VERSION 5.8 ;
BUSBITCHARS "[]" ;
DIVIDERCHAR "/" ;
UNITS
    DATABASE MICRONS 1000 ;
END UNITS

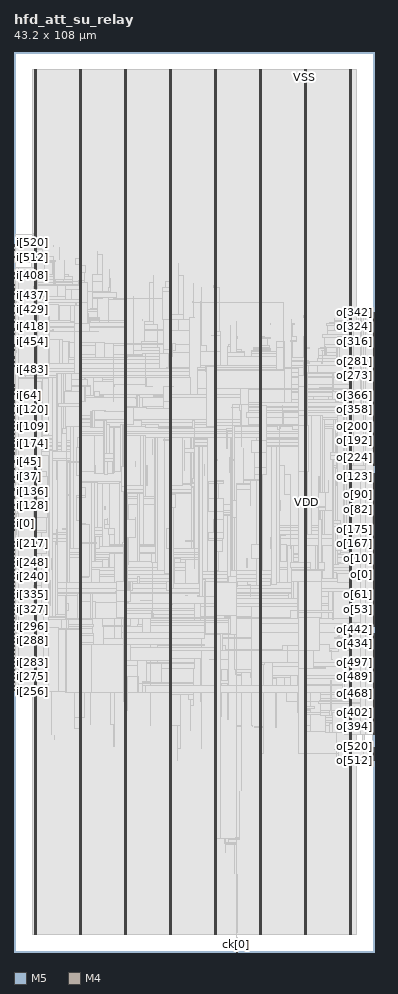
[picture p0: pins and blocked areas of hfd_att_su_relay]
MACRO hfd_att_su_relay
  FOREIGN hfd_att_su_relay 0 0 ;
  CLASS BLOCK ;
  SIZE 43.2 BY 108 ;
  PIN ck[0]
    DIRECTION INPUT ;
    USE SIGNAL ;
    PORT
      LAYER M5 ;
        RECT  26.64 0 26.664 0.084 ;
    END
  END ck[0]
  PIN i[0]
    DIRECTION INPUT ;
    USE SIGNAL ;
    PORT
      LAYER M4 ;
        RECT  0 50.448 0.084 50.472 ;
    END
  END i[0]
  PIN i[100]
    DIRECTION INPUT ;
    USE SIGNAL ;
    PORT
      LAYER M4 ;
        RECT  0 63.12 0.084 63.144 ;
    END
  END i[100]
  PIN i[101]
    DIRECTION INPUT ;
    USE SIGNAL ;
    PORT
      LAYER M4 ;
        RECT  0 63.216 0.084 63.24 ;
    END
  END i[101]
  PIN i[102]
    DIRECTION INPUT ;
    USE SIGNAL ;
    PORT
      LAYER M4 ;
        RECT  0 63.312 0.084 63.336 ;
    END
  END i[102]
  PIN i[103]
    DIRECTION INPUT ;
    USE SIGNAL ;
    PORT
      LAYER M4 ;
        RECT  0 63.408 0.084 63.432 ;
    END
  END i[103]
  PIN i[104]
    DIRECTION INPUT ;
    USE SIGNAL ;
    PORT
      LAYER M4 ;
        RECT  0 63.504 0.084 63.528 ;
    END
  END i[104]
  PIN i[105]
    DIRECTION INPUT ;
    USE SIGNAL ;
    PORT
      LAYER M4 ;
        RECT  0 63.6 0.084 63.624 ;
    END
  END i[105]
  PIN i[106]
    DIRECTION INPUT ;
    USE SIGNAL ;
    PORT
      LAYER M4 ;
        RECT  0 63.696 0.084 63.72 ;
    END
  END i[106]
  PIN i[107]
    DIRECTION INPUT ;
    USE SIGNAL ;
    PORT
      LAYER M4 ;
        RECT  0 63.792 0.084 63.816 ;
    END
  END i[107]
  PIN i[108]
    DIRECTION INPUT ;
    USE SIGNAL ;
    PORT
      LAYER M4 ;
        RECT  0 63.888 0.084 63.912 ;
    END
  END i[108]
  PIN i[109]
    DIRECTION INPUT ;
    USE SIGNAL ;
    PORT
      LAYER M4 ;
        RECT  0 63.984 0.084 64.008 ;
    END
  END i[109]
  PIN i[10]
    DIRECTION INPUT ;
    USE SIGNAL ;
    PORT
      LAYER M4 ;
        RECT  0 51.408 0.084 51.432 ;
    END
  END i[10]
  PIN i[110]
    DIRECTION INPUT ;
    USE SIGNAL ;
    PORT
      LAYER M4 ;
        RECT  0 64.08 0.084 64.104 ;
    END
  END i[110]
  PIN i[111]
    DIRECTION INPUT ;
    USE SIGNAL ;
    PORT
      LAYER M4 ;
        RECT  0 64.176 0.084 64.2 ;
    END
  END i[111]
  PIN i[112]
    DIRECTION INPUT ;
    USE SIGNAL ;
    PORT
      LAYER M4 ;
        RECT  0 64.272 0.084 64.296 ;
    END
  END i[112]
  PIN i[113]
    DIRECTION INPUT ;
    USE SIGNAL ;
    PORT
      LAYER M4 ;
        RECT  0 64.368 0.084 64.392 ;
    END
  END i[113]
  PIN i[114]
    DIRECTION INPUT ;
    USE SIGNAL ;
    PORT
      LAYER M4 ;
        RECT  0 64.464 0.084 64.488 ;
    END
  END i[114]
  PIN i[115]
    DIRECTION INPUT ;
    USE SIGNAL ;
    PORT
      LAYER M4 ;
        RECT  0 64.56 0.084 64.584 ;
    END
  END i[115]
  PIN i[116]
    DIRECTION INPUT ;
    USE SIGNAL ;
    PORT
      LAYER M4 ;
        RECT  0 64.656 0.084 64.68 ;
    END
  END i[116]
  PIN i[117]
    DIRECTION INPUT ;
    USE SIGNAL ;
    PORT
      LAYER M4 ;
        RECT  0 64.752 0.084 64.776 ;
    END
  END i[117]
  PIN i[118]
    DIRECTION INPUT ;
    USE SIGNAL ;
    PORT
      LAYER M4 ;
        RECT  0 64.848 0.084 64.872 ;
    END
  END i[118]
  PIN i[119]
    DIRECTION INPUT ;
    USE SIGNAL ;
    PORT
      LAYER M4 ;
        RECT  0 64.944 0.084 64.968 ;
    END
  END i[119]
  PIN i[11]
    DIRECTION INPUT ;
    USE SIGNAL ;
    PORT
      LAYER M4 ;
        RECT  0 51.504 0.084 51.528 ;
    END
  END i[11]
  PIN i[120]
    DIRECTION INPUT ;
    USE SIGNAL ;
    PORT
      LAYER M4 ;
        RECT  0 65.04 0.084 65.064 ;
    END
  END i[120]
  PIN i[121]
    DIRECTION INPUT ;
    USE SIGNAL ;
    PORT
      LAYER M4 ;
        RECT  0 65.136 0.084 65.16 ;
    END
  END i[121]
  PIN i[122]
    DIRECTION INPUT ;
    USE SIGNAL ;
    PORT
      LAYER M4 ;
        RECT  0 65.232 0.084 65.256 ;
    END
  END i[122]
  PIN i[123]
    DIRECTION INPUT ;
    USE SIGNAL ;
    PORT
      LAYER M4 ;
        RECT  0 65.328 0.084 65.352 ;
    END
  END i[123]
  PIN i[124]
    DIRECTION INPUT ;
    USE SIGNAL ;
    PORT
      LAYER M4 ;
        RECT  0 65.424 0.084 65.448 ;
    END
  END i[124]
  PIN i[125]
    DIRECTION INPUT ;
    USE SIGNAL ;
    PORT
      LAYER M4 ;
        RECT  0 65.52 0.084 65.544 ;
    END
  END i[125]
  PIN i[126]
    DIRECTION INPUT ;
    USE SIGNAL ;
    PORT
      LAYER M4 ;
        RECT  0 65.616 0.084 65.64 ;
    END
  END i[126]
  PIN i[127]
    DIRECTION INPUT ;
    USE SIGNAL ;
    PORT
      LAYER M4 ;
        RECT  0 65.712 0.084 65.736 ;
    END
  END i[127]
  PIN i[128]
    DIRECTION INPUT ;
    USE SIGNAL ;
    PORT
      LAYER M4 ;
        RECT  0 53.52 0.084 53.544 ;
    END
  END i[128]
  PIN i[129]
    DIRECTION INPUT ;
    USE SIGNAL ;
    PORT
      LAYER M4 ;
        RECT  0 53.616 0.084 53.64 ;
    END
  END i[129]
  PIN i[12]
    DIRECTION INPUT ;
    USE SIGNAL ;
    PORT
      LAYER M4 ;
        RECT  0 51.6 0.084 51.624 ;
    END
  END i[12]
  PIN i[130]
    DIRECTION INPUT ;
    USE SIGNAL ;
    PORT
      LAYER M4 ;
        RECT  0 53.712 0.084 53.736 ;
    END
  END i[130]
  PIN i[131]
    DIRECTION INPUT ;
    USE SIGNAL ;
    PORT
      LAYER M4 ;
        RECT  0 53.808 0.084 53.832 ;
    END
  END i[131]
  PIN i[132]
    DIRECTION INPUT ;
    USE SIGNAL ;
    PORT
      LAYER M4 ;
        RECT  0 53.904 0.084 53.928 ;
    END
  END i[132]
  PIN i[133]
    DIRECTION INPUT ;
    USE SIGNAL ;
    PORT
      LAYER M4 ;
        RECT  0 54 0.084 54.024 ;
    END
  END i[133]
  PIN i[134]
    DIRECTION INPUT ;
    USE SIGNAL ;
    PORT
      LAYER M4 ;
        RECT  0 54.096 0.084 54.12 ;
    END
  END i[134]
  PIN i[135]
    DIRECTION INPUT ;
    USE SIGNAL ;
    PORT
      LAYER M4 ;
        RECT  0 54.192 0.084 54.216 ;
    END
  END i[135]
  PIN i[136]
    DIRECTION INPUT ;
    USE SIGNAL ;
    PORT
      LAYER M4 ;
        RECT  0 54.288 0.084 54.312 ;
    END
  END i[136]
  PIN i[137]
    DIRECTION INPUT ;
    USE SIGNAL ;
    PORT
      LAYER M4 ;
        RECT  0 54.384 0.084 54.408 ;
    END
  END i[137]
  PIN i[138]
    DIRECTION INPUT ;
    USE SIGNAL ;
    PORT
      LAYER M4 ;
        RECT  0 54.48 0.084 54.504 ;
    END
  END i[138]
  PIN i[139]
    DIRECTION INPUT ;
    USE SIGNAL ;
    PORT
      LAYER M4 ;
        RECT  0 54.576 0.084 54.6 ;
    END
  END i[139]
  PIN i[13]
    DIRECTION INPUT ;
    USE SIGNAL ;
    PORT
      LAYER M4 ;
        RECT  0 51.696 0.084 51.72 ;
    END
  END i[13]
  PIN i[140]
    DIRECTION INPUT ;
    USE SIGNAL ;
    PORT
      LAYER M4 ;
        RECT  0 54.672 0.084 54.696 ;
    END
  END i[140]
  PIN i[141]
    DIRECTION INPUT ;
    USE SIGNAL ;
    PORT
      LAYER M4 ;
        RECT  0 54.768 0.084 54.792 ;
    END
  END i[141]
  PIN i[142]
    DIRECTION INPUT ;
    USE SIGNAL ;
    PORT
      LAYER M4 ;
        RECT  0 54.864 0.084 54.888 ;
    END
  END i[142]
  PIN i[143]
    DIRECTION INPUT ;
    USE SIGNAL ;
    PORT
      LAYER M4 ;
        RECT  0 54.96 0.084 54.984 ;
    END
  END i[143]
  PIN i[144]
    DIRECTION INPUT ;
    USE SIGNAL ;
    PORT
      LAYER M4 ;
        RECT  0 55.056 0.084 55.08 ;
    END
  END i[144]
  PIN i[145]
    DIRECTION INPUT ;
    USE SIGNAL ;
    PORT
      LAYER M4 ;
        RECT  0 55.152 0.084 55.176 ;
    END
  END i[145]
  PIN i[146]
    DIRECTION INPUT ;
    USE SIGNAL ;
    PORT
      LAYER M4 ;
        RECT  0 55.248 0.084 55.272 ;
    END
  END i[146]
  PIN i[147]
    DIRECTION INPUT ;
    USE SIGNAL ;
    PORT
      LAYER M4 ;
        RECT  0 55.344 0.084 55.368 ;
    END
  END i[147]
  PIN i[148]
    DIRECTION INPUT ;
    USE SIGNAL ;
    PORT
      LAYER M4 ;
        RECT  0 55.44 0.084 55.464 ;
    END
  END i[148]
  PIN i[149]
    DIRECTION INPUT ;
    USE SIGNAL ;
    PORT
      LAYER M4 ;
        RECT  0 55.536 0.084 55.56 ;
    END
  END i[149]
  PIN i[14]
    DIRECTION INPUT ;
    USE SIGNAL ;
    PORT
      LAYER M4 ;
        RECT  0 51.792 0.084 51.816 ;
    END
  END i[14]
  PIN i[150]
    DIRECTION INPUT ;
    USE SIGNAL ;
    PORT
      LAYER M4 ;
        RECT  0 55.632 0.084 55.656 ;
    END
  END i[150]
  PIN i[151]
    DIRECTION INPUT ;
    USE SIGNAL ;
    PORT
      LAYER M4 ;
        RECT  0 55.728 0.084 55.752 ;
    END
  END i[151]
  PIN i[152]
    DIRECTION INPUT ;
    USE SIGNAL ;
    PORT
      LAYER M4 ;
        RECT  0 55.824 0.084 55.848 ;
    END
  END i[152]
  PIN i[153]
    DIRECTION INPUT ;
    USE SIGNAL ;
    PORT
      LAYER M4 ;
        RECT  0 55.92 0.084 55.944 ;
    END
  END i[153]
  PIN i[154]
    DIRECTION INPUT ;
    USE SIGNAL ;
    PORT
      LAYER M4 ;
        RECT  0 56.016 0.084 56.04 ;
    END
  END i[154]
  PIN i[155]
    DIRECTION INPUT ;
    USE SIGNAL ;
    PORT
      LAYER M4 ;
        RECT  0 56.112 0.084 56.136 ;
    END
  END i[155]
  PIN i[156]
    DIRECTION INPUT ;
    USE SIGNAL ;
    PORT
      LAYER M4 ;
        RECT  0 56.208 0.084 56.232 ;
    END
  END i[156]
  PIN i[157]
    DIRECTION INPUT ;
    USE SIGNAL ;
    PORT
      LAYER M4 ;
        RECT  0 56.304 0.084 56.328 ;
    END
  END i[157]
  PIN i[158]
    DIRECTION INPUT ;
    USE SIGNAL ;
    PORT
      LAYER M4 ;
        RECT  0 56.4 0.084 56.424 ;
    END
  END i[158]
  PIN i[159]
    DIRECTION INPUT ;
    USE SIGNAL ;
    PORT
      LAYER M4 ;
        RECT  0 56.496 0.084 56.52 ;
    END
  END i[159]
  PIN i[15]
    DIRECTION INPUT ;
    USE SIGNAL ;
    PORT
      LAYER M4 ;
        RECT  0 51.888 0.084 51.912 ;
    END
  END i[15]
  PIN i[160]
    DIRECTION INPUT ;
    USE SIGNAL ;
    PORT
      LAYER M4 ;
        RECT  0 59.664 0.084 59.688 ;
    END
  END i[160]
  PIN i[161]
    DIRECTION INPUT ;
    USE SIGNAL ;
    PORT
      LAYER M4 ;
        RECT  0 59.76 0.084 59.784 ;
    END
  END i[161]
  PIN i[162]
    DIRECTION INPUT ;
    USE SIGNAL ;
    PORT
      LAYER M4 ;
        RECT  0 59.856 0.084 59.88 ;
    END
  END i[162]
  PIN i[163]
    DIRECTION INPUT ;
    USE SIGNAL ;
    PORT
      LAYER M4 ;
        RECT  0 59.952 0.084 59.976 ;
    END
  END i[163]
  PIN i[164]
    DIRECTION INPUT ;
    USE SIGNAL ;
    PORT
      LAYER M4 ;
        RECT  0 60.048 0.084 60.072 ;
    END
  END i[164]
  PIN i[165]
    DIRECTION INPUT ;
    USE SIGNAL ;
    PORT
      LAYER M4 ;
        RECT  0 60.144 0.084 60.168 ;
    END
  END i[165]
  PIN i[166]
    DIRECTION INPUT ;
    USE SIGNAL ;
    PORT
      LAYER M4 ;
        RECT  0 60.24 0.084 60.264 ;
    END
  END i[166]
  PIN i[167]
    DIRECTION INPUT ;
    USE SIGNAL ;
    PORT
      LAYER M4 ;
        RECT  0 60.336 0.084 60.36 ;
    END
  END i[167]
  PIN i[168]
    DIRECTION INPUT ;
    USE SIGNAL ;
    PORT
      LAYER M4 ;
        RECT  0 60.432 0.084 60.456 ;
    END
  END i[168]
  PIN i[169]
    DIRECTION INPUT ;
    USE SIGNAL ;
    PORT
      LAYER M4 ;
        RECT  0 60.528 0.084 60.552 ;
    END
  END i[169]
  PIN i[16]
    DIRECTION INPUT ;
    USE SIGNAL ;
    PORT
      LAYER M4 ;
        RECT  0 51.984 0.084 52.008 ;
    END
  END i[16]
  PIN i[170]
    DIRECTION INPUT ;
    USE SIGNAL ;
    PORT
      LAYER M4 ;
        RECT  0 60.624 0.084 60.648 ;
    END
  END i[170]
  PIN i[171]
    DIRECTION INPUT ;
    USE SIGNAL ;
    PORT
      LAYER M4 ;
        RECT  0 60.72 0.084 60.744 ;
    END
  END i[171]
  PIN i[172]
    DIRECTION INPUT ;
    USE SIGNAL ;
    PORT
      LAYER M4 ;
        RECT  0 60.816 0.084 60.84 ;
    END
  END i[172]
  PIN i[173]
    DIRECTION INPUT ;
    USE SIGNAL ;
    PORT
      LAYER M4 ;
        RECT  0 60.912 0.084 60.936 ;
    END
  END i[173]
  PIN i[174]
    DIRECTION INPUT ;
    USE SIGNAL ;
    PORT
      LAYER M4 ;
        RECT  0 61.008 0.084 61.032 ;
    END
  END i[174]
  PIN i[175]
    DIRECTION INPUT ;
    USE SIGNAL ;
    PORT
      LAYER M4 ;
        RECT  0 61.104 0.084 61.128 ;
    END
  END i[175]
  PIN i[176]
    DIRECTION INPUT ;
    USE SIGNAL ;
    PORT
      LAYER M4 ;
        RECT  0 61.2 0.084 61.224 ;
    END
  END i[176]
  PIN i[177]
    DIRECTION INPUT ;
    USE SIGNAL ;
    PORT
      LAYER M4 ;
        RECT  0 61.296 0.084 61.32 ;
    END
  END i[177]
  PIN i[178]
    DIRECTION INPUT ;
    USE SIGNAL ;
    PORT
      LAYER M4 ;
        RECT  0 61.392 0.084 61.416 ;
    END
  END i[178]
  PIN i[179]
    DIRECTION INPUT ;
    USE SIGNAL ;
    PORT
      LAYER M4 ;
        RECT  0 61.488 0.084 61.512 ;
    END
  END i[179]
  PIN i[17]
    DIRECTION INPUT ;
    USE SIGNAL ;
    PORT
      LAYER M4 ;
        RECT  0 52.08 0.084 52.104 ;
    END
  END i[17]
  PIN i[180]
    DIRECTION INPUT ;
    USE SIGNAL ;
    PORT
      LAYER M4 ;
        RECT  0 61.584 0.084 61.608 ;
    END
  END i[180]
  PIN i[181]
    DIRECTION INPUT ;
    USE SIGNAL ;
    PORT
      LAYER M4 ;
        RECT  0 61.68 0.084 61.704 ;
    END
  END i[181]
  PIN i[182]
    DIRECTION INPUT ;
    USE SIGNAL ;
    PORT
      LAYER M4 ;
        RECT  0 61.776 0.084 61.8 ;
    END
  END i[182]
  PIN i[183]
    DIRECTION INPUT ;
    USE SIGNAL ;
    PORT
      LAYER M4 ;
        RECT  0 61.872 0.084 61.896 ;
    END
  END i[183]
  PIN i[184]
    DIRECTION INPUT ;
    USE SIGNAL ;
    PORT
      LAYER M4 ;
        RECT  0 61.968 0.084 61.992 ;
    END
  END i[184]
  PIN i[185]
    DIRECTION INPUT ;
    USE SIGNAL ;
    PORT
      LAYER M4 ;
        RECT  0 62.064 0.084 62.088 ;
    END
  END i[185]
  PIN i[186]
    DIRECTION INPUT ;
    USE SIGNAL ;
    PORT
      LAYER M4 ;
        RECT  0 62.16 0.084 62.184 ;
    END
  END i[186]
  PIN i[187]
    DIRECTION INPUT ;
    USE SIGNAL ;
    PORT
      LAYER M4 ;
        RECT  0 62.256 0.084 62.28 ;
    END
  END i[187]
  PIN i[188]
    DIRECTION INPUT ;
    USE SIGNAL ;
    PORT
      LAYER M4 ;
        RECT  0 62.352 0.084 62.376 ;
    END
  END i[188]
  PIN i[189]
    DIRECTION INPUT ;
    USE SIGNAL ;
    PORT
      LAYER M4 ;
        RECT  0 62.448 0.084 62.472 ;
    END
  END i[189]
  PIN i[18]
    DIRECTION INPUT ;
    USE SIGNAL ;
    PORT
      LAYER M4 ;
        RECT  0 52.176 0.084 52.2 ;
    END
  END i[18]
  PIN i[190]
    DIRECTION INPUT ;
    USE SIGNAL ;
    PORT
      LAYER M4 ;
        RECT  0 62.544 0.084 62.568 ;
    END
  END i[190]
  PIN i[191]
    DIRECTION INPUT ;
    USE SIGNAL ;
    PORT
      LAYER M4 ;
        RECT  0 62.64 0.084 62.664 ;
    END
  END i[191]
  PIN i[192]
    DIRECTION INPUT ;
    USE SIGNAL ;
    PORT
      LAYER M4 ;
        RECT  0 46.608 0.084 46.632 ;
    END
  END i[192]
  PIN i[193]
    DIRECTION INPUT ;
    USE SIGNAL ;
    PORT
      LAYER M4 ;
        RECT  0 46.704 0.084 46.728 ;
    END
  END i[193]
  PIN i[194]
    DIRECTION INPUT ;
    USE SIGNAL ;
    PORT
      LAYER M4 ;
        RECT  0 46.8 0.084 46.824 ;
    END
  END i[194]
  PIN i[195]
    DIRECTION INPUT ;
    USE SIGNAL ;
    PORT
      LAYER M4 ;
        RECT  0 46.896 0.084 46.92 ;
    END
  END i[195]
  PIN i[196]
    DIRECTION INPUT ;
    USE SIGNAL ;
    PORT
      LAYER M4 ;
        RECT  0 46.992 0.084 47.016 ;
    END
  END i[196]
  PIN i[197]
    DIRECTION INPUT ;
    USE SIGNAL ;
    PORT
      LAYER M4 ;
        RECT  0 47.088 0.084 47.112 ;
    END
  END i[197]
  PIN i[198]
    DIRECTION INPUT ;
    USE SIGNAL ;
    PORT
      LAYER M4 ;
        RECT  0 47.184 0.084 47.208 ;
    END
  END i[198]
  PIN i[199]
    DIRECTION INPUT ;
    USE SIGNAL ;
    PORT
      LAYER M4 ;
        RECT  0 47.28 0.084 47.304 ;
    END
  END i[199]
  PIN i[19]
    DIRECTION INPUT ;
    USE SIGNAL ;
    PORT
      LAYER M4 ;
        RECT  0 52.272 0.084 52.296 ;
    END
  END i[19]
  PIN i[1]
    DIRECTION INPUT ;
    USE SIGNAL ;
    PORT
      LAYER M4 ;
        RECT  0 50.544 0.084 50.568 ;
    END
  END i[1]
  PIN i[200]
    DIRECTION INPUT ;
    USE SIGNAL ;
    PORT
      LAYER M4 ;
        RECT  0 47.376 0.084 47.4 ;
    END
  END i[200]
  PIN i[201]
    DIRECTION INPUT ;
    USE SIGNAL ;
    PORT
      LAYER M4 ;
        RECT  0 47.472 0.084 47.496 ;
    END
  END i[201]
  PIN i[202]
    DIRECTION INPUT ;
    USE SIGNAL ;
    PORT
      LAYER M4 ;
        RECT  0 47.568 0.084 47.592 ;
    END
  END i[202]
  PIN i[203]
    DIRECTION INPUT ;
    USE SIGNAL ;
    PORT
      LAYER M4 ;
        RECT  0 47.664 0.084 47.688 ;
    END
  END i[203]
  PIN i[204]
    DIRECTION INPUT ;
    USE SIGNAL ;
    PORT
      LAYER M4 ;
        RECT  0 47.76 0.084 47.784 ;
    END
  END i[204]
  PIN i[205]
    DIRECTION INPUT ;
    USE SIGNAL ;
    PORT
      LAYER M4 ;
        RECT  0 47.856 0.084 47.88 ;
    END
  END i[205]
  PIN i[206]
    DIRECTION INPUT ;
    USE SIGNAL ;
    PORT
      LAYER M4 ;
        RECT  0 47.952 0.084 47.976 ;
    END
  END i[206]
  PIN i[207]
    DIRECTION INPUT ;
    USE SIGNAL ;
    PORT
      LAYER M4 ;
        RECT  0 48.048 0.084 48.072 ;
    END
  END i[207]
  PIN i[208]
    DIRECTION INPUT ;
    USE SIGNAL ;
    PORT
      LAYER M4 ;
        RECT  0 48.144 0.084 48.168 ;
    END
  END i[208]
  PIN i[209]
    DIRECTION INPUT ;
    USE SIGNAL ;
    PORT
      LAYER M4 ;
        RECT  0 48.24 0.084 48.264 ;
    END
  END i[209]
  PIN i[20]
    DIRECTION INPUT ;
    USE SIGNAL ;
    PORT
      LAYER M4 ;
        RECT  0 52.368 0.084 52.392 ;
    END
  END i[20]
  PIN i[210]
    DIRECTION INPUT ;
    USE SIGNAL ;
    PORT
      LAYER M4 ;
        RECT  0 48.336 0.084 48.36 ;
    END
  END i[210]
  PIN i[211]
    DIRECTION INPUT ;
    USE SIGNAL ;
    PORT
      LAYER M4 ;
        RECT  0 48.432 0.084 48.456 ;
    END
  END i[211]
  PIN i[212]
    DIRECTION INPUT ;
    USE SIGNAL ;
    PORT
      LAYER M4 ;
        RECT  0 48.528 0.084 48.552 ;
    END
  END i[212]
  PIN i[213]
    DIRECTION INPUT ;
    USE SIGNAL ;
    PORT
      LAYER M4 ;
        RECT  0 48.624 0.084 48.648 ;
    END
  END i[213]
  PIN i[214]
    DIRECTION INPUT ;
    USE SIGNAL ;
    PORT
      LAYER M4 ;
        RECT  0 48.72 0.084 48.744 ;
    END
  END i[214]
  PIN i[215]
    DIRECTION INPUT ;
    USE SIGNAL ;
    PORT
      LAYER M4 ;
        RECT  0 48.816 0.084 48.84 ;
    END
  END i[215]
  PIN i[216]
    DIRECTION INPUT ;
    USE SIGNAL ;
    PORT
      LAYER M4 ;
        RECT  0 48.912 0.084 48.936 ;
    END
  END i[216]
  PIN i[217]
    DIRECTION INPUT ;
    USE SIGNAL ;
    PORT
      LAYER M4 ;
        RECT  0 49.008 0.084 49.032 ;
    END
  END i[217]
  PIN i[218]
    DIRECTION INPUT ;
    USE SIGNAL ;
    PORT
      LAYER M4 ;
        RECT  0 49.104 0.084 49.128 ;
    END
  END i[218]
  PIN i[219]
    DIRECTION INPUT ;
    USE SIGNAL ;
    PORT
      LAYER M4 ;
        RECT  0 49.2 0.084 49.224 ;
    END
  END i[219]
  PIN i[21]
    DIRECTION INPUT ;
    USE SIGNAL ;
    PORT
      LAYER M4 ;
        RECT  0 52.464 0.084 52.488 ;
    END
  END i[21]
  PIN i[220]
    DIRECTION INPUT ;
    USE SIGNAL ;
    PORT
      LAYER M4 ;
        RECT  0 49.296 0.084 49.32 ;
    END
  END i[220]
  PIN i[221]
    DIRECTION INPUT ;
    USE SIGNAL ;
    PORT
      LAYER M4 ;
        RECT  0 49.392 0.084 49.416 ;
    END
  END i[221]
  PIN i[222]
    DIRECTION INPUT ;
    USE SIGNAL ;
    PORT
      LAYER M4 ;
        RECT  0 49.488 0.084 49.512 ;
    END
  END i[222]
  PIN i[223]
    DIRECTION INPUT ;
    USE SIGNAL ;
    PORT
      LAYER M4 ;
        RECT  0 49.584 0.084 49.608 ;
    END
  END i[223]
  PIN i[224]
    DIRECTION INPUT ;
    USE SIGNAL ;
    PORT
      LAYER M4 ;
        RECT  0 43.536 0.084 43.56 ;
    END
  END i[224]
  PIN i[225]
    DIRECTION INPUT ;
    USE SIGNAL ;
    PORT
      LAYER M4 ;
        RECT  0 43.632 0.084 43.656 ;
    END
  END i[225]
  PIN i[226]
    DIRECTION INPUT ;
    USE SIGNAL ;
    PORT
      LAYER M4 ;
        RECT  0 43.728 0.084 43.752 ;
    END
  END i[226]
  PIN i[227]
    DIRECTION INPUT ;
    USE SIGNAL ;
    PORT
      LAYER M4 ;
        RECT  0 43.824 0.084 43.848 ;
    END
  END i[227]
  PIN i[228]
    DIRECTION INPUT ;
    USE SIGNAL ;
    PORT
      LAYER M4 ;
        RECT  0 43.92 0.084 43.944 ;
    END
  END i[228]
  PIN i[229]
    DIRECTION INPUT ;
    USE SIGNAL ;
    PORT
      LAYER M4 ;
        RECT  0 44.016 0.084 44.04 ;
    END
  END i[229]
  PIN i[22]
    DIRECTION INPUT ;
    USE SIGNAL ;
    PORT
      LAYER M4 ;
        RECT  0 52.56 0.084 52.584 ;
    END
  END i[22]
  PIN i[230]
    DIRECTION INPUT ;
    USE SIGNAL ;
    PORT
      LAYER M4 ;
        RECT  0 44.112 0.084 44.136 ;
    END
  END i[230]
  PIN i[231]
    DIRECTION INPUT ;
    USE SIGNAL ;
    PORT
      LAYER M4 ;
        RECT  0 44.208 0.084 44.232 ;
    END
  END i[231]
  PIN i[232]
    DIRECTION INPUT ;
    USE SIGNAL ;
    PORT
      LAYER M4 ;
        RECT  0 44.304 0.084 44.328 ;
    END
  END i[232]
  PIN i[233]
    DIRECTION INPUT ;
    USE SIGNAL ;
    PORT
      LAYER M4 ;
        RECT  0 44.4 0.084 44.424 ;
    END
  END i[233]
  PIN i[234]
    DIRECTION INPUT ;
    USE SIGNAL ;
    PORT
      LAYER M4 ;
        RECT  0 44.496 0.084 44.52 ;
    END
  END i[234]
  PIN i[235]
    DIRECTION INPUT ;
    USE SIGNAL ;
    PORT
      LAYER M4 ;
        RECT  0 44.592 0.084 44.616 ;
    END
  END i[235]
  PIN i[236]
    DIRECTION INPUT ;
    USE SIGNAL ;
    PORT
      LAYER M4 ;
        RECT  0 44.688 0.084 44.712 ;
    END
  END i[236]
  PIN i[237]
    DIRECTION INPUT ;
    USE SIGNAL ;
    PORT
      LAYER M4 ;
        RECT  0 44.784 0.084 44.808 ;
    END
  END i[237]
  PIN i[238]
    DIRECTION INPUT ;
    USE SIGNAL ;
    PORT
      LAYER M4 ;
        RECT  0 44.88 0.084 44.904 ;
    END
  END i[238]
  PIN i[239]
    DIRECTION INPUT ;
    USE SIGNAL ;
    PORT
      LAYER M4 ;
        RECT  0 44.976 0.084 45 ;
    END
  END i[239]
  PIN i[23]
    DIRECTION INPUT ;
    USE SIGNAL ;
    PORT
      LAYER M4 ;
        RECT  0 52.656 0.084 52.68 ;
    END
  END i[23]
  PIN i[240]
    DIRECTION INPUT ;
    USE SIGNAL ;
    PORT
      LAYER M4 ;
        RECT  0 45.072 0.084 45.096 ;
    END
  END i[240]
  PIN i[241]
    DIRECTION INPUT ;
    USE SIGNAL ;
    PORT
      LAYER M4 ;
        RECT  0 45.168 0.084 45.192 ;
    END
  END i[241]
  PIN i[242]
    DIRECTION INPUT ;
    USE SIGNAL ;
    PORT
      LAYER M4 ;
        RECT  0 45.264 0.084 45.288 ;
    END
  END i[242]
  PIN i[243]
    DIRECTION INPUT ;
    USE SIGNAL ;
    PORT
      LAYER M4 ;
        RECT  0 45.36 0.084 45.384 ;
    END
  END i[243]
  PIN i[244]
    DIRECTION INPUT ;
    USE SIGNAL ;
    PORT
      LAYER M4 ;
        RECT  0 45.456 0.084 45.48 ;
    END
  END i[244]
  PIN i[245]
    DIRECTION INPUT ;
    USE SIGNAL ;
    PORT
      LAYER M4 ;
        RECT  0 45.552 0.084 45.576 ;
    END
  END i[245]
  PIN i[246]
    DIRECTION INPUT ;
    USE SIGNAL ;
    PORT
      LAYER M4 ;
        RECT  0 45.648 0.084 45.672 ;
    END
  END i[246]
  PIN i[247]
    DIRECTION INPUT ;
    USE SIGNAL ;
    PORT
      LAYER M4 ;
        RECT  0 45.744 0.084 45.768 ;
    END
  END i[247]
  PIN i[248]
    DIRECTION INPUT ;
    USE SIGNAL ;
    PORT
      LAYER M4 ;
        RECT  0 45.84 0.084 45.864 ;
    END
  END i[248]
  PIN i[249]
    DIRECTION INPUT ;
    USE SIGNAL ;
    PORT
      LAYER M4 ;
        RECT  0 45.936 0.084 45.96 ;
    END
  END i[249]
  PIN i[24]
    DIRECTION INPUT ;
    USE SIGNAL ;
    PORT
      LAYER M4 ;
        RECT  0 52.752 0.084 52.776 ;
    END
  END i[24]
  PIN i[250]
    DIRECTION INPUT ;
    USE SIGNAL ;
    PORT
      LAYER M4 ;
        RECT  0 46.032 0.084 46.056 ;
    END
  END i[250]
  PIN i[251]
    DIRECTION INPUT ;
    USE SIGNAL ;
    PORT
      LAYER M4 ;
        RECT  0 46.128 0.084 46.152 ;
    END
  END i[251]
  PIN i[252]
    DIRECTION INPUT ;
    USE SIGNAL ;
    PORT
      LAYER M4 ;
        RECT  0 46.224 0.084 46.248 ;
    END
  END i[252]
  PIN i[253]
    DIRECTION INPUT ;
    USE SIGNAL ;
    PORT
      LAYER M4 ;
        RECT  0 46.32 0.084 46.344 ;
    END
  END i[253]
  PIN i[254]
    DIRECTION INPUT ;
    USE SIGNAL ;
    PORT
      LAYER M4 ;
        RECT  0 46.416 0.084 46.44 ;
    END
  END i[254]
  PIN i[255]
    DIRECTION INPUT ;
    USE SIGNAL ;
    PORT
      LAYER M4 ;
        RECT  0 46.512 0.084 46.536 ;
    END
  END i[255]
  PIN i[256]
    DIRECTION INPUT ;
    USE SIGNAL ;
    PORT
      LAYER M4 ;
        RECT  0 31.248 0.084 31.272 ;
    END
  END i[256]
  PIN i[257]
    DIRECTION INPUT ;
    USE SIGNAL ;
    PORT
      LAYER M4 ;
        RECT  0 31.344 0.084 31.368 ;
    END
  END i[257]
  PIN i[258]
    DIRECTION INPUT ;
    USE SIGNAL ;
    PORT
      LAYER M4 ;
        RECT  0 31.44 0.084 31.464 ;
    END
  END i[258]
  PIN i[259]
    DIRECTION INPUT ;
    USE SIGNAL ;
    PORT
      LAYER M4 ;
        RECT  0 31.536 0.084 31.56 ;
    END
  END i[259]
  PIN i[25]
    DIRECTION INPUT ;
    USE SIGNAL ;
    PORT
      LAYER M4 ;
        RECT  0 52.848 0.084 52.872 ;
    END
  END i[25]
  PIN i[260]
    DIRECTION INPUT ;
    USE SIGNAL ;
    PORT
      LAYER M4 ;
        RECT  0 31.632 0.084 31.656 ;
    END
  END i[260]
  PIN i[261]
    DIRECTION INPUT ;
    USE SIGNAL ;
    PORT
      LAYER M4 ;
        RECT  0 31.728 0.084 31.752 ;
    END
  END i[261]
  PIN i[262]
    DIRECTION INPUT ;
    USE SIGNAL ;
    PORT
      LAYER M4 ;
        RECT  0 31.824 0.084 31.848 ;
    END
  END i[262]
  PIN i[263]
    DIRECTION INPUT ;
    USE SIGNAL ;
    PORT
      LAYER M4 ;
        RECT  0 31.92 0.084 31.944 ;
    END
  END i[263]
  PIN i[264]
    DIRECTION INPUT ;
    USE SIGNAL ;
    PORT
      LAYER M4 ;
        RECT  0 32.016 0.084 32.04 ;
    END
  END i[264]
  PIN i[265]
    DIRECTION INPUT ;
    USE SIGNAL ;
    PORT
      LAYER M4 ;
        RECT  0 32.112 0.084 32.136 ;
    END
  END i[265]
  PIN i[266]
    DIRECTION INPUT ;
    USE SIGNAL ;
    PORT
      LAYER M4 ;
        RECT  0 32.208 0.084 32.232 ;
    END
  END i[266]
  PIN i[267]
    DIRECTION INPUT ;
    USE SIGNAL ;
    PORT
      LAYER M4 ;
        RECT  0 32.304 0.084 32.328 ;
    END
  END i[267]
  PIN i[268]
    DIRECTION INPUT ;
    USE SIGNAL ;
    PORT
      LAYER M4 ;
        RECT  0 32.4 0.084 32.424 ;
    END
  END i[268]
  PIN i[269]
    DIRECTION INPUT ;
    USE SIGNAL ;
    PORT
      LAYER M4 ;
        RECT  0 32.496 0.084 32.52 ;
    END
  END i[269]
  PIN i[26]
    DIRECTION INPUT ;
    USE SIGNAL ;
    PORT
      LAYER M4 ;
        RECT  0 52.944 0.084 52.968 ;
    END
  END i[26]
  PIN i[270]
    DIRECTION INPUT ;
    USE SIGNAL ;
    PORT
      LAYER M4 ;
        RECT  0 32.592 0.084 32.616 ;
    END
  END i[270]
  PIN i[271]
    DIRECTION INPUT ;
    USE SIGNAL ;
    PORT
      LAYER M4 ;
        RECT  0 32.688 0.084 32.712 ;
    END
  END i[271]
  PIN i[272]
    DIRECTION INPUT ;
    USE SIGNAL ;
    PORT
      LAYER M4 ;
        RECT  0 32.784 0.084 32.808 ;
    END
  END i[272]
  PIN i[273]
    DIRECTION INPUT ;
    USE SIGNAL ;
    PORT
      LAYER M4 ;
        RECT  0 32.88 0.084 32.904 ;
    END
  END i[273]
  PIN i[274]
    DIRECTION INPUT ;
    USE SIGNAL ;
    PORT
      LAYER M4 ;
        RECT  0 32.976 0.084 33 ;
    END
  END i[274]
  PIN i[275]
    DIRECTION INPUT ;
    USE SIGNAL ;
    PORT
      LAYER M4 ;
        RECT  0 33.072 0.084 33.096 ;
    END
  END i[275]
  PIN i[276]
    DIRECTION INPUT ;
    USE SIGNAL ;
    PORT
      LAYER M4 ;
        RECT  0 33.168 0.084 33.192 ;
    END
  END i[276]
  PIN i[277]
    DIRECTION INPUT ;
    USE SIGNAL ;
    PORT
      LAYER M4 ;
        RECT  0 33.264 0.084 33.288 ;
    END
  END i[277]
  PIN i[278]
    DIRECTION INPUT ;
    USE SIGNAL ;
    PORT
      LAYER M4 ;
        RECT  0 33.36 0.084 33.384 ;
    END
  END i[278]
  PIN i[279]
    DIRECTION INPUT ;
    USE SIGNAL ;
    PORT
      LAYER M4 ;
        RECT  0 33.456 0.084 33.48 ;
    END
  END i[279]
  PIN i[27]
    DIRECTION INPUT ;
    USE SIGNAL ;
    PORT
      LAYER M4 ;
        RECT  0 53.04 0.084 53.064 ;
    END
  END i[27]
  PIN i[280]
    DIRECTION INPUT ;
    USE SIGNAL ;
    PORT
      LAYER M4 ;
        RECT  0 33.552 0.084 33.576 ;
    END
  END i[280]
  PIN i[281]
    DIRECTION INPUT ;
    USE SIGNAL ;
    PORT
      LAYER M4 ;
        RECT  0 33.648 0.084 33.672 ;
    END
  END i[281]
  PIN i[282]
    DIRECTION INPUT ;
    USE SIGNAL ;
    PORT
      LAYER M4 ;
        RECT  0 33.744 0.084 33.768 ;
    END
  END i[282]
  PIN i[283]
    DIRECTION INPUT ;
    USE SIGNAL ;
    PORT
      LAYER M4 ;
        RECT  0 33.84 0.084 33.864 ;
    END
  END i[283]
  PIN i[284]
    DIRECTION INPUT ;
    USE SIGNAL ;
    PORT
      LAYER M4 ;
        RECT  0 33.936 0.084 33.96 ;
    END
  END i[284]
  PIN i[285]
    DIRECTION INPUT ;
    USE SIGNAL ;
    PORT
      LAYER M4 ;
        RECT  0 34.032 0.084 34.056 ;
    END
  END i[285]
  PIN i[286]
    DIRECTION INPUT ;
    USE SIGNAL ;
    PORT
      LAYER M4 ;
        RECT  0 34.128 0.084 34.152 ;
    END
  END i[286]
  PIN i[287]
    DIRECTION INPUT ;
    USE SIGNAL ;
    PORT
      LAYER M4 ;
        RECT  0 34.224 0.084 34.248 ;
    END
  END i[287]
  PIN i[288]
    DIRECTION INPUT ;
    USE SIGNAL ;
    PORT
      LAYER M4 ;
        RECT  0 37.392 0.084 37.416 ;
    END
  END i[288]
  PIN i[289]
    DIRECTION INPUT ;
    USE SIGNAL ;
    PORT
      LAYER M4 ;
        RECT  0 37.488 0.084 37.512 ;
    END
  END i[289]
  PIN i[28]
    DIRECTION INPUT ;
    USE SIGNAL ;
    PORT
      LAYER M4 ;
        RECT  0 53.136 0.084 53.16 ;
    END
  END i[28]
  PIN i[290]
    DIRECTION INPUT ;
    USE SIGNAL ;
    PORT
      LAYER M4 ;
        RECT  0 37.584 0.084 37.608 ;
    END
  END i[290]
  PIN i[291]
    DIRECTION INPUT ;
    USE SIGNAL ;
    PORT
      LAYER M4 ;
        RECT  0 37.68 0.084 37.704 ;
    END
  END i[291]
  PIN i[292]
    DIRECTION INPUT ;
    USE SIGNAL ;
    PORT
      LAYER M4 ;
        RECT  0 37.776 0.084 37.8 ;
    END
  END i[292]
  PIN i[293]
    DIRECTION INPUT ;
    USE SIGNAL ;
    PORT
      LAYER M4 ;
        RECT  0 37.872 0.084 37.896 ;
    END
  END i[293]
  PIN i[294]
    DIRECTION INPUT ;
    USE SIGNAL ;
    PORT
      LAYER M4 ;
        RECT  0 37.968 0.084 37.992 ;
    END
  END i[294]
  PIN i[295]
    DIRECTION INPUT ;
    USE SIGNAL ;
    PORT
      LAYER M4 ;
        RECT  0 38.064 0.084 38.088 ;
    END
  END i[295]
  PIN i[296]
    DIRECTION INPUT ;
    USE SIGNAL ;
    PORT
      LAYER M4 ;
        RECT  0 38.16 0.084 38.184 ;
    END
  END i[296]
  PIN i[297]
    DIRECTION INPUT ;
    USE SIGNAL ;
    PORT
      LAYER M4 ;
        RECT  0 38.256 0.084 38.28 ;
    END
  END i[297]
  PIN i[298]
    DIRECTION INPUT ;
    USE SIGNAL ;
    PORT
      LAYER M4 ;
        RECT  0 38.352 0.084 38.376 ;
    END
  END i[298]
  PIN i[299]
    DIRECTION INPUT ;
    USE SIGNAL ;
    PORT
      LAYER M4 ;
        RECT  0 38.448 0.084 38.472 ;
    END
  END i[299]
  PIN i[29]
    DIRECTION INPUT ;
    USE SIGNAL ;
    PORT
      LAYER M4 ;
        RECT  0 53.232 0.084 53.256 ;
    END
  END i[29]
  PIN i[2]
    DIRECTION INPUT ;
    USE SIGNAL ;
    PORT
      LAYER M4 ;
        RECT  0 50.64 0.084 50.664 ;
    END
  END i[2]
  PIN i[300]
    DIRECTION INPUT ;
    USE SIGNAL ;
    PORT
      LAYER M4 ;
        RECT  0 38.544 0.084 38.568 ;
    END
  END i[300]
  PIN i[301]
    DIRECTION INPUT ;
    USE SIGNAL ;
    PORT
      LAYER M4 ;
        RECT  0 38.64 0.084 38.664 ;
    END
  END i[301]
  PIN i[302]
    DIRECTION INPUT ;
    USE SIGNAL ;
    PORT
      LAYER M4 ;
        RECT  0 38.736 0.084 38.76 ;
    END
  END i[302]
  PIN i[303]
    DIRECTION INPUT ;
    USE SIGNAL ;
    PORT
      LAYER M4 ;
        RECT  0 38.832 0.084 38.856 ;
    END
  END i[303]
  PIN i[304]
    DIRECTION INPUT ;
    USE SIGNAL ;
    PORT
      LAYER M4 ;
        RECT  0 38.928 0.084 38.952 ;
    END
  END i[304]
  PIN i[305]
    DIRECTION INPUT ;
    USE SIGNAL ;
    PORT
      LAYER M4 ;
        RECT  0 39.024 0.084 39.048 ;
    END
  END i[305]
  PIN i[306]
    DIRECTION INPUT ;
    USE SIGNAL ;
    PORT
      LAYER M4 ;
        RECT  0 39.12 0.084 39.144 ;
    END
  END i[306]
  PIN i[307]
    DIRECTION INPUT ;
    USE SIGNAL ;
    PORT
      LAYER M4 ;
        RECT  0 39.216 0.084 39.24 ;
    END
  END i[307]
  PIN i[308]
    DIRECTION INPUT ;
    USE SIGNAL ;
    PORT
      LAYER M4 ;
        RECT  0 39.312 0.084 39.336 ;
    END
  END i[308]
  PIN i[309]
    DIRECTION INPUT ;
    USE SIGNAL ;
    PORT
      LAYER M4 ;
        RECT  0 39.408 0.084 39.432 ;
    END
  END i[309]
  PIN i[30]
    DIRECTION INPUT ;
    USE SIGNAL ;
    PORT
      LAYER M4 ;
        RECT  0 53.328 0.084 53.352 ;
    END
  END i[30]
  PIN i[310]
    DIRECTION INPUT ;
    USE SIGNAL ;
    PORT
      LAYER M4 ;
        RECT  0 39.504 0.084 39.528 ;
    END
  END i[310]
  PIN i[311]
    DIRECTION INPUT ;
    USE SIGNAL ;
    PORT
      LAYER M4 ;
        RECT  0 39.6 0.084 39.624 ;
    END
  END i[311]
  PIN i[312]
    DIRECTION INPUT ;
    USE SIGNAL ;
    PORT
      LAYER M4 ;
        RECT  0 39.696 0.084 39.72 ;
    END
  END i[312]
  PIN i[313]
    DIRECTION INPUT ;
    USE SIGNAL ;
    PORT
      LAYER M4 ;
        RECT  0 39.792 0.084 39.816 ;
    END
  END i[313]
  PIN i[314]
    DIRECTION INPUT ;
    USE SIGNAL ;
    PORT
      LAYER M4 ;
        RECT  0 39.888 0.084 39.912 ;
    END
  END i[314]
  PIN i[315]
    DIRECTION INPUT ;
    USE SIGNAL ;
    PORT
      LAYER M4 ;
        RECT  0 39.984 0.084 40.008 ;
    END
  END i[315]
  PIN i[316]
    DIRECTION INPUT ;
    USE SIGNAL ;
    PORT
      LAYER M4 ;
        RECT  0 40.08 0.084 40.104 ;
    END
  END i[316]
  PIN i[317]
    DIRECTION INPUT ;
    USE SIGNAL ;
    PORT
      LAYER M4 ;
        RECT  0 40.176 0.084 40.2 ;
    END
  END i[317]
  PIN i[318]
    DIRECTION INPUT ;
    USE SIGNAL ;
    PORT
      LAYER M4 ;
        RECT  0 40.272 0.084 40.296 ;
    END
  END i[318]
  PIN i[319]
    DIRECTION INPUT ;
    USE SIGNAL ;
    PORT
      LAYER M4 ;
        RECT  0 40.368 0.084 40.392 ;
    END
  END i[319]
  PIN i[31]
    DIRECTION INPUT ;
    USE SIGNAL ;
    PORT
      LAYER M4 ;
        RECT  0 53.424 0.084 53.448 ;
    END
  END i[31]
  PIN i[320]
    DIRECTION INPUT ;
    USE SIGNAL ;
    PORT
      LAYER M4 ;
        RECT  0 40.464 0.084 40.488 ;
    END
  END i[320]
  PIN i[321]
    DIRECTION INPUT ;
    USE SIGNAL ;
    PORT
      LAYER M4 ;
        RECT  0 40.56 0.084 40.584 ;
    END
  END i[321]
  PIN i[322]
    DIRECTION INPUT ;
    USE SIGNAL ;
    PORT
      LAYER M4 ;
        RECT  0 40.656 0.084 40.68 ;
    END
  END i[322]
  PIN i[323]
    DIRECTION INPUT ;
    USE SIGNAL ;
    PORT
      LAYER M4 ;
        RECT  0 40.752 0.084 40.776 ;
    END
  END i[323]
  PIN i[324]
    DIRECTION INPUT ;
    USE SIGNAL ;
    PORT
      LAYER M4 ;
        RECT  0 40.848 0.084 40.872 ;
    END
  END i[324]
  PIN i[325]
    DIRECTION INPUT ;
    USE SIGNAL ;
    PORT
      LAYER M4 ;
        RECT  0 40.944 0.084 40.968 ;
    END
  END i[325]
  PIN i[326]
    DIRECTION INPUT ;
    USE SIGNAL ;
    PORT
      LAYER M4 ;
        RECT  0 41.04 0.084 41.064 ;
    END
  END i[326]
  PIN i[327]
    DIRECTION INPUT ;
    USE SIGNAL ;
    PORT
      LAYER M4 ;
        RECT  0 41.136 0.084 41.16 ;
    END
  END i[327]
  PIN i[328]
    DIRECTION INPUT ;
    USE SIGNAL ;
    PORT
      LAYER M4 ;
        RECT  0 41.232 0.084 41.256 ;
    END
  END i[328]
  PIN i[329]
    DIRECTION INPUT ;
    USE SIGNAL ;
    PORT
      LAYER M4 ;
        RECT  0 41.328 0.084 41.352 ;
    END
  END i[329]
  PIN i[32]
    DIRECTION INPUT ;
    USE SIGNAL ;
    PORT
      LAYER M4 ;
        RECT  0 56.592 0.084 56.616 ;
    END
  END i[32]
  PIN i[330]
    DIRECTION INPUT ;
    USE SIGNAL ;
    PORT
      LAYER M4 ;
        RECT  0 41.424 0.084 41.448 ;
    END
  END i[330]
  PIN i[331]
    DIRECTION INPUT ;
    USE SIGNAL ;
    PORT
      LAYER M4 ;
        RECT  0 41.52 0.084 41.544 ;
    END
  END i[331]
  PIN i[332]
    DIRECTION INPUT ;
    USE SIGNAL ;
    PORT
      LAYER M4 ;
        RECT  0 41.616 0.084 41.64 ;
    END
  END i[332]
  PIN i[333]
    DIRECTION INPUT ;
    USE SIGNAL ;
    PORT
      LAYER M4 ;
        RECT  0 41.712 0.084 41.736 ;
    END
  END i[333]
  PIN i[334]
    DIRECTION INPUT ;
    USE SIGNAL ;
    PORT
      LAYER M4 ;
        RECT  0 41.808 0.084 41.832 ;
    END
  END i[334]
  PIN i[335]
    DIRECTION INPUT ;
    USE SIGNAL ;
    PORT
      LAYER M4 ;
        RECT  0 41.904 0.084 41.928 ;
    END
  END i[335]
  PIN i[336]
    DIRECTION INPUT ;
    USE SIGNAL ;
    PORT
      LAYER M4 ;
        RECT  0 42 0.084 42.024 ;
    END
  END i[336]
  PIN i[337]
    DIRECTION INPUT ;
    USE SIGNAL ;
    PORT
      LAYER M4 ;
        RECT  0 42.096 0.084 42.12 ;
    END
  END i[337]
  PIN i[338]
    DIRECTION INPUT ;
    USE SIGNAL ;
    PORT
      LAYER M4 ;
        RECT  0 42.192 0.084 42.216 ;
    END
  END i[338]
  PIN i[339]
    DIRECTION INPUT ;
    USE SIGNAL ;
    PORT
      LAYER M4 ;
        RECT  0 42.288 0.084 42.312 ;
    END
  END i[339]
  PIN i[33]
    DIRECTION INPUT ;
    USE SIGNAL ;
    PORT
      LAYER M4 ;
        RECT  0 56.688 0.084 56.712 ;
    END
  END i[33]
  PIN i[340]
    DIRECTION INPUT ;
    USE SIGNAL ;
    PORT
      LAYER M4 ;
        RECT  0 42.384 0.084 42.408 ;
    END
  END i[340]
  PIN i[341]
    DIRECTION INPUT ;
    USE SIGNAL ;
    PORT
      LAYER M4 ;
        RECT  0 42.48 0.084 42.504 ;
    END
  END i[341]
  PIN i[342]
    DIRECTION INPUT ;
    USE SIGNAL ;
    PORT
      LAYER M4 ;
        RECT  0 42.576 0.084 42.6 ;
    END
  END i[342]
  PIN i[343]
    DIRECTION INPUT ;
    USE SIGNAL ;
    PORT
      LAYER M4 ;
        RECT  0 42.672 0.084 42.696 ;
    END
  END i[343]
  PIN i[344]
    DIRECTION INPUT ;
    USE SIGNAL ;
    PORT
      LAYER M4 ;
        RECT  0 42.768 0.084 42.792 ;
    END
  END i[344]
  PIN i[345]
    DIRECTION INPUT ;
    USE SIGNAL ;
    PORT
      LAYER M4 ;
        RECT  0 42.864 0.084 42.888 ;
    END
  END i[345]
  PIN i[346]
    DIRECTION INPUT ;
    USE SIGNAL ;
    PORT
      LAYER M4 ;
        RECT  0 42.96 0.084 42.984 ;
    END
  END i[346]
  PIN i[347]
    DIRECTION INPUT ;
    USE SIGNAL ;
    PORT
      LAYER M4 ;
        RECT  0 43.056 0.084 43.08 ;
    END
  END i[347]
  PIN i[348]
    DIRECTION INPUT ;
    USE SIGNAL ;
    PORT
      LAYER M4 ;
        RECT  0 43.152 0.084 43.176 ;
    END
  END i[348]
  PIN i[349]
    DIRECTION INPUT ;
    USE SIGNAL ;
    PORT
      LAYER M4 ;
        RECT  0 43.248 0.084 43.272 ;
    END
  END i[349]
  PIN i[34]
    DIRECTION INPUT ;
    USE SIGNAL ;
    PORT
      LAYER M4 ;
        RECT  0 56.784 0.084 56.808 ;
    END
  END i[34]
  PIN i[350]
    DIRECTION INPUT ;
    USE SIGNAL ;
    PORT
      LAYER M4 ;
        RECT  0 43.344 0.084 43.368 ;
    END
  END i[350]
  PIN i[351]
    DIRECTION INPUT ;
    USE SIGNAL ;
    PORT
      LAYER M4 ;
        RECT  0 43.44 0.084 43.464 ;
    END
  END i[351]
  PIN i[352]
    DIRECTION INPUT ;
    USE SIGNAL ;
    PORT
      LAYER M4 ;
        RECT  0 34.32 0.084 34.344 ;
    END
  END i[352]
  PIN i[353]
    DIRECTION INPUT ;
    USE SIGNAL ;
    PORT
      LAYER M4 ;
        RECT  0 34.416 0.084 34.44 ;
    END
  END i[353]
  PIN i[354]
    DIRECTION INPUT ;
    USE SIGNAL ;
    PORT
      LAYER M4 ;
        RECT  0 34.512 0.084 34.536 ;
    END
  END i[354]
  PIN i[355]
    DIRECTION INPUT ;
    USE SIGNAL ;
    PORT
      LAYER M4 ;
        RECT  0 34.608 0.084 34.632 ;
    END
  END i[355]
  PIN i[356]
    DIRECTION INPUT ;
    USE SIGNAL ;
    PORT
      LAYER M4 ;
        RECT  0 34.704 0.084 34.728 ;
    END
  END i[356]
  PIN i[357]
    DIRECTION INPUT ;
    USE SIGNAL ;
    PORT
      LAYER M4 ;
        RECT  0 34.8 0.084 34.824 ;
    END
  END i[357]
  PIN i[358]
    DIRECTION INPUT ;
    USE SIGNAL ;
    PORT
      LAYER M4 ;
        RECT  0 34.896 0.084 34.92 ;
    END
  END i[358]
  PIN i[359]
    DIRECTION INPUT ;
    USE SIGNAL ;
    PORT
      LAYER M4 ;
        RECT  0 34.992 0.084 35.016 ;
    END
  END i[359]
  PIN i[35]
    DIRECTION INPUT ;
    USE SIGNAL ;
    PORT
      LAYER M4 ;
        RECT  0 56.88 0.084 56.904 ;
    END
  END i[35]
  PIN i[360]
    DIRECTION INPUT ;
    USE SIGNAL ;
    PORT
      LAYER M4 ;
        RECT  0 35.088 0.084 35.112 ;
    END
  END i[360]
  PIN i[361]
    DIRECTION INPUT ;
    USE SIGNAL ;
    PORT
      LAYER M4 ;
        RECT  0 35.184 0.084 35.208 ;
    END
  END i[361]
  PIN i[362]
    DIRECTION INPUT ;
    USE SIGNAL ;
    PORT
      LAYER M4 ;
        RECT  0 35.28 0.084 35.304 ;
    END
  END i[362]
  PIN i[363]
    DIRECTION INPUT ;
    USE SIGNAL ;
    PORT
      LAYER M4 ;
        RECT  0 35.376 0.084 35.4 ;
    END
  END i[363]
  PIN i[364]
    DIRECTION INPUT ;
    USE SIGNAL ;
    PORT
      LAYER M4 ;
        RECT  0 35.472 0.084 35.496 ;
    END
  END i[364]
  PIN i[365]
    DIRECTION INPUT ;
    USE SIGNAL ;
    PORT
      LAYER M4 ;
        RECT  0 35.568 0.084 35.592 ;
    END
  END i[365]
  PIN i[366]
    DIRECTION INPUT ;
    USE SIGNAL ;
    PORT
      LAYER M4 ;
        RECT  0 35.664 0.084 35.688 ;
    END
  END i[366]
  PIN i[367]
    DIRECTION INPUT ;
    USE SIGNAL ;
    PORT
      LAYER M4 ;
        RECT  0 35.76 0.084 35.784 ;
    END
  END i[367]
  PIN i[368]
    DIRECTION INPUT ;
    USE SIGNAL ;
    PORT
      LAYER M4 ;
        RECT  0 35.856 0.084 35.88 ;
    END
  END i[368]
  PIN i[369]
    DIRECTION INPUT ;
    USE SIGNAL ;
    PORT
      LAYER M4 ;
        RECT  0 35.952 0.084 35.976 ;
    END
  END i[369]
  PIN i[36]
    DIRECTION INPUT ;
    USE SIGNAL ;
    PORT
      LAYER M4 ;
        RECT  0 56.976 0.084 57 ;
    END
  END i[36]
  PIN i[370]
    DIRECTION INPUT ;
    USE SIGNAL ;
    PORT
      LAYER M4 ;
        RECT  0 36.048 0.084 36.072 ;
    END
  END i[370]
  PIN i[371]
    DIRECTION INPUT ;
    USE SIGNAL ;
    PORT
      LAYER M4 ;
        RECT  0 36.144 0.084 36.168 ;
    END
  END i[371]
  PIN i[372]
    DIRECTION INPUT ;
    USE SIGNAL ;
    PORT
      LAYER M4 ;
        RECT  0 36.24 0.084 36.264 ;
    END
  END i[372]
  PIN i[373]
    DIRECTION INPUT ;
    USE SIGNAL ;
    PORT
      LAYER M4 ;
        RECT  0 36.336 0.084 36.36 ;
    END
  END i[373]
  PIN i[374]
    DIRECTION INPUT ;
    USE SIGNAL ;
    PORT
      LAYER M4 ;
        RECT  0 36.432 0.084 36.456 ;
    END
  END i[374]
  PIN i[375]
    DIRECTION INPUT ;
    USE SIGNAL ;
    PORT
      LAYER M4 ;
        RECT  0 36.528 0.084 36.552 ;
    END
  END i[375]
  PIN i[376]
    DIRECTION INPUT ;
    USE SIGNAL ;
    PORT
      LAYER M4 ;
        RECT  0 36.624 0.084 36.648 ;
    END
  END i[376]
  PIN i[377]
    DIRECTION INPUT ;
    USE SIGNAL ;
    PORT
      LAYER M4 ;
        RECT  0 36.72 0.084 36.744 ;
    END
  END i[377]
  PIN i[378]
    DIRECTION INPUT ;
    USE SIGNAL ;
    PORT
      LAYER M4 ;
        RECT  0 36.816 0.084 36.84 ;
    END
  END i[378]
  PIN i[379]
    DIRECTION INPUT ;
    USE SIGNAL ;
    PORT
      LAYER M4 ;
        RECT  0 36.912 0.084 36.936 ;
    END
  END i[379]
  PIN i[37]
    DIRECTION INPUT ;
    USE SIGNAL ;
    PORT
      LAYER M4 ;
        RECT  0 57.072 0.084 57.096 ;
    END
  END i[37]
  PIN i[380]
    DIRECTION INPUT ;
    USE SIGNAL ;
    PORT
      LAYER M4 ;
        RECT  0 37.008 0.084 37.032 ;
    END
  END i[380]
  PIN i[381]
    DIRECTION INPUT ;
    USE SIGNAL ;
    PORT
      LAYER M4 ;
        RECT  0 37.104 0.084 37.128 ;
    END
  END i[381]
  PIN i[382]
    DIRECTION INPUT ;
    USE SIGNAL ;
    PORT
      LAYER M4 ;
        RECT  0 37.2 0.084 37.224 ;
    END
  END i[382]
  PIN i[383]
    DIRECTION INPUT ;
    USE SIGNAL ;
    PORT
      LAYER M4 ;
        RECT  0 37.296 0.084 37.32 ;
    END
  END i[383]
  PIN i[384]
    DIRECTION INPUT ;
    USE SIGNAL ;
    PORT
      LAYER M4 ;
        RECT  0 78.864 0.084 78.888 ;
    END
  END i[384]
  PIN i[385]
    DIRECTION INPUT ;
    USE SIGNAL ;
    PORT
      LAYER M4 ;
        RECT  0 78.96 0.084 78.984 ;
    END
  END i[385]
  PIN i[386]
    DIRECTION INPUT ;
    USE SIGNAL ;
    PORT
      LAYER M4 ;
        RECT  0 79.056 0.084 79.08 ;
    END
  END i[386]
  PIN i[387]
    DIRECTION INPUT ;
    USE SIGNAL ;
    PORT
      LAYER M4 ;
        RECT  0 79.152 0.084 79.176 ;
    END
  END i[387]
  PIN i[388]
    DIRECTION INPUT ;
    USE SIGNAL ;
    PORT
      LAYER M4 ;
        RECT  0 79.248 0.084 79.272 ;
    END
  END i[388]
  PIN i[389]
    DIRECTION INPUT ;
    USE SIGNAL ;
    PORT
      LAYER M4 ;
        RECT  0 79.344 0.084 79.368 ;
    END
  END i[389]
  PIN i[38]
    DIRECTION INPUT ;
    USE SIGNAL ;
    PORT
      LAYER M4 ;
        RECT  0 57.168 0.084 57.192 ;
    END
  END i[38]
  PIN i[390]
    DIRECTION INPUT ;
    USE SIGNAL ;
    PORT
      LAYER M4 ;
        RECT  0 79.44 0.084 79.464 ;
    END
  END i[390]
  PIN i[391]
    DIRECTION INPUT ;
    USE SIGNAL ;
    PORT
      LAYER M4 ;
        RECT  0 79.536 0.084 79.56 ;
    END
  END i[391]
  PIN i[392]
    DIRECTION INPUT ;
    USE SIGNAL ;
    PORT
      LAYER M4 ;
        RECT  0 79.632 0.084 79.656 ;
    END
  END i[392]
  PIN i[393]
    DIRECTION INPUT ;
    USE SIGNAL ;
    PORT
      LAYER M4 ;
        RECT  0 79.728 0.084 79.752 ;
    END
  END i[393]
  PIN i[394]
    DIRECTION INPUT ;
    USE SIGNAL ;
    PORT
      LAYER M4 ;
        RECT  0 79.824 0.084 79.848 ;
    END
  END i[394]
  PIN i[395]
    DIRECTION INPUT ;
    USE SIGNAL ;
    PORT
      LAYER M4 ;
        RECT  0 79.92 0.084 79.944 ;
    END
  END i[395]
  PIN i[396]
    DIRECTION INPUT ;
    USE SIGNAL ;
    PORT
      LAYER M4 ;
        RECT  0 80.016 0.084 80.04 ;
    END
  END i[396]
  PIN i[397]
    DIRECTION INPUT ;
    USE SIGNAL ;
    PORT
      LAYER M4 ;
        RECT  0 80.112 0.084 80.136 ;
    END
  END i[397]
  PIN i[398]
    DIRECTION INPUT ;
    USE SIGNAL ;
    PORT
      LAYER M4 ;
        RECT  0 80.208 0.084 80.232 ;
    END
  END i[398]
  PIN i[399]
    DIRECTION INPUT ;
    USE SIGNAL ;
    PORT
      LAYER M4 ;
        RECT  0 80.304 0.084 80.328 ;
    END
  END i[399]
  PIN i[39]
    DIRECTION INPUT ;
    USE SIGNAL ;
    PORT
      LAYER M4 ;
        RECT  0 57.264 0.084 57.288 ;
    END
  END i[39]
  PIN i[3]
    DIRECTION INPUT ;
    USE SIGNAL ;
    PORT
      LAYER M4 ;
        RECT  0 50.736 0.084 50.76 ;
    END
  END i[3]
  PIN i[400]
    DIRECTION INPUT ;
    USE SIGNAL ;
    PORT
      LAYER M4 ;
        RECT  0 80.4 0.084 80.424 ;
    END
  END i[400]
  PIN i[401]
    DIRECTION INPUT ;
    USE SIGNAL ;
    PORT
      LAYER M4 ;
        RECT  0 80.496 0.084 80.52 ;
    END
  END i[401]
  PIN i[402]
    DIRECTION INPUT ;
    USE SIGNAL ;
    PORT
      LAYER M4 ;
        RECT  0 80.592 0.084 80.616 ;
    END
  END i[402]
  PIN i[403]
    DIRECTION INPUT ;
    USE SIGNAL ;
    PORT
      LAYER M4 ;
        RECT  0 80.688 0.084 80.712 ;
    END
  END i[403]
  PIN i[404]
    DIRECTION INPUT ;
    USE SIGNAL ;
    PORT
      LAYER M4 ;
        RECT  0 80.784 0.084 80.808 ;
    END
  END i[404]
  PIN i[405]
    DIRECTION INPUT ;
    USE SIGNAL ;
    PORT
      LAYER M4 ;
        RECT  0 80.88 0.084 80.904 ;
    END
  END i[405]
  PIN i[406]
    DIRECTION INPUT ;
    USE SIGNAL ;
    PORT
      LAYER M4 ;
        RECT  0 80.976 0.084 81 ;
    END
  END i[406]
  PIN i[407]
    DIRECTION INPUT ;
    USE SIGNAL ;
    PORT
      LAYER M4 ;
        RECT  0 81.072 0.084 81.096 ;
    END
  END i[407]
  PIN i[408]
    DIRECTION INPUT ;
    USE SIGNAL ;
    PORT
      LAYER M4 ;
        RECT  0 81.168 0.084 81.192 ;
    END
  END i[408]
  PIN i[409]
    DIRECTION INPUT ;
    USE SIGNAL ;
    PORT
      LAYER M4 ;
        RECT  0 81.264 0.084 81.288 ;
    END
  END i[409]
  PIN i[40]
    DIRECTION INPUT ;
    USE SIGNAL ;
    PORT
      LAYER M4 ;
        RECT  0 57.36 0.084 57.384 ;
    END
  END i[40]
  PIN i[410]
    DIRECTION INPUT ;
    USE SIGNAL ;
    PORT
      LAYER M4 ;
        RECT  0 81.36 0.084 81.384 ;
    END
  END i[410]
  PIN i[411]
    DIRECTION INPUT ;
    USE SIGNAL ;
    PORT
      LAYER M4 ;
        RECT  0 81.456 0.084 81.48 ;
    END
  END i[411]
  PIN i[412]
    DIRECTION INPUT ;
    USE SIGNAL ;
    PORT
      LAYER M4 ;
        RECT  0 81.552 0.084 81.576 ;
    END
  END i[412]
  PIN i[413]
    DIRECTION INPUT ;
    USE SIGNAL ;
    PORT
      LAYER M4 ;
        RECT  0 81.648 0.084 81.672 ;
    END
  END i[413]
  PIN i[414]
    DIRECTION INPUT ;
    USE SIGNAL ;
    PORT
      LAYER M4 ;
        RECT  0 81.744 0.084 81.768 ;
    END
  END i[414]
  PIN i[415]
    DIRECTION INPUT ;
    USE SIGNAL ;
    PORT
      LAYER M4 ;
        RECT  0 81.84 0.084 81.864 ;
    END
  END i[415]
  PIN i[416]
    DIRECTION INPUT ;
    USE SIGNAL ;
    PORT
      LAYER M4 ;
        RECT  0 75.792 0.084 75.816 ;
    END
  END i[416]
  PIN i[417]
    DIRECTION INPUT ;
    USE SIGNAL ;
    PORT
      LAYER M4 ;
        RECT  0 75.888 0.084 75.912 ;
    END
  END i[417]
  PIN i[418]
    DIRECTION INPUT ;
    USE SIGNAL ;
    PORT
      LAYER M4 ;
        RECT  0 75.984 0.084 76.008 ;
    END
  END i[418]
  PIN i[419]
    DIRECTION INPUT ;
    USE SIGNAL ;
    PORT
      LAYER M4 ;
        RECT  0 76.08 0.084 76.104 ;
    END
  END i[419]
  PIN i[41]
    DIRECTION INPUT ;
    USE SIGNAL ;
    PORT
      LAYER M4 ;
        RECT  0 57.456 0.084 57.48 ;
    END
  END i[41]
  PIN i[420]
    DIRECTION INPUT ;
    USE SIGNAL ;
    PORT
      LAYER M4 ;
        RECT  0 76.176 0.084 76.2 ;
    END
  END i[420]
  PIN i[421]
    DIRECTION INPUT ;
    USE SIGNAL ;
    PORT
      LAYER M4 ;
        RECT  0 76.272 0.084 76.296 ;
    END
  END i[421]
  PIN i[422]
    DIRECTION INPUT ;
    USE SIGNAL ;
    PORT
      LAYER M4 ;
        RECT  0 76.368 0.084 76.392 ;
    END
  END i[422]
  PIN i[423]
    DIRECTION INPUT ;
    USE SIGNAL ;
    PORT
      LAYER M4 ;
        RECT  0 76.464 0.084 76.488 ;
    END
  END i[423]
  PIN i[424]
    DIRECTION INPUT ;
    USE SIGNAL ;
    PORT
      LAYER M4 ;
        RECT  0 76.56 0.084 76.584 ;
    END
  END i[424]
  PIN i[425]
    DIRECTION INPUT ;
    USE SIGNAL ;
    PORT
      LAYER M4 ;
        RECT  0 76.656 0.084 76.68 ;
    END
  END i[425]
  PIN i[426]
    DIRECTION INPUT ;
    USE SIGNAL ;
    PORT
      LAYER M4 ;
        RECT  0 76.752 0.084 76.776 ;
    END
  END i[426]
  PIN i[427]
    DIRECTION INPUT ;
    USE SIGNAL ;
    PORT
      LAYER M4 ;
        RECT  0 76.848 0.084 76.872 ;
    END
  END i[427]
  PIN i[428]
    DIRECTION INPUT ;
    USE SIGNAL ;
    PORT
      LAYER M4 ;
        RECT  0 76.944 0.084 76.968 ;
    END
  END i[428]
  PIN i[429]
    DIRECTION INPUT ;
    USE SIGNAL ;
    PORT
      LAYER M4 ;
        RECT  0 77.04 0.084 77.064 ;
    END
  END i[429]
  PIN i[42]
    DIRECTION INPUT ;
    USE SIGNAL ;
    PORT
      LAYER M4 ;
        RECT  0 57.552 0.084 57.576 ;
    END
  END i[42]
  PIN i[430]
    DIRECTION INPUT ;
    USE SIGNAL ;
    PORT
      LAYER M4 ;
        RECT  0 77.136 0.084 77.16 ;
    END
  END i[430]
  PIN i[431]
    DIRECTION INPUT ;
    USE SIGNAL ;
    PORT
      LAYER M4 ;
        RECT  0 77.232 0.084 77.256 ;
    END
  END i[431]
  PIN i[432]
    DIRECTION INPUT ;
    USE SIGNAL ;
    PORT
      LAYER M4 ;
        RECT  0 77.328 0.084 77.352 ;
    END
  END i[432]
  PIN i[433]
    DIRECTION INPUT ;
    USE SIGNAL ;
    PORT
      LAYER M4 ;
        RECT  0 77.424 0.084 77.448 ;
    END
  END i[433]
  PIN i[434]
    DIRECTION INPUT ;
    USE SIGNAL ;
    PORT
      LAYER M4 ;
        RECT  0 77.52 0.084 77.544 ;
    END
  END i[434]
  PIN i[435]
    DIRECTION INPUT ;
    USE SIGNAL ;
    PORT
      LAYER M4 ;
        RECT  0 77.616 0.084 77.64 ;
    END
  END i[435]
  PIN i[436]
    DIRECTION INPUT ;
    USE SIGNAL ;
    PORT
      LAYER M4 ;
        RECT  0 77.712 0.084 77.736 ;
    END
  END i[436]
  PIN i[437]
    DIRECTION INPUT ;
    USE SIGNAL ;
    PORT
      LAYER M4 ;
        RECT  0 77.808 0.084 77.832 ;
    END
  END i[437]
  PIN i[438]
    DIRECTION INPUT ;
    USE SIGNAL ;
    PORT
      LAYER M4 ;
        RECT  0 77.904 0.084 77.928 ;
    END
  END i[438]
  PIN i[439]
    DIRECTION INPUT ;
    USE SIGNAL ;
    PORT
      LAYER M4 ;
        RECT  0 78 0.084 78.024 ;
    END
  END i[439]
  PIN i[43]
    DIRECTION INPUT ;
    USE SIGNAL ;
    PORT
      LAYER M4 ;
        RECT  0 57.648 0.084 57.672 ;
    END
  END i[43]
  PIN i[440]
    DIRECTION INPUT ;
    USE SIGNAL ;
    PORT
      LAYER M4 ;
        RECT  0 78.096 0.084 78.12 ;
    END
  END i[440]
  PIN i[441]
    DIRECTION INPUT ;
    USE SIGNAL ;
    PORT
      LAYER M4 ;
        RECT  0 78.192 0.084 78.216 ;
    END
  END i[441]
  PIN i[442]
    DIRECTION INPUT ;
    USE SIGNAL ;
    PORT
      LAYER M4 ;
        RECT  0 78.288 0.084 78.312 ;
    END
  END i[442]
  PIN i[443]
    DIRECTION INPUT ;
    USE SIGNAL ;
    PORT
      LAYER M4 ;
        RECT  0 78.384 0.084 78.408 ;
    END
  END i[443]
  PIN i[444]
    DIRECTION INPUT ;
    USE SIGNAL ;
    PORT
      LAYER M4 ;
        RECT  0 78.48 0.084 78.504 ;
    END
  END i[444]
  PIN i[445]
    DIRECTION INPUT ;
    USE SIGNAL ;
    PORT
      LAYER M4 ;
        RECT  0 78.576 0.084 78.6 ;
    END
  END i[445]
  PIN i[446]
    DIRECTION INPUT ;
    USE SIGNAL ;
    PORT
      LAYER M4 ;
        RECT  0 78.672 0.084 78.696 ;
    END
  END i[446]
  PIN i[447]
    DIRECTION INPUT ;
    USE SIGNAL ;
    PORT
      LAYER M4 ;
        RECT  0 78.768 0.084 78.792 ;
    END
  END i[447]
  PIN i[448]
    DIRECTION INPUT ;
    USE SIGNAL ;
    PORT
      LAYER M4 ;
        RECT  0 72.72 0.084 72.744 ;
    END
  END i[448]
  PIN i[449]
    DIRECTION INPUT ;
    USE SIGNAL ;
    PORT
      LAYER M4 ;
        RECT  0 72.816 0.084 72.84 ;
    END
  END i[449]
  PIN i[44]
    DIRECTION INPUT ;
    USE SIGNAL ;
    PORT
      LAYER M4 ;
        RECT  0 57.744 0.084 57.768 ;
    END
  END i[44]
  PIN i[450]
    DIRECTION INPUT ;
    USE SIGNAL ;
    PORT
      LAYER M4 ;
        RECT  0 72.912 0.084 72.936 ;
    END
  END i[450]
  PIN i[451]
    DIRECTION INPUT ;
    USE SIGNAL ;
    PORT
      LAYER M4 ;
        RECT  0 73.008 0.084 73.032 ;
    END
  END i[451]
  PIN i[452]
    DIRECTION INPUT ;
    USE SIGNAL ;
    PORT
      LAYER M4 ;
        RECT  0 73.104 0.084 73.128 ;
    END
  END i[452]
  PIN i[453]
    DIRECTION INPUT ;
    USE SIGNAL ;
    PORT
      LAYER M4 ;
        RECT  0 73.2 0.084 73.224 ;
    END
  END i[453]
  PIN i[454]
    DIRECTION INPUT ;
    USE SIGNAL ;
    PORT
      LAYER M4 ;
        RECT  0 73.296 0.084 73.32 ;
    END
  END i[454]
  PIN i[455]
    DIRECTION INPUT ;
    USE SIGNAL ;
    PORT
      LAYER M4 ;
        RECT  0 73.392 0.084 73.416 ;
    END
  END i[455]
  PIN i[456]
    DIRECTION INPUT ;
    USE SIGNAL ;
    PORT
      LAYER M4 ;
        RECT  0 73.488 0.084 73.512 ;
    END
  END i[456]
  PIN i[457]
    DIRECTION INPUT ;
    USE SIGNAL ;
    PORT
      LAYER M4 ;
        RECT  0 73.584 0.084 73.608 ;
    END
  END i[457]
  PIN i[458]
    DIRECTION INPUT ;
    USE SIGNAL ;
    PORT
      LAYER M4 ;
        RECT  0 73.68 0.084 73.704 ;
    END
  END i[458]
  PIN i[459]
    DIRECTION INPUT ;
    USE SIGNAL ;
    PORT
      LAYER M4 ;
        RECT  0 73.776 0.084 73.8 ;
    END
  END i[459]
  PIN i[45]
    DIRECTION INPUT ;
    USE SIGNAL ;
    PORT
      LAYER M4 ;
        RECT  0 57.84 0.084 57.864 ;
    END
  END i[45]
  PIN i[460]
    DIRECTION INPUT ;
    USE SIGNAL ;
    PORT
      LAYER M4 ;
        RECT  0 73.872 0.084 73.896 ;
    END
  END i[460]
  PIN i[461]
    DIRECTION INPUT ;
    USE SIGNAL ;
    PORT
      LAYER M4 ;
        RECT  0 73.968 0.084 73.992 ;
    END
  END i[461]
  PIN i[462]
    DIRECTION INPUT ;
    USE SIGNAL ;
    PORT
      LAYER M4 ;
        RECT  0 74.064 0.084 74.088 ;
    END
  END i[462]
  PIN i[463]
    DIRECTION INPUT ;
    USE SIGNAL ;
    PORT
      LAYER M4 ;
        RECT  0 74.16 0.084 74.184 ;
    END
  END i[463]
  PIN i[464]
    DIRECTION INPUT ;
    USE SIGNAL ;
    PORT
      LAYER M4 ;
        RECT  0 74.256 0.084 74.28 ;
    END
  END i[464]
  PIN i[465]
    DIRECTION INPUT ;
    USE SIGNAL ;
    PORT
      LAYER M4 ;
        RECT  0 74.352 0.084 74.376 ;
    END
  END i[465]
  PIN i[466]
    DIRECTION INPUT ;
    USE SIGNAL ;
    PORT
      LAYER M4 ;
        RECT  0 74.448 0.084 74.472 ;
    END
  END i[466]
  PIN i[467]
    DIRECTION INPUT ;
    USE SIGNAL ;
    PORT
      LAYER M4 ;
        RECT  0 74.544 0.084 74.568 ;
    END
  END i[467]
  PIN i[468]
    DIRECTION INPUT ;
    USE SIGNAL ;
    PORT
      LAYER M4 ;
        RECT  0 74.64 0.084 74.664 ;
    END
  END i[468]
  PIN i[469]
    DIRECTION INPUT ;
    USE SIGNAL ;
    PORT
      LAYER M4 ;
        RECT  0 74.736 0.084 74.76 ;
    END
  END i[469]
  PIN i[46]
    DIRECTION INPUT ;
    USE SIGNAL ;
    PORT
      LAYER M4 ;
        RECT  0 57.936 0.084 57.96 ;
    END
  END i[46]
  PIN i[470]
    DIRECTION INPUT ;
    USE SIGNAL ;
    PORT
      LAYER M4 ;
        RECT  0 74.832 0.084 74.856 ;
    END
  END i[470]
  PIN i[471]
    DIRECTION INPUT ;
    USE SIGNAL ;
    PORT
      LAYER M4 ;
        RECT  0 74.928 0.084 74.952 ;
    END
  END i[471]
  PIN i[472]
    DIRECTION INPUT ;
    USE SIGNAL ;
    PORT
      LAYER M4 ;
        RECT  0 75.024 0.084 75.048 ;
    END
  END i[472]
  PIN i[473]
    DIRECTION INPUT ;
    USE SIGNAL ;
    PORT
      LAYER M4 ;
        RECT  0 75.12 0.084 75.144 ;
    END
  END i[473]
  PIN i[474]
    DIRECTION INPUT ;
    USE SIGNAL ;
    PORT
      LAYER M4 ;
        RECT  0 75.216 0.084 75.24 ;
    END
  END i[474]
  PIN i[475]
    DIRECTION INPUT ;
    USE SIGNAL ;
    PORT
      LAYER M4 ;
        RECT  0 75.312 0.084 75.336 ;
    END
  END i[475]
  PIN i[476]
    DIRECTION INPUT ;
    USE SIGNAL ;
    PORT
      LAYER M4 ;
        RECT  0 75.408 0.084 75.432 ;
    END
  END i[476]
  PIN i[477]
    DIRECTION INPUT ;
    USE SIGNAL ;
    PORT
      LAYER M4 ;
        RECT  0 75.504 0.084 75.528 ;
    END
  END i[477]
  PIN i[478]
    DIRECTION INPUT ;
    USE SIGNAL ;
    PORT
      LAYER M4 ;
        RECT  0 75.6 0.084 75.624 ;
    END
  END i[478]
  PIN i[479]
    DIRECTION INPUT ;
    USE SIGNAL ;
    PORT
      LAYER M4 ;
        RECT  0 75.696 0.084 75.72 ;
    END
  END i[479]
  PIN i[47]
    DIRECTION INPUT ;
    USE SIGNAL ;
    PORT
      LAYER M4 ;
        RECT  0 58.032 0.084 58.056 ;
    END
  END i[47]
  PIN i[480]
    DIRECTION INPUT ;
    USE SIGNAL ;
    PORT
      LAYER M4 ;
        RECT  0 69.648 0.084 69.672 ;
    END
  END i[480]
  PIN i[481]
    DIRECTION INPUT ;
    USE SIGNAL ;
    PORT
      LAYER M4 ;
        RECT  0 69.744 0.084 69.768 ;
    END
  END i[481]
  PIN i[482]
    DIRECTION INPUT ;
    USE SIGNAL ;
    PORT
      LAYER M4 ;
        RECT  0 69.84 0.084 69.864 ;
    END
  END i[482]
  PIN i[483]
    DIRECTION INPUT ;
    USE SIGNAL ;
    PORT
      LAYER M4 ;
        RECT  0 69.936 0.084 69.96 ;
    END
  END i[483]
  PIN i[484]
    DIRECTION INPUT ;
    USE SIGNAL ;
    PORT
      LAYER M4 ;
        RECT  0 70.032 0.084 70.056 ;
    END
  END i[484]
  PIN i[485]
    DIRECTION INPUT ;
    USE SIGNAL ;
    PORT
      LAYER M4 ;
        RECT  0 70.128 0.084 70.152 ;
    END
  END i[485]
  PIN i[486]
    DIRECTION INPUT ;
    USE SIGNAL ;
    PORT
      LAYER M4 ;
        RECT  0 70.224 0.084 70.248 ;
    END
  END i[486]
  PIN i[487]
    DIRECTION INPUT ;
    USE SIGNAL ;
    PORT
      LAYER M4 ;
        RECT  0 70.32 0.084 70.344 ;
    END
  END i[487]
  PIN i[488]
    DIRECTION INPUT ;
    USE SIGNAL ;
    PORT
      LAYER M4 ;
        RECT  0 70.416 0.084 70.44 ;
    END
  END i[488]
  PIN i[489]
    DIRECTION INPUT ;
    USE SIGNAL ;
    PORT
      LAYER M4 ;
        RECT  0 70.512 0.084 70.536 ;
    END
  END i[489]
  PIN i[48]
    DIRECTION INPUT ;
    USE SIGNAL ;
    PORT
      LAYER M4 ;
        RECT  0 58.128 0.084 58.152 ;
    END
  END i[48]
  PIN i[490]
    DIRECTION INPUT ;
    USE SIGNAL ;
    PORT
      LAYER M4 ;
        RECT  0 70.608 0.084 70.632 ;
    END
  END i[490]
  PIN i[491]
    DIRECTION INPUT ;
    USE SIGNAL ;
    PORT
      LAYER M4 ;
        RECT  0 70.704 0.084 70.728 ;
    END
  END i[491]
  PIN i[492]
    DIRECTION INPUT ;
    USE SIGNAL ;
    PORT
      LAYER M4 ;
        RECT  0 70.8 0.084 70.824 ;
    END
  END i[492]
  PIN i[493]
    DIRECTION INPUT ;
    USE SIGNAL ;
    PORT
      LAYER M4 ;
        RECT  0 70.896 0.084 70.92 ;
    END
  END i[493]
  PIN i[494]
    DIRECTION INPUT ;
    USE SIGNAL ;
    PORT
      LAYER M4 ;
        RECT  0 70.992 0.084 71.016 ;
    END
  END i[494]
  PIN i[495]
    DIRECTION INPUT ;
    USE SIGNAL ;
    PORT
      LAYER M4 ;
        RECT  0 71.088 0.084 71.112 ;
    END
  END i[495]
  PIN i[496]
    DIRECTION INPUT ;
    USE SIGNAL ;
    PORT
      LAYER M4 ;
        RECT  0 71.184 0.084 71.208 ;
    END
  END i[496]
  PIN i[497]
    DIRECTION INPUT ;
    USE SIGNAL ;
    PORT
      LAYER M4 ;
        RECT  0 71.28 0.084 71.304 ;
    END
  END i[497]
  PIN i[498]
    DIRECTION INPUT ;
    USE SIGNAL ;
    PORT
      LAYER M4 ;
        RECT  0 71.376 0.084 71.4 ;
    END
  END i[498]
  PIN i[499]
    DIRECTION INPUT ;
    USE SIGNAL ;
    PORT
      LAYER M4 ;
        RECT  0 71.472 0.084 71.496 ;
    END
  END i[499]
  PIN i[49]
    DIRECTION INPUT ;
    USE SIGNAL ;
    PORT
      LAYER M4 ;
        RECT  0 58.224 0.084 58.248 ;
    END
  END i[49]
  PIN i[4]
    DIRECTION INPUT ;
    USE SIGNAL ;
    PORT
      LAYER M4 ;
        RECT  0 50.832 0.084 50.856 ;
    END
  END i[4]
  PIN i[500]
    DIRECTION INPUT ;
    USE SIGNAL ;
    PORT
      LAYER M4 ;
        RECT  0 71.568 0.084 71.592 ;
    END
  END i[500]
  PIN i[501]
    DIRECTION INPUT ;
    USE SIGNAL ;
    PORT
      LAYER M4 ;
        RECT  0 71.664 0.084 71.688 ;
    END
  END i[501]
  PIN i[502]
    DIRECTION INPUT ;
    USE SIGNAL ;
    PORT
      LAYER M4 ;
        RECT  0 71.76 0.084 71.784 ;
    END
  END i[502]
  PIN i[503]
    DIRECTION INPUT ;
    USE SIGNAL ;
    PORT
      LAYER M4 ;
        RECT  0 71.856 0.084 71.88 ;
    END
  END i[503]
  PIN i[504]
    DIRECTION INPUT ;
    USE SIGNAL ;
    PORT
      LAYER M4 ;
        RECT  0 71.952 0.084 71.976 ;
    END
  END i[504]
  PIN i[505]
    DIRECTION INPUT ;
    USE SIGNAL ;
    PORT
      LAYER M4 ;
        RECT  0 72.048 0.084 72.072 ;
    END
  END i[505]
  PIN i[506]
    DIRECTION INPUT ;
    USE SIGNAL ;
    PORT
      LAYER M4 ;
        RECT  0 72.144 0.084 72.168 ;
    END
  END i[506]
  PIN i[507]
    DIRECTION INPUT ;
    USE SIGNAL ;
    PORT
      LAYER M4 ;
        RECT  0 72.24 0.084 72.264 ;
    END
  END i[507]
  PIN i[508]
    DIRECTION INPUT ;
    USE SIGNAL ;
    PORT
      LAYER M4 ;
        RECT  0 72.336 0.084 72.36 ;
    END
  END i[508]
  PIN i[509]
    DIRECTION INPUT ;
    USE SIGNAL ;
    PORT
      LAYER M4 ;
        RECT  0 72.432 0.084 72.456 ;
    END
  END i[509]
  PIN i[50]
    DIRECTION INPUT ;
    USE SIGNAL ;
    PORT
      LAYER M4 ;
        RECT  0 58.32 0.084 58.344 ;
    END
  END i[50]
  PIN i[510]
    DIRECTION INPUT ;
    USE SIGNAL ;
    PORT
      LAYER M4 ;
        RECT  0 72.528 0.084 72.552 ;
    END
  END i[510]
  PIN i[511]
    DIRECTION INPUT ;
    USE SIGNAL ;
    PORT
      LAYER M4 ;
        RECT  0 72.624 0.084 72.648 ;
    END
  END i[511]
  PIN i[512]
    DIRECTION INPUT ;
    USE SIGNAL ;
    PORT
      LAYER M4 ;
        RECT  0 83.376 0.084 83.4 ;
    END
  END i[512]
  PIN i[513]
    DIRECTION INPUT ;
    USE SIGNAL ;
    PORT
      LAYER M4 ;
        RECT  0 83.472 0.084 83.496 ;
    END
  END i[513]
  PIN i[514]
    DIRECTION INPUT ;
    USE SIGNAL ;
    PORT
      LAYER M4 ;
        RECT  0 83.568 0.084 83.592 ;
    END
  END i[514]
  PIN i[515]
    DIRECTION INPUT ;
    USE SIGNAL ;
    PORT
      LAYER M4 ;
        RECT  0 83.664 0.084 83.688 ;
    END
  END i[515]
  PIN i[516]
    DIRECTION INPUT ;
    USE SIGNAL ;
    PORT
      LAYER M4 ;
        RECT  0 83.76 0.084 83.784 ;
    END
  END i[516]
  PIN i[517]
    DIRECTION INPUT ;
    USE SIGNAL ;
    PORT
      LAYER M4 ;
        RECT  0 83.856 0.084 83.88 ;
    END
  END i[517]
  PIN i[518]
    DIRECTION INPUT ;
    USE SIGNAL ;
    PORT
      LAYER M4 ;
        RECT  0 83.952 0.084 83.976 ;
    END
  END i[518]
  PIN i[519]
    DIRECTION INPUT ;
    USE SIGNAL ;
    PORT
      LAYER M4 ;
        RECT  0 84.048 0.084 84.072 ;
    END
  END i[519]
  PIN i[51]
    DIRECTION INPUT ;
    USE SIGNAL ;
    PORT
      LAYER M4 ;
        RECT  0 58.416 0.084 58.44 ;
    END
  END i[51]
  PIN i[520]
    DIRECTION INPUT ;
    USE SIGNAL ;
    PORT
      LAYER M4 ;
        RECT  0 84.144 0.084 84.168 ;
    END
  END i[520]
  PIN i[521]
    DIRECTION INPUT ;
    USE SIGNAL ;
    PORT
      LAYER M4 ;
        RECT  0 84.24 0.084 84.264 ;
    END
  END i[521]
  PIN i[522]
    DIRECTION INPUT ;
    USE SIGNAL ;
    PORT
      LAYER M4 ;
        RECT  0 84.336 0.084 84.36 ;
    END
  END i[522]
  PIN i[523]
    DIRECTION INPUT ;
    USE SIGNAL ;
    PORT
      LAYER M4 ;
        RECT  0 84.432 0.084 84.456 ;
    END
  END i[523]
  PIN i[524]
    DIRECTION INPUT ;
    USE SIGNAL ;
    PORT
      LAYER M4 ;
        RECT  0 84.528 0.084 84.552 ;
    END
  END i[524]
  PIN i[525]
    DIRECTION INPUT ;
    USE SIGNAL ;
    PORT
      LAYER M4 ;
        RECT  0 84.624 0.084 84.648 ;
    END
  END i[525]
  PIN i[526]
    DIRECTION INPUT ;
    USE SIGNAL ;
    PORT
      LAYER M4 ;
        RECT  0 84.72 0.084 84.744 ;
    END
  END i[526]
  PIN i[527]
    DIRECTION INPUT ;
    USE SIGNAL ;
    PORT
      LAYER M4 ;
        RECT  0 84.816 0.084 84.84 ;
    END
  END i[527]
  PIN i[528]
    DIRECTION INPUT ;
    USE SIGNAL ;
    PORT
      LAYER M4 ;
        RECT  0 84.912 0.084 84.936 ;
    END
  END i[528]
  PIN i[52]
    DIRECTION INPUT ;
    USE SIGNAL ;
    PORT
      LAYER M4 ;
        RECT  0 58.512 0.084 58.536 ;
    END
  END i[52]
  PIN i[53]
    DIRECTION INPUT ;
    USE SIGNAL ;
    PORT
      LAYER M4 ;
        RECT  0 58.608 0.084 58.632 ;
    END
  END i[53]
  PIN i[54]
    DIRECTION INPUT ;
    USE SIGNAL ;
    PORT
      LAYER M4 ;
        RECT  0 58.704 0.084 58.728 ;
    END
  END i[54]
  PIN i[55]
    DIRECTION INPUT ;
    USE SIGNAL ;
    PORT
      LAYER M4 ;
        RECT  0 58.8 0.084 58.824 ;
    END
  END i[55]
  PIN i[56]
    DIRECTION INPUT ;
    USE SIGNAL ;
    PORT
      LAYER M4 ;
        RECT  0 58.896 0.084 58.92 ;
    END
  END i[56]
  PIN i[57]
    DIRECTION INPUT ;
    USE SIGNAL ;
    PORT
      LAYER M4 ;
        RECT  0 58.992 0.084 59.016 ;
    END
  END i[57]
  PIN i[58]
    DIRECTION INPUT ;
    USE SIGNAL ;
    PORT
      LAYER M4 ;
        RECT  0 59.088 0.084 59.112 ;
    END
  END i[58]
  PIN i[59]
    DIRECTION INPUT ;
    USE SIGNAL ;
    PORT
      LAYER M4 ;
        RECT  0 59.184 0.084 59.208 ;
    END
  END i[59]
  PIN i[5]
    DIRECTION INPUT ;
    USE SIGNAL ;
    PORT
      LAYER M4 ;
        RECT  0 50.928 0.084 50.952 ;
    END
  END i[5]
  PIN i[60]
    DIRECTION INPUT ;
    USE SIGNAL ;
    PORT
      LAYER M4 ;
        RECT  0 59.28 0.084 59.304 ;
    END
  END i[60]
  PIN i[61]
    DIRECTION INPUT ;
    USE SIGNAL ;
    PORT
      LAYER M4 ;
        RECT  0 59.376 0.084 59.4 ;
    END
  END i[61]
  PIN i[62]
    DIRECTION INPUT ;
    USE SIGNAL ;
    PORT
      LAYER M4 ;
        RECT  0 59.472 0.084 59.496 ;
    END
  END i[62]
  PIN i[63]
    DIRECTION INPUT ;
    USE SIGNAL ;
    PORT
      LAYER M4 ;
        RECT  0 59.568 0.084 59.592 ;
    END
  END i[63]
  PIN i[64]
    DIRECTION INPUT ;
    USE SIGNAL ;
    PORT
      LAYER M4 ;
        RECT  0 65.808 0.084 65.832 ;
    END
  END i[64]
  PIN i[65]
    DIRECTION INPUT ;
    USE SIGNAL ;
    PORT
      LAYER M4 ;
        RECT  0 65.904 0.084 65.928 ;
    END
  END i[65]
  PIN i[66]
    DIRECTION INPUT ;
    USE SIGNAL ;
    PORT
      LAYER M4 ;
        RECT  0 66 0.084 66.024 ;
    END
  END i[66]
  PIN i[67]
    DIRECTION INPUT ;
    USE SIGNAL ;
    PORT
      LAYER M4 ;
        RECT  0 66.096 0.084 66.12 ;
    END
  END i[67]
  PIN i[68]
    DIRECTION INPUT ;
    USE SIGNAL ;
    PORT
      LAYER M4 ;
        RECT  0 66.192 0.084 66.216 ;
    END
  END i[68]
  PIN i[69]
    DIRECTION INPUT ;
    USE SIGNAL ;
    PORT
      LAYER M4 ;
        RECT  0 66.288 0.084 66.312 ;
    END
  END i[69]
  PIN i[6]
    DIRECTION INPUT ;
    USE SIGNAL ;
    PORT
      LAYER M4 ;
        RECT  0 51.024 0.084 51.048 ;
    END
  END i[6]
  PIN i[70]
    DIRECTION INPUT ;
    USE SIGNAL ;
    PORT
      LAYER M4 ;
        RECT  0 66.384 0.084 66.408 ;
    END
  END i[70]
  PIN i[71]
    DIRECTION INPUT ;
    USE SIGNAL ;
    PORT
      LAYER M4 ;
        RECT  0 66.48 0.084 66.504 ;
    END
  END i[71]
  PIN i[72]
    DIRECTION INPUT ;
    USE SIGNAL ;
    PORT
      LAYER M4 ;
        RECT  0 66.576 0.084 66.6 ;
    END
  END i[72]
  PIN i[73]
    DIRECTION INPUT ;
    USE SIGNAL ;
    PORT
      LAYER M4 ;
        RECT  0 66.672 0.084 66.696 ;
    END
  END i[73]
  PIN i[74]
    DIRECTION INPUT ;
    USE SIGNAL ;
    PORT
      LAYER M4 ;
        RECT  0 66.768 0.084 66.792 ;
    END
  END i[74]
  PIN i[75]
    DIRECTION INPUT ;
    USE SIGNAL ;
    PORT
      LAYER M4 ;
        RECT  0 66.864 0.084 66.888 ;
    END
  END i[75]
  PIN i[76]
    DIRECTION INPUT ;
    USE SIGNAL ;
    PORT
      LAYER M4 ;
        RECT  0 66.96 0.084 66.984 ;
    END
  END i[76]
  PIN i[77]
    DIRECTION INPUT ;
    USE SIGNAL ;
    PORT
      LAYER M4 ;
        RECT  0 67.056 0.084 67.08 ;
    END
  END i[77]
  PIN i[78]
    DIRECTION INPUT ;
    USE SIGNAL ;
    PORT
      LAYER M4 ;
        RECT  0 67.152 0.084 67.176 ;
    END
  END i[78]
  PIN i[79]
    DIRECTION INPUT ;
    USE SIGNAL ;
    PORT
      LAYER M4 ;
        RECT  0 67.248 0.084 67.272 ;
    END
  END i[79]
  PIN i[7]
    DIRECTION INPUT ;
    USE SIGNAL ;
    PORT
      LAYER M4 ;
        RECT  0 51.12 0.084 51.144 ;
    END
  END i[7]
  PIN i[80]
    DIRECTION INPUT ;
    USE SIGNAL ;
    PORT
      LAYER M4 ;
        RECT  0 67.344 0.084 67.368 ;
    END
  END i[80]
  PIN i[81]
    DIRECTION INPUT ;
    USE SIGNAL ;
    PORT
      LAYER M4 ;
        RECT  0 67.44 0.084 67.464 ;
    END
  END i[81]
  PIN i[82]
    DIRECTION INPUT ;
    USE SIGNAL ;
    PORT
      LAYER M4 ;
        RECT  0 67.536 0.084 67.56 ;
    END
  END i[82]
  PIN i[83]
    DIRECTION INPUT ;
    USE SIGNAL ;
    PORT
      LAYER M4 ;
        RECT  0 67.632 0.084 67.656 ;
    END
  END i[83]
  PIN i[84]
    DIRECTION INPUT ;
    USE SIGNAL ;
    PORT
      LAYER M4 ;
        RECT  0 67.728 0.084 67.752 ;
    END
  END i[84]
  PIN i[85]
    DIRECTION INPUT ;
    USE SIGNAL ;
    PORT
      LAYER M4 ;
        RECT  0 67.824 0.084 67.848 ;
    END
  END i[85]
  PIN i[86]
    DIRECTION INPUT ;
    USE SIGNAL ;
    PORT
      LAYER M4 ;
        RECT  0 67.92 0.084 67.944 ;
    END
  END i[86]
  PIN i[87]
    DIRECTION INPUT ;
    USE SIGNAL ;
    PORT
      LAYER M4 ;
        RECT  0 68.016 0.084 68.04 ;
    END
  END i[87]
  PIN i[88]
    DIRECTION INPUT ;
    USE SIGNAL ;
    PORT
      LAYER M4 ;
        RECT  0 68.112 0.084 68.136 ;
    END
  END i[88]
  PIN i[89]
    DIRECTION INPUT ;
    USE SIGNAL ;
    PORT
      LAYER M4 ;
        RECT  0 68.208 0.084 68.232 ;
    END
  END i[89]
  PIN i[8]
    DIRECTION INPUT ;
    USE SIGNAL ;
    PORT
      LAYER M4 ;
        RECT  0 51.216 0.084 51.24 ;
    END
  END i[8]
  PIN i[90]
    DIRECTION INPUT ;
    USE SIGNAL ;
    PORT
      LAYER M4 ;
        RECT  0 68.304 0.084 68.328 ;
    END
  END i[90]
  PIN i[91]
    DIRECTION INPUT ;
    USE SIGNAL ;
    PORT
      LAYER M4 ;
        RECT  0 68.4 0.084 68.424 ;
    END
  END i[91]
  PIN i[92]
    DIRECTION INPUT ;
    USE SIGNAL ;
    PORT
      LAYER M4 ;
        RECT  0 68.496 0.084 68.52 ;
    END
  END i[92]
  PIN i[93]
    DIRECTION INPUT ;
    USE SIGNAL ;
    PORT
      LAYER M4 ;
        RECT  0 68.592 0.084 68.616 ;
    END
  END i[93]
  PIN i[94]
    DIRECTION INPUT ;
    USE SIGNAL ;
    PORT
      LAYER M4 ;
        RECT  0 68.688 0.084 68.712 ;
    END
  END i[94]
  PIN i[95]
    DIRECTION INPUT ;
    USE SIGNAL ;
    PORT
      LAYER M4 ;
        RECT  0 68.784 0.084 68.808 ;
    END
  END i[95]
  PIN i[96]
    DIRECTION INPUT ;
    USE SIGNAL ;
    PORT
      LAYER M4 ;
        RECT  0 62.736 0.084 62.76 ;
    END
  END i[96]
  PIN i[97]
    DIRECTION INPUT ;
    USE SIGNAL ;
    PORT
      LAYER M4 ;
        RECT  0 62.832 0.084 62.856 ;
    END
  END i[97]
  PIN i[98]
    DIRECTION INPUT ;
    USE SIGNAL ;
    PORT
      LAYER M4 ;
        RECT  0 62.928 0.084 62.952 ;
    END
  END i[98]
  PIN i[99]
    DIRECTION INPUT ;
    USE SIGNAL ;
    PORT
      LAYER M4 ;
        RECT  0 63.024 0.084 63.048 ;
    END
  END i[99]
  PIN i[9]
    DIRECTION INPUT ;
    USE SIGNAL ;
    PORT
      LAYER M4 ;
        RECT  0 51.312 0.084 51.336 ;
    END
  END i[9]
  PIN o[0]
    DIRECTION OUTPUT ;
    USE SIGNAL ;
    PORT
      LAYER M4 ;
        RECT  43.116 45.264 43.2 45.288 ;
    END
  END o[0]
  PIN o[100]
    DIRECTION OUTPUT ;
    USE SIGNAL ;
    PORT
      LAYER M4 ;
        RECT  43.116 54.864 43.2 54.888 ;
    END
  END o[100]
  PIN o[101]
    DIRECTION OUTPUT ;
    USE SIGNAL ;
    PORT
      LAYER M4 ;
        RECT  43.116 54.96 43.2 54.984 ;
    END
  END o[101]
  PIN o[102]
    DIRECTION OUTPUT ;
    USE SIGNAL ;
    PORT
      LAYER M4 ;
        RECT  43.116 55.056 43.2 55.08 ;
    END
  END o[102]
  PIN o[103]
    DIRECTION OUTPUT ;
    USE SIGNAL ;
    PORT
      LAYER M4 ;
        RECT  43.116 55.152 43.2 55.176 ;
    END
  END o[103]
  PIN o[104]
    DIRECTION OUTPUT ;
    USE SIGNAL ;
    PORT
      LAYER M4 ;
        RECT  43.116 55.248 43.2 55.272 ;
    END
  END o[104]
  PIN o[105]
    DIRECTION OUTPUT ;
    USE SIGNAL ;
    PORT
      LAYER M4 ;
        RECT  43.116 55.344 43.2 55.368 ;
    END
  END o[105]
  PIN o[106]
    DIRECTION OUTPUT ;
    USE SIGNAL ;
    PORT
      LAYER M4 ;
        RECT  43.116 55.44 43.2 55.464 ;
    END
  END o[106]
  PIN o[107]
    DIRECTION OUTPUT ;
    USE SIGNAL ;
    PORT
      LAYER M4 ;
        RECT  43.116 55.536 43.2 55.56 ;
    END
  END o[107]
  PIN o[108]
    DIRECTION OUTPUT ;
    USE SIGNAL ;
    PORT
      LAYER M4 ;
        RECT  43.116 55.632 43.2 55.656 ;
    END
  END o[108]
  PIN o[109]
    DIRECTION OUTPUT ;
    USE SIGNAL ;
    PORT
      LAYER M4 ;
        RECT  43.116 55.728 43.2 55.752 ;
    END
  END o[109]
  PIN o[10]
    DIRECTION OUTPUT ;
    USE SIGNAL ;
    PORT
      LAYER M4 ;
        RECT  43.116 46.224 43.2 46.248 ;
    END
  END o[10]
  PIN o[110]
    DIRECTION OUTPUT ;
    USE SIGNAL ;
    PORT
      LAYER M4 ;
        RECT  43.116 55.824 43.2 55.848 ;
    END
  END o[110]
  PIN o[111]
    DIRECTION OUTPUT ;
    USE SIGNAL ;
    PORT
      LAYER M4 ;
        RECT  43.116 55.92 43.2 55.944 ;
    END
  END o[111]
  PIN o[112]
    DIRECTION OUTPUT ;
    USE SIGNAL ;
    PORT
      LAYER M4 ;
        RECT  43.116 56.016 43.2 56.04 ;
    END
  END o[112]
  PIN o[113]
    DIRECTION OUTPUT ;
    USE SIGNAL ;
    PORT
      LAYER M4 ;
        RECT  43.116 56.112 43.2 56.136 ;
    END
  END o[113]
  PIN o[114]
    DIRECTION OUTPUT ;
    USE SIGNAL ;
    PORT
      LAYER M4 ;
        RECT  43.116 56.208 43.2 56.232 ;
    END
  END o[114]
  PIN o[115]
    DIRECTION OUTPUT ;
    USE SIGNAL ;
    PORT
      LAYER M4 ;
        RECT  43.116 56.304 43.2 56.328 ;
    END
  END o[115]
  PIN o[116]
    DIRECTION OUTPUT ;
    USE SIGNAL ;
    PORT
      LAYER M4 ;
        RECT  43.116 56.4 43.2 56.424 ;
    END
  END o[116]
  PIN o[117]
    DIRECTION OUTPUT ;
    USE SIGNAL ;
    PORT
      LAYER M4 ;
        RECT  43.116 56.496 43.2 56.52 ;
    END
  END o[117]
  PIN o[118]
    DIRECTION OUTPUT ;
    USE SIGNAL ;
    PORT
      LAYER M4 ;
        RECT  43.116 56.592 43.2 56.616 ;
    END
  END o[118]
  PIN o[119]
    DIRECTION OUTPUT ;
    USE SIGNAL ;
    PORT
      LAYER M4 ;
        RECT  43.116 56.688 43.2 56.712 ;
    END
  END o[119]
  PIN o[11]
    DIRECTION OUTPUT ;
    USE SIGNAL ;
    PORT
      LAYER M4 ;
        RECT  43.116 46.32 43.2 46.344 ;
    END
  END o[11]
  PIN o[120]
    DIRECTION OUTPUT ;
    USE SIGNAL ;
    PORT
      LAYER M4 ;
        RECT  43.116 56.784 43.2 56.808 ;
    END
  END o[120]
  PIN o[121]
    DIRECTION OUTPUT ;
    USE SIGNAL ;
    PORT
      LAYER M4 ;
        RECT  43.116 56.88 43.2 56.904 ;
    END
  END o[121]
  PIN o[122]
    DIRECTION OUTPUT ;
    USE SIGNAL ;
    PORT
      LAYER M4 ;
        RECT  43.116 56.976 43.2 57 ;
    END
  END o[122]
  PIN o[123]
    DIRECTION OUTPUT ;
    USE SIGNAL ;
    PORT
      LAYER M4 ;
        RECT  43.116 57.072 43.2 57.096 ;
    END
  END o[123]
  PIN o[124]
    DIRECTION OUTPUT ;
    USE SIGNAL ;
    PORT
      LAYER M4 ;
        RECT  43.116 57.168 43.2 57.192 ;
    END
  END o[124]
  PIN o[125]
    DIRECTION OUTPUT ;
    USE SIGNAL ;
    PORT
      LAYER M4 ;
        RECT  43.116 57.264 43.2 57.288 ;
    END
  END o[125]
  PIN o[126]
    DIRECTION OUTPUT ;
    USE SIGNAL ;
    PORT
      LAYER M4 ;
        RECT  43.116 57.36 43.2 57.384 ;
    END
  END o[126]
  PIN o[127]
    DIRECTION OUTPUT ;
    USE SIGNAL ;
    PORT
      LAYER M4 ;
        RECT  43.116 57.456 43.2 57.48 ;
    END
  END o[127]
  PIN o[128]
    DIRECTION OUTPUT ;
    USE SIGNAL ;
    PORT
      LAYER M4 ;
        RECT  43.116 42.192 43.2 42.216 ;
    END
  END o[128]
  PIN o[129]
    DIRECTION OUTPUT ;
    USE SIGNAL ;
    PORT
      LAYER M4 ;
        RECT  43.116 42.288 43.2 42.312 ;
    END
  END o[129]
  PIN o[12]
    DIRECTION OUTPUT ;
    USE SIGNAL ;
    PORT
      LAYER M4 ;
        RECT  43.116 46.416 43.2 46.44 ;
    END
  END o[12]
  PIN o[130]
    DIRECTION OUTPUT ;
    USE SIGNAL ;
    PORT
      LAYER M4 ;
        RECT  43.116 42.384 43.2 42.408 ;
    END
  END o[130]
  PIN o[131]
    DIRECTION OUTPUT ;
    USE SIGNAL ;
    PORT
      LAYER M4 ;
        RECT  43.116 42.48 43.2 42.504 ;
    END
  END o[131]
  PIN o[132]
    DIRECTION OUTPUT ;
    USE SIGNAL ;
    PORT
      LAYER M4 ;
        RECT  43.116 42.576 43.2 42.6 ;
    END
  END o[132]
  PIN o[133]
    DIRECTION OUTPUT ;
    USE SIGNAL ;
    PORT
      LAYER M4 ;
        RECT  43.116 42.672 43.2 42.696 ;
    END
  END o[133]
  PIN o[134]
    DIRECTION OUTPUT ;
    USE SIGNAL ;
    PORT
      LAYER M4 ;
        RECT  43.116 42.768 43.2 42.792 ;
    END
  END o[134]
  PIN o[135]
    DIRECTION OUTPUT ;
    USE SIGNAL ;
    PORT
      LAYER M4 ;
        RECT  43.116 42.864 43.2 42.888 ;
    END
  END o[135]
  PIN o[136]
    DIRECTION OUTPUT ;
    USE SIGNAL ;
    PORT
      LAYER M4 ;
        RECT  43.116 42.96 43.2 42.984 ;
    END
  END o[136]
  PIN o[137]
    DIRECTION OUTPUT ;
    USE SIGNAL ;
    PORT
      LAYER M4 ;
        RECT  43.116 43.056 43.2 43.08 ;
    END
  END o[137]
  PIN o[138]
    DIRECTION OUTPUT ;
    USE SIGNAL ;
    PORT
      LAYER M4 ;
        RECT  43.116 43.152 43.2 43.176 ;
    END
  END o[138]
  PIN o[139]
    DIRECTION OUTPUT ;
    USE SIGNAL ;
    PORT
      LAYER M4 ;
        RECT  43.116 43.248 43.2 43.272 ;
    END
  END o[139]
  PIN o[13]
    DIRECTION OUTPUT ;
    USE SIGNAL ;
    PORT
      LAYER M4 ;
        RECT  43.116 46.512 43.2 46.536 ;
    END
  END o[13]
  PIN o[140]
    DIRECTION OUTPUT ;
    USE SIGNAL ;
    PORT
      LAYER M4 ;
        RECT  43.116 43.344 43.2 43.368 ;
    END
  END o[140]
  PIN o[141]
    DIRECTION OUTPUT ;
    USE SIGNAL ;
    PORT
      LAYER M4 ;
        RECT  43.116 43.44 43.2 43.464 ;
    END
  END o[141]
  PIN o[142]
    DIRECTION OUTPUT ;
    USE SIGNAL ;
    PORT
      LAYER M4 ;
        RECT  43.116 43.536 43.2 43.56 ;
    END
  END o[142]
  PIN o[143]
    DIRECTION OUTPUT ;
    USE SIGNAL ;
    PORT
      LAYER M4 ;
        RECT  43.116 43.632 43.2 43.656 ;
    END
  END o[143]
  PIN o[144]
    DIRECTION OUTPUT ;
    USE SIGNAL ;
    PORT
      LAYER M4 ;
        RECT  43.116 43.728 43.2 43.752 ;
    END
  END o[144]
  PIN o[145]
    DIRECTION OUTPUT ;
    USE SIGNAL ;
    PORT
      LAYER M4 ;
        RECT  43.116 43.824 43.2 43.848 ;
    END
  END o[145]
  PIN o[146]
    DIRECTION OUTPUT ;
    USE SIGNAL ;
    PORT
      LAYER M4 ;
        RECT  43.116 43.92 43.2 43.944 ;
    END
  END o[146]
  PIN o[147]
    DIRECTION OUTPUT ;
    USE SIGNAL ;
    PORT
      LAYER M4 ;
        RECT  43.116 44.016 43.2 44.04 ;
    END
  END o[147]
  PIN o[148]
    DIRECTION OUTPUT ;
    USE SIGNAL ;
    PORT
      LAYER M4 ;
        RECT  43.116 44.112 43.2 44.136 ;
    END
  END o[148]
  PIN o[149]
    DIRECTION OUTPUT ;
    USE SIGNAL ;
    PORT
      LAYER M4 ;
        RECT  43.116 44.208 43.2 44.232 ;
    END
  END o[149]
  PIN o[14]
    DIRECTION OUTPUT ;
    USE SIGNAL ;
    PORT
      LAYER M4 ;
        RECT  43.116 46.608 43.2 46.632 ;
    END
  END o[14]
  PIN o[150]
    DIRECTION OUTPUT ;
    USE SIGNAL ;
    PORT
      LAYER M4 ;
        RECT  43.116 44.304 43.2 44.328 ;
    END
  END o[150]
  PIN o[151]
    DIRECTION OUTPUT ;
    USE SIGNAL ;
    PORT
      LAYER M4 ;
        RECT  43.116 44.4 43.2 44.424 ;
    END
  END o[151]
  PIN o[152]
    DIRECTION OUTPUT ;
    USE SIGNAL ;
    PORT
      LAYER M4 ;
        RECT  43.116 44.496 43.2 44.52 ;
    END
  END o[152]
  PIN o[153]
    DIRECTION OUTPUT ;
    USE SIGNAL ;
    PORT
      LAYER M4 ;
        RECT  43.116 44.592 43.2 44.616 ;
    END
  END o[153]
  PIN o[154]
    DIRECTION OUTPUT ;
    USE SIGNAL ;
    PORT
      LAYER M4 ;
        RECT  43.116 44.688 43.2 44.712 ;
    END
  END o[154]
  PIN o[155]
    DIRECTION OUTPUT ;
    USE SIGNAL ;
    PORT
      LAYER M4 ;
        RECT  43.116 44.784 43.2 44.808 ;
    END
  END o[155]
  PIN o[156]
    DIRECTION OUTPUT ;
    USE SIGNAL ;
    PORT
      LAYER M4 ;
        RECT  43.116 44.88 43.2 44.904 ;
    END
  END o[156]
  PIN o[157]
    DIRECTION OUTPUT ;
    USE SIGNAL ;
    PORT
      LAYER M4 ;
        RECT  43.116 44.976 43.2 45 ;
    END
  END o[157]
  PIN o[158]
    DIRECTION OUTPUT ;
    USE SIGNAL ;
    PORT
      LAYER M4 ;
        RECT  43.116 45.072 43.2 45.096 ;
    END
  END o[158]
  PIN o[159]
    DIRECTION OUTPUT ;
    USE SIGNAL ;
    PORT
      LAYER M4 ;
        RECT  43.116 45.168 43.2 45.192 ;
    END
  END o[159]
  PIN o[15]
    DIRECTION OUTPUT ;
    USE SIGNAL ;
    PORT
      LAYER M4 ;
        RECT  43.116 46.704 43.2 46.728 ;
    END
  END o[15]
  PIN o[160]
    DIRECTION OUTPUT ;
    USE SIGNAL ;
    PORT
      LAYER M4 ;
        RECT  43.116 48.336 43.2 48.36 ;
    END
  END o[160]
  PIN o[161]
    DIRECTION OUTPUT ;
    USE SIGNAL ;
    PORT
      LAYER M4 ;
        RECT  43.116 48.432 43.2 48.456 ;
    END
  END o[161]
  PIN o[162]
    DIRECTION OUTPUT ;
    USE SIGNAL ;
    PORT
      LAYER M4 ;
        RECT  43.116 48.528 43.2 48.552 ;
    END
  END o[162]
  PIN o[163]
    DIRECTION OUTPUT ;
    USE SIGNAL ;
    PORT
      LAYER M4 ;
        RECT  43.116 48.624 43.2 48.648 ;
    END
  END o[163]
  PIN o[164]
    DIRECTION OUTPUT ;
    USE SIGNAL ;
    PORT
      LAYER M4 ;
        RECT  43.116 48.72 43.2 48.744 ;
    END
  END o[164]
  PIN o[165]
    DIRECTION OUTPUT ;
    USE SIGNAL ;
    PORT
      LAYER M4 ;
        RECT  43.116 48.816 43.2 48.84 ;
    END
  END o[165]
  PIN o[166]
    DIRECTION OUTPUT ;
    USE SIGNAL ;
    PORT
      LAYER M4 ;
        RECT  43.116 48.912 43.2 48.936 ;
    END
  END o[166]
  PIN o[167]
    DIRECTION OUTPUT ;
    USE SIGNAL ;
    PORT
      LAYER M4 ;
        RECT  43.116 49.008 43.2 49.032 ;
    END
  END o[167]
  PIN o[168]
    DIRECTION OUTPUT ;
    USE SIGNAL ;
    PORT
      LAYER M4 ;
        RECT  43.116 49.104 43.2 49.128 ;
    END
  END o[168]
  PIN o[169]
    DIRECTION OUTPUT ;
    USE SIGNAL ;
    PORT
      LAYER M4 ;
        RECT  43.116 49.2 43.2 49.224 ;
    END
  END o[169]
  PIN o[16]
    DIRECTION OUTPUT ;
    USE SIGNAL ;
    PORT
      LAYER M4 ;
        RECT  43.116 46.8 43.2 46.824 ;
    END
  END o[16]
  PIN o[170]
    DIRECTION OUTPUT ;
    USE SIGNAL ;
    PORT
      LAYER M4 ;
        RECT  43.116 49.296 43.2 49.32 ;
    END
  END o[170]
  PIN o[171]
    DIRECTION OUTPUT ;
    USE SIGNAL ;
    PORT
      LAYER M4 ;
        RECT  43.116 49.392 43.2 49.416 ;
    END
  END o[171]
  PIN o[172]
    DIRECTION OUTPUT ;
    USE SIGNAL ;
    PORT
      LAYER M4 ;
        RECT  43.116 49.488 43.2 49.512 ;
    END
  END o[172]
  PIN o[173]
    DIRECTION OUTPUT ;
    USE SIGNAL ;
    PORT
      LAYER M4 ;
        RECT  43.116 49.584 43.2 49.608 ;
    END
  END o[173]
  PIN o[174]
    DIRECTION OUTPUT ;
    USE SIGNAL ;
    PORT
      LAYER M4 ;
        RECT  43.116 49.68 43.2 49.704 ;
    END
  END o[174]
  PIN o[175]
    DIRECTION OUTPUT ;
    USE SIGNAL ;
    PORT
      LAYER M4 ;
        RECT  43.116 49.776 43.2 49.8 ;
    END
  END o[175]
  PIN o[176]
    DIRECTION OUTPUT ;
    USE SIGNAL ;
    PORT
      LAYER M4 ;
        RECT  43.116 49.872 43.2 49.896 ;
    END
  END o[176]
  PIN o[177]
    DIRECTION OUTPUT ;
    USE SIGNAL ;
    PORT
      LAYER M4 ;
        RECT  43.116 49.968 43.2 49.992 ;
    END
  END o[177]
  PIN o[178]
    DIRECTION OUTPUT ;
    USE SIGNAL ;
    PORT
      LAYER M4 ;
        RECT  43.116 50.064 43.2 50.088 ;
    END
  END o[178]
  PIN o[179]
    DIRECTION OUTPUT ;
    USE SIGNAL ;
    PORT
      LAYER M4 ;
        RECT  43.116 50.16 43.2 50.184 ;
    END
  END o[179]
  PIN o[17]
    DIRECTION OUTPUT ;
    USE SIGNAL ;
    PORT
      LAYER M4 ;
        RECT  43.116 46.896 43.2 46.92 ;
    END
  END o[17]
  PIN o[180]
    DIRECTION OUTPUT ;
    USE SIGNAL ;
    PORT
      LAYER M4 ;
        RECT  43.116 50.256 43.2 50.28 ;
    END
  END o[180]
  PIN o[181]
    DIRECTION OUTPUT ;
    USE SIGNAL ;
    PORT
      LAYER M4 ;
        RECT  43.116 50.352 43.2 50.376 ;
    END
  END o[181]
  PIN o[182]
    DIRECTION OUTPUT ;
    USE SIGNAL ;
    PORT
      LAYER M4 ;
        RECT  43.116 50.448 43.2 50.472 ;
    END
  END o[182]
  PIN o[183]
    DIRECTION OUTPUT ;
    USE SIGNAL ;
    PORT
      LAYER M4 ;
        RECT  43.116 50.544 43.2 50.568 ;
    END
  END o[183]
  PIN o[184]
    DIRECTION OUTPUT ;
    USE SIGNAL ;
    PORT
      LAYER M4 ;
        RECT  43.116 50.64 43.2 50.664 ;
    END
  END o[184]
  PIN o[185]
    DIRECTION OUTPUT ;
    USE SIGNAL ;
    PORT
      LAYER M4 ;
        RECT  43.116 50.736 43.2 50.76 ;
    END
  END o[185]
  PIN o[186]
    DIRECTION OUTPUT ;
    USE SIGNAL ;
    PORT
      LAYER M4 ;
        RECT  43.116 50.832 43.2 50.856 ;
    END
  END o[186]
  PIN o[187]
    DIRECTION OUTPUT ;
    USE SIGNAL ;
    PORT
      LAYER M4 ;
        RECT  43.116 50.928 43.2 50.952 ;
    END
  END o[187]
  PIN o[188]
    DIRECTION OUTPUT ;
    USE SIGNAL ;
    PORT
      LAYER M4 ;
        RECT  43.116 51.024 43.2 51.048 ;
    END
  END o[188]
  PIN o[189]
    DIRECTION OUTPUT ;
    USE SIGNAL ;
    PORT
      LAYER M4 ;
        RECT  43.116 51.12 43.2 51.144 ;
    END
  END o[189]
  PIN o[18]
    DIRECTION OUTPUT ;
    USE SIGNAL ;
    PORT
      LAYER M4 ;
        RECT  43.116 46.992 43.2 47.016 ;
    END
  END o[18]
  PIN o[190]
    DIRECTION OUTPUT ;
    USE SIGNAL ;
    PORT
      LAYER M4 ;
        RECT  43.116 51.216 43.2 51.24 ;
    END
  END o[190]
  PIN o[191]
    DIRECTION OUTPUT ;
    USE SIGNAL ;
    PORT
      LAYER M4 ;
        RECT  43.116 51.312 43.2 51.336 ;
    END
  END o[191]
  PIN o[192]
    DIRECTION OUTPUT ;
    USE SIGNAL ;
    PORT
      LAYER M4 ;
        RECT  43.116 61.392 43.2 61.416 ;
    END
  END o[192]
  PIN o[193]
    DIRECTION OUTPUT ;
    USE SIGNAL ;
    PORT
      LAYER M4 ;
        RECT  43.116 61.488 43.2 61.512 ;
    END
  END o[193]
  PIN o[194]
    DIRECTION OUTPUT ;
    USE SIGNAL ;
    PORT
      LAYER M4 ;
        RECT  43.116 61.584 43.2 61.608 ;
    END
  END o[194]
  PIN o[195]
    DIRECTION OUTPUT ;
    USE SIGNAL ;
    PORT
      LAYER M4 ;
        RECT  43.116 61.68 43.2 61.704 ;
    END
  END o[195]
  PIN o[196]
    DIRECTION OUTPUT ;
    USE SIGNAL ;
    PORT
      LAYER M4 ;
        RECT  43.116 61.776 43.2 61.8 ;
    END
  END o[196]
  PIN o[197]
    DIRECTION OUTPUT ;
    USE SIGNAL ;
    PORT
      LAYER M4 ;
        RECT  43.116 61.872 43.2 61.896 ;
    END
  END o[197]
  PIN o[198]
    DIRECTION OUTPUT ;
    USE SIGNAL ;
    PORT
      LAYER M4 ;
        RECT  43.116 61.968 43.2 61.992 ;
    END
  END o[198]
  PIN o[199]
    DIRECTION OUTPUT ;
    USE SIGNAL ;
    PORT
      LAYER M4 ;
        RECT  43.116 62.064 43.2 62.088 ;
    END
  END o[199]
  PIN o[19]
    DIRECTION OUTPUT ;
    USE SIGNAL ;
    PORT
      LAYER M4 ;
        RECT  43.116 47.088 43.2 47.112 ;
    END
  END o[19]
  PIN o[1]
    DIRECTION OUTPUT ;
    USE SIGNAL ;
    PORT
      LAYER M4 ;
        RECT  43.116 45.36 43.2 45.384 ;
    END
  END o[1]
  PIN o[200]
    DIRECTION OUTPUT ;
    USE SIGNAL ;
    PORT
      LAYER M4 ;
        RECT  43.116 62.16 43.2 62.184 ;
    END
  END o[200]
  PIN o[201]
    DIRECTION OUTPUT ;
    USE SIGNAL ;
    PORT
      LAYER M4 ;
        RECT  43.116 62.256 43.2 62.28 ;
    END
  END o[201]
  PIN o[202]
    DIRECTION OUTPUT ;
    USE SIGNAL ;
    PORT
      LAYER M4 ;
        RECT  43.116 62.352 43.2 62.376 ;
    END
  END o[202]
  PIN o[203]
    DIRECTION OUTPUT ;
    USE SIGNAL ;
    PORT
      LAYER M4 ;
        RECT  43.116 62.448 43.2 62.472 ;
    END
  END o[203]
  PIN o[204]
    DIRECTION OUTPUT ;
    USE SIGNAL ;
    PORT
      LAYER M4 ;
        RECT  43.116 62.544 43.2 62.568 ;
    END
  END o[204]
  PIN o[205]
    DIRECTION OUTPUT ;
    USE SIGNAL ;
    PORT
      LAYER M4 ;
        RECT  43.116 62.64 43.2 62.664 ;
    END
  END o[205]
  PIN o[206]
    DIRECTION OUTPUT ;
    USE SIGNAL ;
    PORT
      LAYER M4 ;
        RECT  43.116 62.736 43.2 62.76 ;
    END
  END o[206]
  PIN o[207]
    DIRECTION OUTPUT ;
    USE SIGNAL ;
    PORT
      LAYER M4 ;
        RECT  43.116 62.832 43.2 62.856 ;
    END
  END o[207]
  PIN o[208]
    DIRECTION OUTPUT ;
    USE SIGNAL ;
    PORT
      LAYER M4 ;
        RECT  43.116 62.928 43.2 62.952 ;
    END
  END o[208]
  PIN o[209]
    DIRECTION OUTPUT ;
    USE SIGNAL ;
    PORT
      LAYER M4 ;
        RECT  43.116 63.024 43.2 63.048 ;
    END
  END o[209]
  PIN o[20]
    DIRECTION OUTPUT ;
    USE SIGNAL ;
    PORT
      LAYER M4 ;
        RECT  43.116 47.184 43.2 47.208 ;
    END
  END o[20]
  PIN o[210]
    DIRECTION OUTPUT ;
    USE SIGNAL ;
    PORT
      LAYER M4 ;
        RECT  43.116 63.12 43.2 63.144 ;
    END
  END o[210]
  PIN o[211]
    DIRECTION OUTPUT ;
    USE SIGNAL ;
    PORT
      LAYER M4 ;
        RECT  43.116 63.216 43.2 63.24 ;
    END
  END o[211]
  PIN o[212]
    DIRECTION OUTPUT ;
    USE SIGNAL ;
    PORT
      LAYER M4 ;
        RECT  43.116 63.312 43.2 63.336 ;
    END
  END o[212]
  PIN o[213]
    DIRECTION OUTPUT ;
    USE SIGNAL ;
    PORT
      LAYER M4 ;
        RECT  43.116 63.408 43.2 63.432 ;
    END
  END o[213]
  PIN o[214]
    DIRECTION OUTPUT ;
    USE SIGNAL ;
    PORT
      LAYER M4 ;
        RECT  43.116 63.504 43.2 63.528 ;
    END
  END o[214]
  PIN o[215]
    DIRECTION OUTPUT ;
    USE SIGNAL ;
    PORT
      LAYER M4 ;
        RECT  43.116 63.6 43.2 63.624 ;
    END
  END o[215]
  PIN o[216]
    DIRECTION OUTPUT ;
    USE SIGNAL ;
    PORT
      LAYER M4 ;
        RECT  43.116 63.696 43.2 63.72 ;
    END
  END o[216]
  PIN o[217]
    DIRECTION OUTPUT ;
    USE SIGNAL ;
    PORT
      LAYER M4 ;
        RECT  43.116 63.792 43.2 63.816 ;
    END
  END o[217]
  PIN o[218]
    DIRECTION OUTPUT ;
    USE SIGNAL ;
    PORT
      LAYER M4 ;
        RECT  43.116 63.888 43.2 63.912 ;
    END
  END o[218]
  PIN o[219]
    DIRECTION OUTPUT ;
    USE SIGNAL ;
    PORT
      LAYER M4 ;
        RECT  43.116 63.984 43.2 64.008 ;
    END
  END o[219]
  PIN o[21]
    DIRECTION OUTPUT ;
    USE SIGNAL ;
    PORT
      LAYER M4 ;
        RECT  43.116 47.28 43.2 47.304 ;
    END
  END o[21]
  PIN o[220]
    DIRECTION OUTPUT ;
    USE SIGNAL ;
    PORT
      LAYER M4 ;
        RECT  43.116 64.08 43.2 64.104 ;
    END
  END o[220]
  PIN o[221]
    DIRECTION OUTPUT ;
    USE SIGNAL ;
    PORT
      LAYER M4 ;
        RECT  43.116 64.176 43.2 64.2 ;
    END
  END o[221]
  PIN o[222]
    DIRECTION OUTPUT ;
    USE SIGNAL ;
    PORT
      LAYER M4 ;
        RECT  43.116 64.272 43.2 64.296 ;
    END
  END o[222]
  PIN o[223]
    DIRECTION OUTPUT ;
    USE SIGNAL ;
    PORT
      LAYER M4 ;
        RECT  43.116 64.368 43.2 64.392 ;
    END
  END o[223]
  PIN o[224]
    DIRECTION OUTPUT ;
    USE SIGNAL ;
    PORT
      LAYER M4 ;
        RECT  43.116 58.32 43.2 58.344 ;
    END
  END o[224]
  PIN o[225]
    DIRECTION OUTPUT ;
    USE SIGNAL ;
    PORT
      LAYER M4 ;
        RECT  43.116 58.416 43.2 58.44 ;
    END
  END o[225]
  PIN o[226]
    DIRECTION OUTPUT ;
    USE SIGNAL ;
    PORT
      LAYER M4 ;
        RECT  43.116 58.512 43.2 58.536 ;
    END
  END o[226]
  PIN o[227]
    DIRECTION OUTPUT ;
    USE SIGNAL ;
    PORT
      LAYER M4 ;
        RECT  43.116 58.608 43.2 58.632 ;
    END
  END o[227]
  PIN o[228]
    DIRECTION OUTPUT ;
    USE SIGNAL ;
    PORT
      LAYER M4 ;
        RECT  43.116 58.704 43.2 58.728 ;
    END
  END o[228]
  PIN o[229]
    DIRECTION OUTPUT ;
    USE SIGNAL ;
    PORT
      LAYER M4 ;
        RECT  43.116 58.8 43.2 58.824 ;
    END
  END o[229]
  PIN o[22]
    DIRECTION OUTPUT ;
    USE SIGNAL ;
    PORT
      LAYER M4 ;
        RECT  43.116 47.376 43.2 47.4 ;
    END
  END o[22]
  PIN o[230]
    DIRECTION OUTPUT ;
    USE SIGNAL ;
    PORT
      LAYER M4 ;
        RECT  43.116 58.896 43.2 58.92 ;
    END
  END o[230]
  PIN o[231]
    DIRECTION OUTPUT ;
    USE SIGNAL ;
    PORT
      LAYER M4 ;
        RECT  43.116 58.992 43.2 59.016 ;
    END
  END o[231]
  PIN o[232]
    DIRECTION OUTPUT ;
    USE SIGNAL ;
    PORT
      LAYER M4 ;
        RECT  43.116 59.088 43.2 59.112 ;
    END
  END o[232]
  PIN o[233]
    DIRECTION OUTPUT ;
    USE SIGNAL ;
    PORT
      LAYER M4 ;
        RECT  43.116 59.184 43.2 59.208 ;
    END
  END o[233]
  PIN o[234]
    DIRECTION OUTPUT ;
    USE SIGNAL ;
    PORT
      LAYER M4 ;
        RECT  43.116 59.28 43.2 59.304 ;
    END
  END o[234]
  PIN o[235]
    DIRECTION OUTPUT ;
    USE SIGNAL ;
    PORT
      LAYER M4 ;
        RECT  43.116 59.376 43.2 59.4 ;
    END
  END o[235]
  PIN o[236]
    DIRECTION OUTPUT ;
    USE SIGNAL ;
    PORT
      LAYER M4 ;
        RECT  43.116 59.472 43.2 59.496 ;
    END
  END o[236]
  PIN o[237]
    DIRECTION OUTPUT ;
    USE SIGNAL ;
    PORT
      LAYER M4 ;
        RECT  43.116 59.568 43.2 59.592 ;
    END
  END o[237]
  PIN o[238]
    DIRECTION OUTPUT ;
    USE SIGNAL ;
    PORT
      LAYER M4 ;
        RECT  43.116 59.664 43.2 59.688 ;
    END
  END o[238]
  PIN o[239]
    DIRECTION OUTPUT ;
    USE SIGNAL ;
    PORT
      LAYER M4 ;
        RECT  43.116 59.76 43.2 59.784 ;
    END
  END o[239]
  PIN o[23]
    DIRECTION OUTPUT ;
    USE SIGNAL ;
    PORT
      LAYER M4 ;
        RECT  43.116 47.472 43.2 47.496 ;
    END
  END o[23]
  PIN o[240]
    DIRECTION OUTPUT ;
    USE SIGNAL ;
    PORT
      LAYER M4 ;
        RECT  43.116 59.856 43.2 59.88 ;
    END
  END o[240]
  PIN o[241]
    DIRECTION OUTPUT ;
    USE SIGNAL ;
    PORT
      LAYER M4 ;
        RECT  43.116 59.952 43.2 59.976 ;
    END
  END o[241]
  PIN o[242]
    DIRECTION OUTPUT ;
    USE SIGNAL ;
    PORT
      LAYER M4 ;
        RECT  43.116 60.048 43.2 60.072 ;
    END
  END o[242]
  PIN o[243]
    DIRECTION OUTPUT ;
    USE SIGNAL ;
    PORT
      LAYER M4 ;
        RECT  43.116 60.144 43.2 60.168 ;
    END
  END o[243]
  PIN o[244]
    DIRECTION OUTPUT ;
    USE SIGNAL ;
    PORT
      LAYER M4 ;
        RECT  43.116 60.24 43.2 60.264 ;
    END
  END o[244]
  PIN o[245]
    DIRECTION OUTPUT ;
    USE SIGNAL ;
    PORT
      LAYER M4 ;
        RECT  43.116 60.336 43.2 60.36 ;
    END
  END o[245]
  PIN o[246]
    DIRECTION OUTPUT ;
    USE SIGNAL ;
    PORT
      LAYER M4 ;
        RECT  43.116 60.432 43.2 60.456 ;
    END
  END o[246]
  PIN o[247]
    DIRECTION OUTPUT ;
    USE SIGNAL ;
    PORT
      LAYER M4 ;
        RECT  43.116 60.528 43.2 60.552 ;
    END
  END o[247]
  PIN o[248]
    DIRECTION OUTPUT ;
    USE SIGNAL ;
    PORT
      LAYER M4 ;
        RECT  43.116 60.624 43.2 60.648 ;
    END
  END o[248]
  PIN o[249]
    DIRECTION OUTPUT ;
    USE SIGNAL ;
    PORT
      LAYER M4 ;
        RECT  43.116 60.72 43.2 60.744 ;
    END
  END o[249]
  PIN o[24]
    DIRECTION OUTPUT ;
    USE SIGNAL ;
    PORT
      LAYER M4 ;
        RECT  43.116 47.568 43.2 47.592 ;
    END
  END o[24]
  PIN o[250]
    DIRECTION OUTPUT ;
    USE SIGNAL ;
    PORT
      LAYER M4 ;
        RECT  43.116 60.816 43.2 60.84 ;
    END
  END o[250]
  PIN o[251]
    DIRECTION OUTPUT ;
    USE SIGNAL ;
    PORT
      LAYER M4 ;
        RECT  43.116 60.912 43.2 60.936 ;
    END
  END o[251]
  PIN o[252]
    DIRECTION OUTPUT ;
    USE SIGNAL ;
    PORT
      LAYER M4 ;
        RECT  43.116 61.008 43.2 61.032 ;
    END
  END o[252]
  PIN o[253]
    DIRECTION OUTPUT ;
    USE SIGNAL ;
    PORT
      LAYER M4 ;
        RECT  43.116 61.104 43.2 61.128 ;
    END
  END o[253]
  PIN o[254]
    DIRECTION OUTPUT ;
    USE SIGNAL ;
    PORT
      LAYER M4 ;
        RECT  43.116 61.2 43.2 61.224 ;
    END
  END o[254]
  PIN o[255]
    DIRECTION OUTPUT ;
    USE SIGNAL ;
    PORT
      LAYER M4 ;
        RECT  43.116 61.296 43.2 61.32 ;
    END
  END o[255]
  PIN o[256]
    DIRECTION OUTPUT ;
    USE SIGNAL ;
    PORT
      LAYER M4 ;
        RECT  43.116 67.536 43.2 67.56 ;
    END
  END o[256]
  PIN o[257]
    DIRECTION OUTPUT ;
    USE SIGNAL ;
    PORT
      LAYER M4 ;
        RECT  43.116 67.632 43.2 67.656 ;
    END
  END o[257]
  PIN o[258]
    DIRECTION OUTPUT ;
    USE SIGNAL ;
    PORT
      LAYER M4 ;
        RECT  43.116 67.728 43.2 67.752 ;
    END
  END o[258]
  PIN o[259]
    DIRECTION OUTPUT ;
    USE SIGNAL ;
    PORT
      LAYER M4 ;
        RECT  43.116 67.824 43.2 67.848 ;
    END
  END o[259]
  PIN o[25]
    DIRECTION OUTPUT ;
    USE SIGNAL ;
    PORT
      LAYER M4 ;
        RECT  43.116 47.664 43.2 47.688 ;
    END
  END o[25]
  PIN o[260]
    DIRECTION OUTPUT ;
    USE SIGNAL ;
    PORT
      LAYER M4 ;
        RECT  43.116 67.92 43.2 67.944 ;
    END
  END o[260]
  PIN o[261]
    DIRECTION OUTPUT ;
    USE SIGNAL ;
    PORT
      LAYER M4 ;
        RECT  43.116 68.016 43.2 68.04 ;
    END
  END o[261]
  PIN o[262]
    DIRECTION OUTPUT ;
    USE SIGNAL ;
    PORT
      LAYER M4 ;
        RECT  43.116 68.112 43.2 68.136 ;
    END
  END o[262]
  PIN o[263]
    DIRECTION OUTPUT ;
    USE SIGNAL ;
    PORT
      LAYER M4 ;
        RECT  43.116 68.208 43.2 68.232 ;
    END
  END o[263]
  PIN o[264]
    DIRECTION OUTPUT ;
    USE SIGNAL ;
    PORT
      LAYER M4 ;
        RECT  43.116 68.304 43.2 68.328 ;
    END
  END o[264]
  PIN o[265]
    DIRECTION OUTPUT ;
    USE SIGNAL ;
    PORT
      LAYER M4 ;
        RECT  43.116 68.4 43.2 68.424 ;
    END
  END o[265]
  PIN o[266]
    DIRECTION OUTPUT ;
    USE SIGNAL ;
    PORT
      LAYER M4 ;
        RECT  43.116 68.496 43.2 68.52 ;
    END
  END o[266]
  PIN o[267]
    DIRECTION OUTPUT ;
    USE SIGNAL ;
    PORT
      LAYER M4 ;
        RECT  43.116 68.592 43.2 68.616 ;
    END
  END o[267]
  PIN o[268]
    DIRECTION OUTPUT ;
    USE SIGNAL ;
    PORT
      LAYER M4 ;
        RECT  43.116 68.688 43.2 68.712 ;
    END
  END o[268]
  PIN o[269]
    DIRECTION OUTPUT ;
    USE SIGNAL ;
    PORT
      LAYER M4 ;
        RECT  43.116 68.784 43.2 68.808 ;
    END
  END o[269]
  PIN o[26]
    DIRECTION OUTPUT ;
    USE SIGNAL ;
    PORT
      LAYER M4 ;
        RECT  43.116 47.76 43.2 47.784 ;
    END
  END o[26]
  PIN o[270]
    DIRECTION OUTPUT ;
    USE SIGNAL ;
    PORT
      LAYER M4 ;
        RECT  43.116 68.88 43.2 68.904 ;
    END
  END o[270]
  PIN o[271]
    DIRECTION OUTPUT ;
    USE SIGNAL ;
    PORT
      LAYER M4 ;
        RECT  43.116 68.976 43.2 69 ;
    END
  END o[271]
  PIN o[272]
    DIRECTION OUTPUT ;
    USE SIGNAL ;
    PORT
      LAYER M4 ;
        RECT  43.116 69.072 43.2 69.096 ;
    END
  END o[272]
  PIN o[273]
    DIRECTION OUTPUT ;
    USE SIGNAL ;
    PORT
      LAYER M4 ;
        RECT  43.116 69.168 43.2 69.192 ;
    END
  END o[273]
  PIN o[274]
    DIRECTION OUTPUT ;
    USE SIGNAL ;
    PORT
      LAYER M4 ;
        RECT  43.116 69.264 43.2 69.288 ;
    END
  END o[274]
  PIN o[275]
    DIRECTION OUTPUT ;
    USE SIGNAL ;
    PORT
      LAYER M4 ;
        RECT  43.116 69.36 43.2 69.384 ;
    END
  END o[275]
  PIN o[276]
    DIRECTION OUTPUT ;
    USE SIGNAL ;
    PORT
      LAYER M4 ;
        RECT  43.116 69.456 43.2 69.48 ;
    END
  END o[276]
  PIN o[277]
    DIRECTION OUTPUT ;
    USE SIGNAL ;
    PORT
      LAYER M4 ;
        RECT  43.116 69.552 43.2 69.576 ;
    END
  END o[277]
  PIN o[278]
    DIRECTION OUTPUT ;
    USE SIGNAL ;
    PORT
      LAYER M4 ;
        RECT  43.116 69.648 43.2 69.672 ;
    END
  END o[278]
  PIN o[279]
    DIRECTION OUTPUT ;
    USE SIGNAL ;
    PORT
      LAYER M4 ;
        RECT  43.116 69.744 43.2 69.768 ;
    END
  END o[279]
  PIN o[27]
    DIRECTION OUTPUT ;
    USE SIGNAL ;
    PORT
      LAYER M4 ;
        RECT  43.116 47.856 43.2 47.88 ;
    END
  END o[27]
  PIN o[280]
    DIRECTION OUTPUT ;
    USE SIGNAL ;
    PORT
      LAYER M4 ;
        RECT  43.116 69.84 43.2 69.864 ;
    END
  END o[280]
  PIN o[281]
    DIRECTION OUTPUT ;
    USE SIGNAL ;
    PORT
      LAYER M4 ;
        RECT  43.116 69.936 43.2 69.96 ;
    END
  END o[281]
  PIN o[282]
    DIRECTION OUTPUT ;
    USE SIGNAL ;
    PORT
      LAYER M4 ;
        RECT  43.116 70.032 43.2 70.056 ;
    END
  END o[282]
  PIN o[283]
    DIRECTION OUTPUT ;
    USE SIGNAL ;
    PORT
      LAYER M4 ;
        RECT  43.116 70.128 43.2 70.152 ;
    END
  END o[283]
  PIN o[284]
    DIRECTION OUTPUT ;
    USE SIGNAL ;
    PORT
      LAYER M4 ;
        RECT  43.116 70.224 43.2 70.248 ;
    END
  END o[284]
  PIN o[285]
    DIRECTION OUTPUT ;
    USE SIGNAL ;
    PORT
      LAYER M4 ;
        RECT  43.116 70.32 43.2 70.344 ;
    END
  END o[285]
  PIN o[286]
    DIRECTION OUTPUT ;
    USE SIGNAL ;
    PORT
      LAYER M4 ;
        RECT  43.116 70.416 43.2 70.44 ;
    END
  END o[286]
  PIN o[287]
    DIRECTION OUTPUT ;
    USE SIGNAL ;
    PORT
      LAYER M4 ;
        RECT  43.116 70.512 43.2 70.536 ;
    END
  END o[287]
  PIN o[288]
    DIRECTION OUTPUT ;
    USE SIGNAL ;
    PORT
      LAYER M4 ;
        RECT  43.116 70.608 43.2 70.632 ;
    END
  END o[288]
  PIN o[289]
    DIRECTION OUTPUT ;
    USE SIGNAL ;
    PORT
      LAYER M4 ;
        RECT  43.116 70.704 43.2 70.728 ;
    END
  END o[289]
  PIN o[28]
    DIRECTION OUTPUT ;
    USE SIGNAL ;
    PORT
      LAYER M4 ;
        RECT  43.116 47.952 43.2 47.976 ;
    END
  END o[28]
  PIN o[290]
    DIRECTION OUTPUT ;
    USE SIGNAL ;
    PORT
      LAYER M4 ;
        RECT  43.116 70.8 43.2 70.824 ;
    END
  END o[290]
  PIN o[291]
    DIRECTION OUTPUT ;
    USE SIGNAL ;
    PORT
      LAYER M4 ;
        RECT  43.116 70.896 43.2 70.92 ;
    END
  END o[291]
  PIN o[292]
    DIRECTION OUTPUT ;
    USE SIGNAL ;
    PORT
      LAYER M4 ;
        RECT  43.116 70.992 43.2 71.016 ;
    END
  END o[292]
  PIN o[293]
    DIRECTION OUTPUT ;
    USE SIGNAL ;
    PORT
      LAYER M4 ;
        RECT  43.116 71.088 43.2 71.112 ;
    END
  END o[293]
  PIN o[294]
    DIRECTION OUTPUT ;
    USE SIGNAL ;
    PORT
      LAYER M4 ;
        RECT  43.116 71.184 43.2 71.208 ;
    END
  END o[294]
  PIN o[295]
    DIRECTION OUTPUT ;
    USE SIGNAL ;
    PORT
      LAYER M4 ;
        RECT  43.116 71.28 43.2 71.304 ;
    END
  END o[295]
  PIN o[296]
    DIRECTION OUTPUT ;
    USE SIGNAL ;
    PORT
      LAYER M4 ;
        RECT  43.116 71.376 43.2 71.4 ;
    END
  END o[296]
  PIN o[297]
    DIRECTION OUTPUT ;
    USE SIGNAL ;
    PORT
      LAYER M4 ;
        RECT  43.116 71.472 43.2 71.496 ;
    END
  END o[297]
  PIN o[298]
    DIRECTION OUTPUT ;
    USE SIGNAL ;
    PORT
      LAYER M4 ;
        RECT  43.116 71.568 43.2 71.592 ;
    END
  END o[298]
  PIN o[299]
    DIRECTION OUTPUT ;
    USE SIGNAL ;
    PORT
      LAYER M4 ;
        RECT  43.116 71.664 43.2 71.688 ;
    END
  END o[299]
  PIN o[29]
    DIRECTION OUTPUT ;
    USE SIGNAL ;
    PORT
      LAYER M4 ;
        RECT  43.116 48.048 43.2 48.072 ;
    END
  END o[29]
  PIN o[2]
    DIRECTION OUTPUT ;
    USE SIGNAL ;
    PORT
      LAYER M4 ;
        RECT  43.116 45.456 43.2 45.48 ;
    END
  END o[2]
  PIN o[300]
    DIRECTION OUTPUT ;
    USE SIGNAL ;
    PORT
      LAYER M4 ;
        RECT  43.116 71.76 43.2 71.784 ;
    END
  END o[300]
  PIN o[301]
    DIRECTION OUTPUT ;
    USE SIGNAL ;
    PORT
      LAYER M4 ;
        RECT  43.116 71.856 43.2 71.88 ;
    END
  END o[301]
  PIN o[302]
    DIRECTION OUTPUT ;
    USE SIGNAL ;
    PORT
      LAYER M4 ;
        RECT  43.116 71.952 43.2 71.976 ;
    END
  END o[302]
  PIN o[303]
    DIRECTION OUTPUT ;
    USE SIGNAL ;
    PORT
      LAYER M4 ;
        RECT  43.116 72.048 43.2 72.072 ;
    END
  END o[303]
  PIN o[304]
    DIRECTION OUTPUT ;
    USE SIGNAL ;
    PORT
      LAYER M4 ;
        RECT  43.116 72.144 43.2 72.168 ;
    END
  END o[304]
  PIN o[305]
    DIRECTION OUTPUT ;
    USE SIGNAL ;
    PORT
      LAYER M4 ;
        RECT  43.116 72.24 43.2 72.264 ;
    END
  END o[305]
  PIN o[306]
    DIRECTION OUTPUT ;
    USE SIGNAL ;
    PORT
      LAYER M4 ;
        RECT  43.116 72.336 43.2 72.36 ;
    END
  END o[306]
  PIN o[307]
    DIRECTION OUTPUT ;
    USE SIGNAL ;
    PORT
      LAYER M4 ;
        RECT  43.116 72.432 43.2 72.456 ;
    END
  END o[307]
  PIN o[308]
    DIRECTION OUTPUT ;
    USE SIGNAL ;
    PORT
      LAYER M4 ;
        RECT  43.116 72.528 43.2 72.552 ;
    END
  END o[308]
  PIN o[309]
    DIRECTION OUTPUT ;
    USE SIGNAL ;
    PORT
      LAYER M4 ;
        RECT  43.116 72.624 43.2 72.648 ;
    END
  END o[309]
  PIN o[30]
    DIRECTION OUTPUT ;
    USE SIGNAL ;
    PORT
      LAYER M4 ;
        RECT  43.116 48.144 43.2 48.168 ;
    END
  END o[30]
  PIN o[310]
    DIRECTION OUTPUT ;
    USE SIGNAL ;
    PORT
      LAYER M4 ;
        RECT  43.116 72.72 43.2 72.744 ;
    END
  END o[310]
  PIN o[311]
    DIRECTION OUTPUT ;
    USE SIGNAL ;
    PORT
      LAYER M4 ;
        RECT  43.116 72.816 43.2 72.84 ;
    END
  END o[311]
  PIN o[312]
    DIRECTION OUTPUT ;
    USE SIGNAL ;
    PORT
      LAYER M4 ;
        RECT  43.116 72.912 43.2 72.936 ;
    END
  END o[312]
  PIN o[313]
    DIRECTION OUTPUT ;
    USE SIGNAL ;
    PORT
      LAYER M4 ;
        RECT  43.116 73.008 43.2 73.032 ;
    END
  END o[313]
  PIN o[314]
    DIRECTION OUTPUT ;
    USE SIGNAL ;
    PORT
      LAYER M4 ;
        RECT  43.116 73.104 43.2 73.128 ;
    END
  END o[314]
  PIN o[315]
    DIRECTION OUTPUT ;
    USE SIGNAL ;
    PORT
      LAYER M4 ;
        RECT  43.116 73.2 43.2 73.224 ;
    END
  END o[315]
  PIN o[316]
    DIRECTION OUTPUT ;
    USE SIGNAL ;
    PORT
      LAYER M4 ;
        RECT  43.116 73.296 43.2 73.32 ;
    END
  END o[316]
  PIN o[317]
    DIRECTION OUTPUT ;
    USE SIGNAL ;
    PORT
      LAYER M4 ;
        RECT  43.116 73.392 43.2 73.416 ;
    END
  END o[317]
  PIN o[318]
    DIRECTION OUTPUT ;
    USE SIGNAL ;
    PORT
      LAYER M4 ;
        RECT  43.116 73.488 43.2 73.512 ;
    END
  END o[318]
  PIN o[319]
    DIRECTION OUTPUT ;
    USE SIGNAL ;
    PORT
      LAYER M4 ;
        RECT  43.116 73.584 43.2 73.608 ;
    END
  END o[319]
  PIN o[31]
    DIRECTION OUTPUT ;
    USE SIGNAL ;
    PORT
      LAYER M4 ;
        RECT  43.116 48.24 43.2 48.264 ;
    END
  END o[31]
  PIN o[320]
    DIRECTION OUTPUT ;
    USE SIGNAL ;
    PORT
      LAYER M4 ;
        RECT  43.116 73.68 43.2 73.704 ;
    END
  END o[320]
  PIN o[321]
    DIRECTION OUTPUT ;
    USE SIGNAL ;
    PORT
      LAYER M4 ;
        RECT  43.116 73.776 43.2 73.8 ;
    END
  END o[321]
  PIN o[322]
    DIRECTION OUTPUT ;
    USE SIGNAL ;
    PORT
      LAYER M4 ;
        RECT  43.116 73.872 43.2 73.896 ;
    END
  END o[322]
  PIN o[323]
    DIRECTION OUTPUT ;
    USE SIGNAL ;
    PORT
      LAYER M4 ;
        RECT  43.116 73.968 43.2 73.992 ;
    END
  END o[323]
  PIN o[324]
    DIRECTION OUTPUT ;
    USE SIGNAL ;
    PORT
      LAYER M4 ;
        RECT  43.116 74.064 43.2 74.088 ;
    END
  END o[324]
  PIN o[325]
    DIRECTION OUTPUT ;
    USE SIGNAL ;
    PORT
      LAYER M4 ;
        RECT  43.116 74.16 43.2 74.184 ;
    END
  END o[325]
  PIN o[326]
    DIRECTION OUTPUT ;
    USE SIGNAL ;
    PORT
      LAYER M4 ;
        RECT  43.116 74.256 43.2 74.28 ;
    END
  END o[326]
  PIN o[327]
    DIRECTION OUTPUT ;
    USE SIGNAL ;
    PORT
      LAYER M4 ;
        RECT  43.116 74.352 43.2 74.376 ;
    END
  END o[327]
  PIN o[328]
    DIRECTION OUTPUT ;
    USE SIGNAL ;
    PORT
      LAYER M4 ;
        RECT  43.116 74.448 43.2 74.472 ;
    END
  END o[328]
  PIN o[329]
    DIRECTION OUTPUT ;
    USE SIGNAL ;
    PORT
      LAYER M4 ;
        RECT  43.116 74.544 43.2 74.568 ;
    END
  END o[329]
  PIN o[32]
    DIRECTION OUTPUT ;
    USE SIGNAL ;
    PORT
      LAYER M4 ;
        RECT  43.116 39.12 43.2 39.144 ;
    END
  END o[32]
  PIN o[330]
    DIRECTION OUTPUT ;
    USE SIGNAL ;
    PORT
      LAYER M4 ;
        RECT  43.116 74.64 43.2 74.664 ;
    END
  END o[330]
  PIN o[331]
    DIRECTION OUTPUT ;
    USE SIGNAL ;
    PORT
      LAYER M4 ;
        RECT  43.116 74.736 43.2 74.76 ;
    END
  END o[331]
  PIN o[332]
    DIRECTION OUTPUT ;
    USE SIGNAL ;
    PORT
      LAYER M4 ;
        RECT  43.116 74.832 43.2 74.856 ;
    END
  END o[332]
  PIN o[333]
    DIRECTION OUTPUT ;
    USE SIGNAL ;
    PORT
      LAYER M4 ;
        RECT  43.116 74.928 43.2 74.952 ;
    END
  END o[333]
  PIN o[334]
    DIRECTION OUTPUT ;
    USE SIGNAL ;
    PORT
      LAYER M4 ;
        RECT  43.116 75.024 43.2 75.048 ;
    END
  END o[334]
  PIN o[335]
    DIRECTION OUTPUT ;
    USE SIGNAL ;
    PORT
      LAYER M4 ;
        RECT  43.116 75.12 43.2 75.144 ;
    END
  END o[335]
  PIN o[336]
    DIRECTION OUTPUT ;
    USE SIGNAL ;
    PORT
      LAYER M4 ;
        RECT  43.116 75.216 43.2 75.24 ;
    END
  END o[336]
  PIN o[337]
    DIRECTION OUTPUT ;
    USE SIGNAL ;
    PORT
      LAYER M4 ;
        RECT  43.116 75.312 43.2 75.336 ;
    END
  END o[337]
  PIN o[338]
    DIRECTION OUTPUT ;
    USE SIGNAL ;
    PORT
      LAYER M4 ;
        RECT  43.116 75.408 43.2 75.432 ;
    END
  END o[338]
  PIN o[339]
    DIRECTION OUTPUT ;
    USE SIGNAL ;
    PORT
      LAYER M4 ;
        RECT  43.116 75.504 43.2 75.528 ;
    END
  END o[339]
  PIN o[33]
    DIRECTION OUTPUT ;
    USE SIGNAL ;
    PORT
      LAYER M4 ;
        RECT  43.116 39.216 43.2 39.24 ;
    END
  END o[33]
  PIN o[340]
    DIRECTION OUTPUT ;
    USE SIGNAL ;
    PORT
      LAYER M4 ;
        RECT  43.116 75.6 43.2 75.624 ;
    END
  END o[340]
  PIN o[341]
    DIRECTION OUTPUT ;
    USE SIGNAL ;
    PORT
      LAYER M4 ;
        RECT  43.116 75.696 43.2 75.72 ;
    END
  END o[341]
  PIN o[342]
    DIRECTION OUTPUT ;
    USE SIGNAL ;
    PORT
      LAYER M4 ;
        RECT  43.116 75.792 43.2 75.816 ;
    END
  END o[342]
  PIN o[343]
    DIRECTION OUTPUT ;
    USE SIGNAL ;
    PORT
      LAYER M4 ;
        RECT  43.116 75.888 43.2 75.912 ;
    END
  END o[343]
  PIN o[344]
    DIRECTION OUTPUT ;
    USE SIGNAL ;
    PORT
      LAYER M4 ;
        RECT  43.116 75.984 43.2 76.008 ;
    END
  END o[344]
  PIN o[345]
    DIRECTION OUTPUT ;
    USE SIGNAL ;
    PORT
      LAYER M4 ;
        RECT  43.116 76.08 43.2 76.104 ;
    END
  END o[345]
  PIN o[346]
    DIRECTION OUTPUT ;
    USE SIGNAL ;
    PORT
      LAYER M4 ;
        RECT  43.116 76.176 43.2 76.2 ;
    END
  END o[346]
  PIN o[347]
    DIRECTION OUTPUT ;
    USE SIGNAL ;
    PORT
      LAYER M4 ;
        RECT  43.116 76.272 43.2 76.296 ;
    END
  END o[347]
  PIN o[348]
    DIRECTION OUTPUT ;
    USE SIGNAL ;
    PORT
      LAYER M4 ;
        RECT  43.116 76.368 43.2 76.392 ;
    END
  END o[348]
  PIN o[349]
    DIRECTION OUTPUT ;
    USE SIGNAL ;
    PORT
      LAYER M4 ;
        RECT  43.116 76.464 43.2 76.488 ;
    END
  END o[349]
  PIN o[34]
    DIRECTION OUTPUT ;
    USE SIGNAL ;
    PORT
      LAYER M4 ;
        RECT  43.116 39.312 43.2 39.336 ;
    END
  END o[34]
  PIN o[350]
    DIRECTION OUTPUT ;
    USE SIGNAL ;
    PORT
      LAYER M4 ;
        RECT  43.116 76.56 43.2 76.584 ;
    END
  END o[350]
  PIN o[351]
    DIRECTION OUTPUT ;
    USE SIGNAL ;
    PORT
      LAYER M4 ;
        RECT  43.116 76.656 43.2 76.68 ;
    END
  END o[351]
  PIN o[352]
    DIRECTION OUTPUT ;
    USE SIGNAL ;
    PORT
      LAYER M4 ;
        RECT  43.116 64.464 43.2 64.488 ;
    END
  END o[352]
  PIN o[353]
    DIRECTION OUTPUT ;
    USE SIGNAL ;
    PORT
      LAYER M4 ;
        RECT  43.116 64.56 43.2 64.584 ;
    END
  END o[353]
  PIN o[354]
    DIRECTION OUTPUT ;
    USE SIGNAL ;
    PORT
      LAYER M4 ;
        RECT  43.116 64.656 43.2 64.68 ;
    END
  END o[354]
  PIN o[355]
    DIRECTION OUTPUT ;
    USE SIGNAL ;
    PORT
      LAYER M4 ;
        RECT  43.116 64.752 43.2 64.776 ;
    END
  END o[355]
  PIN o[356]
    DIRECTION OUTPUT ;
    USE SIGNAL ;
    PORT
      LAYER M4 ;
        RECT  43.116 64.848 43.2 64.872 ;
    END
  END o[356]
  PIN o[357]
    DIRECTION OUTPUT ;
    USE SIGNAL ;
    PORT
      LAYER M4 ;
        RECT  43.116 64.944 43.2 64.968 ;
    END
  END o[357]
  PIN o[358]
    DIRECTION OUTPUT ;
    USE SIGNAL ;
    PORT
      LAYER M4 ;
        RECT  43.116 65.04 43.2 65.064 ;
    END
  END o[358]
  PIN o[359]
    DIRECTION OUTPUT ;
    USE SIGNAL ;
    PORT
      LAYER M4 ;
        RECT  43.116 65.136 43.2 65.16 ;
    END
  END o[359]
  PIN o[35]
    DIRECTION OUTPUT ;
    USE SIGNAL ;
    PORT
      LAYER M4 ;
        RECT  43.116 39.408 43.2 39.432 ;
    END
  END o[35]
  PIN o[360]
    DIRECTION OUTPUT ;
    USE SIGNAL ;
    PORT
      LAYER M4 ;
        RECT  43.116 65.232 43.2 65.256 ;
    END
  END o[360]
  PIN o[361]
    DIRECTION OUTPUT ;
    USE SIGNAL ;
    PORT
      LAYER M4 ;
        RECT  43.116 65.328 43.2 65.352 ;
    END
  END o[361]
  PIN o[362]
    DIRECTION OUTPUT ;
    USE SIGNAL ;
    PORT
      LAYER M4 ;
        RECT  43.116 65.424 43.2 65.448 ;
    END
  END o[362]
  PIN o[363]
    DIRECTION OUTPUT ;
    USE SIGNAL ;
    PORT
      LAYER M4 ;
        RECT  43.116 65.52 43.2 65.544 ;
    END
  END o[363]
  PIN o[364]
    DIRECTION OUTPUT ;
    USE SIGNAL ;
    PORT
      LAYER M4 ;
        RECT  43.116 65.616 43.2 65.64 ;
    END
  END o[364]
  PIN o[365]
    DIRECTION OUTPUT ;
    USE SIGNAL ;
    PORT
      LAYER M4 ;
        RECT  43.116 65.712 43.2 65.736 ;
    END
  END o[365]
  PIN o[366]
    DIRECTION OUTPUT ;
    USE SIGNAL ;
    PORT
      LAYER M4 ;
        RECT  43.116 65.808 43.2 65.832 ;
    END
  END o[366]
  PIN o[367]
    DIRECTION OUTPUT ;
    USE SIGNAL ;
    PORT
      LAYER M4 ;
        RECT  43.116 65.904 43.2 65.928 ;
    END
  END o[367]
  PIN o[368]
    DIRECTION OUTPUT ;
    USE SIGNAL ;
    PORT
      LAYER M4 ;
        RECT  43.116 66 43.2 66.024 ;
    END
  END o[368]
  PIN o[369]
    DIRECTION OUTPUT ;
    USE SIGNAL ;
    PORT
      LAYER M4 ;
        RECT  43.116 66.096 43.2 66.12 ;
    END
  END o[369]
  PIN o[36]
    DIRECTION OUTPUT ;
    USE SIGNAL ;
    PORT
      LAYER M4 ;
        RECT  43.116 39.504 43.2 39.528 ;
    END
  END o[36]
  PIN o[370]
    DIRECTION OUTPUT ;
    USE SIGNAL ;
    PORT
      LAYER M4 ;
        RECT  43.116 66.192 43.2 66.216 ;
    END
  END o[370]
  PIN o[371]
    DIRECTION OUTPUT ;
    USE SIGNAL ;
    PORT
      LAYER M4 ;
        RECT  43.116 66.288 43.2 66.312 ;
    END
  END o[371]
  PIN o[372]
    DIRECTION OUTPUT ;
    USE SIGNAL ;
    PORT
      LAYER M4 ;
        RECT  43.116 66.384 43.2 66.408 ;
    END
  END o[372]
  PIN o[373]
    DIRECTION OUTPUT ;
    USE SIGNAL ;
    PORT
      LAYER M4 ;
        RECT  43.116 66.48 43.2 66.504 ;
    END
  END o[373]
  PIN o[374]
    DIRECTION OUTPUT ;
    USE SIGNAL ;
    PORT
      LAYER M4 ;
        RECT  43.116 66.576 43.2 66.6 ;
    END
  END o[374]
  PIN o[375]
    DIRECTION OUTPUT ;
    USE SIGNAL ;
    PORT
      LAYER M4 ;
        RECT  43.116 66.672 43.2 66.696 ;
    END
  END o[375]
  PIN o[376]
    DIRECTION OUTPUT ;
    USE SIGNAL ;
    PORT
      LAYER M4 ;
        RECT  43.116 66.768 43.2 66.792 ;
    END
  END o[376]
  PIN o[377]
    DIRECTION OUTPUT ;
    USE SIGNAL ;
    PORT
      LAYER M4 ;
        RECT  43.116 66.864 43.2 66.888 ;
    END
  END o[377]
  PIN o[378]
    DIRECTION OUTPUT ;
    USE SIGNAL ;
    PORT
      LAYER M4 ;
        RECT  43.116 66.96 43.2 66.984 ;
    END
  END o[378]
  PIN o[379]
    DIRECTION OUTPUT ;
    USE SIGNAL ;
    PORT
      LAYER M4 ;
        RECT  43.116 67.056 43.2 67.08 ;
    END
  END o[379]
  PIN o[37]
    DIRECTION OUTPUT ;
    USE SIGNAL ;
    PORT
      LAYER M4 ;
        RECT  43.116 39.6 43.2 39.624 ;
    END
  END o[37]
  PIN o[380]
    DIRECTION OUTPUT ;
    USE SIGNAL ;
    PORT
      LAYER M4 ;
        RECT  43.116 67.152 43.2 67.176 ;
    END
  END o[380]
  PIN o[381]
    DIRECTION OUTPUT ;
    USE SIGNAL ;
    PORT
      LAYER M4 ;
        RECT  43.116 67.248 43.2 67.272 ;
    END
  END o[381]
  PIN o[382]
    DIRECTION OUTPUT ;
    USE SIGNAL ;
    PORT
      LAYER M4 ;
        RECT  43.116 67.344 43.2 67.368 ;
    END
  END o[382]
  PIN o[383]
    DIRECTION OUTPUT ;
    USE SIGNAL ;
    PORT
      LAYER M4 ;
        RECT  43.116 67.44 43.2 67.464 ;
    END
  END o[383]
  PIN o[384]
    DIRECTION OUTPUT ;
    USE SIGNAL ;
    PORT
      LAYER M4 ;
        RECT  43.116 26.064 43.2 26.088 ;
    END
  END o[384]
  PIN o[385]
    DIRECTION OUTPUT ;
    USE SIGNAL ;
    PORT
      LAYER M4 ;
        RECT  43.116 26.16 43.2 26.184 ;
    END
  END o[385]
  PIN o[386]
    DIRECTION OUTPUT ;
    USE SIGNAL ;
    PORT
      LAYER M4 ;
        RECT  43.116 26.256 43.2 26.28 ;
    END
  END o[386]
  PIN o[387]
    DIRECTION OUTPUT ;
    USE SIGNAL ;
    PORT
      LAYER M4 ;
        RECT  43.116 26.352 43.2 26.376 ;
    END
  END o[387]
  PIN o[388]
    DIRECTION OUTPUT ;
    USE SIGNAL ;
    PORT
      LAYER M4 ;
        RECT  43.116 26.448 43.2 26.472 ;
    END
  END o[388]
  PIN o[389]
    DIRECTION OUTPUT ;
    USE SIGNAL ;
    PORT
      LAYER M4 ;
        RECT  43.116 26.544 43.2 26.568 ;
    END
  END o[389]
  PIN o[38]
    DIRECTION OUTPUT ;
    USE SIGNAL ;
    PORT
      LAYER M4 ;
        RECT  43.116 39.696 43.2 39.72 ;
    END
  END o[38]
  PIN o[390]
    DIRECTION OUTPUT ;
    USE SIGNAL ;
    PORT
      LAYER M4 ;
        RECT  43.116 26.64 43.2 26.664 ;
    END
  END o[390]
  PIN o[391]
    DIRECTION OUTPUT ;
    USE SIGNAL ;
    PORT
      LAYER M4 ;
        RECT  43.116 26.736 43.2 26.76 ;
    END
  END o[391]
  PIN o[392]
    DIRECTION OUTPUT ;
    USE SIGNAL ;
    PORT
      LAYER M4 ;
        RECT  43.116 26.832 43.2 26.856 ;
    END
  END o[392]
  PIN o[393]
    DIRECTION OUTPUT ;
    USE SIGNAL ;
    PORT
      LAYER M4 ;
        RECT  43.116 26.928 43.2 26.952 ;
    END
  END o[393]
  PIN o[394]
    DIRECTION OUTPUT ;
    USE SIGNAL ;
    PORT
      LAYER M4 ;
        RECT  43.116 27.024 43.2 27.048 ;
    END
  END o[394]
  PIN o[395]
    DIRECTION OUTPUT ;
    USE SIGNAL ;
    PORT
      LAYER M4 ;
        RECT  43.116 27.12 43.2 27.144 ;
    END
  END o[395]
  PIN o[396]
    DIRECTION OUTPUT ;
    USE SIGNAL ;
    PORT
      LAYER M4 ;
        RECT  43.116 27.216 43.2 27.24 ;
    END
  END o[396]
  PIN o[397]
    DIRECTION OUTPUT ;
    USE SIGNAL ;
    PORT
      LAYER M4 ;
        RECT  43.116 27.312 43.2 27.336 ;
    END
  END o[397]
  PIN o[398]
    DIRECTION OUTPUT ;
    USE SIGNAL ;
    PORT
      LAYER M4 ;
        RECT  43.116 27.408 43.2 27.432 ;
    END
  END o[398]
  PIN o[399]
    DIRECTION OUTPUT ;
    USE SIGNAL ;
    PORT
      LAYER M4 ;
        RECT  43.116 27.504 43.2 27.528 ;
    END
  END o[399]
  PIN o[39]
    DIRECTION OUTPUT ;
    USE SIGNAL ;
    PORT
      LAYER M4 ;
        RECT  43.116 39.792 43.2 39.816 ;
    END
  END o[39]
  PIN o[3]
    DIRECTION OUTPUT ;
    USE SIGNAL ;
    PORT
      LAYER M4 ;
        RECT  43.116 45.552 43.2 45.576 ;
    END
  END o[3]
  PIN o[400]
    DIRECTION OUTPUT ;
    USE SIGNAL ;
    PORT
      LAYER M4 ;
        RECT  43.116 27.6 43.2 27.624 ;
    END
  END o[400]
  PIN o[401]
    DIRECTION OUTPUT ;
    USE SIGNAL ;
    PORT
      LAYER M4 ;
        RECT  43.116 27.696 43.2 27.72 ;
    END
  END o[401]
  PIN o[402]
    DIRECTION OUTPUT ;
    USE SIGNAL ;
    PORT
      LAYER M4 ;
        RECT  43.116 27.792 43.2 27.816 ;
    END
  END o[402]
  PIN o[403]
    DIRECTION OUTPUT ;
    USE SIGNAL ;
    PORT
      LAYER M4 ;
        RECT  43.116 27.888 43.2 27.912 ;
    END
  END o[403]
  PIN o[404]
    DIRECTION OUTPUT ;
    USE SIGNAL ;
    PORT
      LAYER M4 ;
        RECT  43.116 27.984 43.2 28.008 ;
    END
  END o[404]
  PIN o[405]
    DIRECTION OUTPUT ;
    USE SIGNAL ;
    PORT
      LAYER M4 ;
        RECT  43.116 28.08 43.2 28.104 ;
    END
  END o[405]
  PIN o[406]
    DIRECTION OUTPUT ;
    USE SIGNAL ;
    PORT
      LAYER M4 ;
        RECT  43.116 28.176 43.2 28.2 ;
    END
  END o[406]
  PIN o[407]
    DIRECTION OUTPUT ;
    USE SIGNAL ;
    PORT
      LAYER M4 ;
        RECT  43.116 28.272 43.2 28.296 ;
    END
  END o[407]
  PIN o[408]
    DIRECTION OUTPUT ;
    USE SIGNAL ;
    PORT
      LAYER M4 ;
        RECT  43.116 28.368 43.2 28.392 ;
    END
  END o[408]
  PIN o[409]
    DIRECTION OUTPUT ;
    USE SIGNAL ;
    PORT
      LAYER M4 ;
        RECT  43.116 28.464 43.2 28.488 ;
    END
  END o[409]
  PIN o[40]
    DIRECTION OUTPUT ;
    USE SIGNAL ;
    PORT
      LAYER M4 ;
        RECT  43.116 39.888 43.2 39.912 ;
    END
  END o[40]
  PIN o[410]
    DIRECTION OUTPUT ;
    USE SIGNAL ;
    PORT
      LAYER M4 ;
        RECT  43.116 28.56 43.2 28.584 ;
    END
  END o[410]
  PIN o[411]
    DIRECTION OUTPUT ;
    USE SIGNAL ;
    PORT
      LAYER M4 ;
        RECT  43.116 28.656 43.2 28.68 ;
    END
  END o[411]
  PIN o[412]
    DIRECTION OUTPUT ;
    USE SIGNAL ;
    PORT
      LAYER M4 ;
        RECT  43.116 28.752 43.2 28.776 ;
    END
  END o[412]
  PIN o[413]
    DIRECTION OUTPUT ;
    USE SIGNAL ;
    PORT
      LAYER M4 ;
        RECT  43.116 28.848 43.2 28.872 ;
    END
  END o[413]
  PIN o[414]
    DIRECTION OUTPUT ;
    USE SIGNAL ;
    PORT
      LAYER M4 ;
        RECT  43.116 28.944 43.2 28.968 ;
    END
  END o[414]
  PIN o[415]
    DIRECTION OUTPUT ;
    USE SIGNAL ;
    PORT
      LAYER M4 ;
        RECT  43.116 29.04 43.2 29.064 ;
    END
  END o[415]
  PIN o[416]
    DIRECTION OUTPUT ;
    USE SIGNAL ;
    PORT
      LAYER M4 ;
        RECT  43.116 35.28 43.2 35.304 ;
    END
  END o[416]
  PIN o[417]
    DIRECTION OUTPUT ;
    USE SIGNAL ;
    PORT
      LAYER M4 ;
        RECT  43.116 35.376 43.2 35.4 ;
    END
  END o[417]
  PIN o[418]
    DIRECTION OUTPUT ;
    USE SIGNAL ;
    PORT
      LAYER M4 ;
        RECT  43.116 35.472 43.2 35.496 ;
    END
  END o[418]
  PIN o[419]
    DIRECTION OUTPUT ;
    USE SIGNAL ;
    PORT
      LAYER M4 ;
        RECT  43.116 35.568 43.2 35.592 ;
    END
  END o[419]
  PIN o[41]
    DIRECTION OUTPUT ;
    USE SIGNAL ;
    PORT
      LAYER M4 ;
        RECT  43.116 39.984 43.2 40.008 ;
    END
  END o[41]
  PIN o[420]
    DIRECTION OUTPUT ;
    USE SIGNAL ;
    PORT
      LAYER M4 ;
        RECT  43.116 35.664 43.2 35.688 ;
    END
  END o[420]
  PIN o[421]
    DIRECTION OUTPUT ;
    USE SIGNAL ;
    PORT
      LAYER M4 ;
        RECT  43.116 35.76 43.2 35.784 ;
    END
  END o[421]
  PIN o[422]
    DIRECTION OUTPUT ;
    USE SIGNAL ;
    PORT
      LAYER M4 ;
        RECT  43.116 35.856 43.2 35.88 ;
    END
  END o[422]
  PIN o[423]
    DIRECTION OUTPUT ;
    USE SIGNAL ;
    PORT
      LAYER M4 ;
        RECT  43.116 35.952 43.2 35.976 ;
    END
  END o[423]
  PIN o[424]
    DIRECTION OUTPUT ;
    USE SIGNAL ;
    PORT
      LAYER M4 ;
        RECT  43.116 36.048 43.2 36.072 ;
    END
  END o[424]
  PIN o[425]
    DIRECTION OUTPUT ;
    USE SIGNAL ;
    PORT
      LAYER M4 ;
        RECT  43.116 36.144 43.2 36.168 ;
    END
  END o[425]
  PIN o[426]
    DIRECTION OUTPUT ;
    USE SIGNAL ;
    PORT
      LAYER M4 ;
        RECT  43.116 36.24 43.2 36.264 ;
    END
  END o[426]
  PIN o[427]
    DIRECTION OUTPUT ;
    USE SIGNAL ;
    PORT
      LAYER M4 ;
        RECT  43.116 36.336 43.2 36.36 ;
    END
  END o[427]
  PIN o[428]
    DIRECTION OUTPUT ;
    USE SIGNAL ;
    PORT
      LAYER M4 ;
        RECT  43.116 36.432 43.2 36.456 ;
    END
  END o[428]
  PIN o[429]
    DIRECTION OUTPUT ;
    USE SIGNAL ;
    PORT
      LAYER M4 ;
        RECT  43.116 36.528 43.2 36.552 ;
    END
  END o[429]
  PIN o[42]
    DIRECTION OUTPUT ;
    USE SIGNAL ;
    PORT
      LAYER M4 ;
        RECT  43.116 40.08 43.2 40.104 ;
    END
  END o[42]
  PIN o[430]
    DIRECTION OUTPUT ;
    USE SIGNAL ;
    PORT
      LAYER M4 ;
        RECT  43.116 36.624 43.2 36.648 ;
    END
  END o[430]
  PIN o[431]
    DIRECTION OUTPUT ;
    USE SIGNAL ;
    PORT
      LAYER M4 ;
        RECT  43.116 36.72 43.2 36.744 ;
    END
  END o[431]
  PIN o[432]
    DIRECTION OUTPUT ;
    USE SIGNAL ;
    PORT
      LAYER M4 ;
        RECT  43.116 36.816 43.2 36.84 ;
    END
  END o[432]
  PIN o[433]
    DIRECTION OUTPUT ;
    USE SIGNAL ;
    PORT
      LAYER M4 ;
        RECT  43.116 36.912 43.2 36.936 ;
    END
  END o[433]
  PIN o[434]
    DIRECTION OUTPUT ;
    USE SIGNAL ;
    PORT
      LAYER M4 ;
        RECT  43.116 37.008 43.2 37.032 ;
    END
  END o[434]
  PIN o[435]
    DIRECTION OUTPUT ;
    USE SIGNAL ;
    PORT
      LAYER M4 ;
        RECT  43.116 37.104 43.2 37.128 ;
    END
  END o[435]
  PIN o[436]
    DIRECTION OUTPUT ;
    USE SIGNAL ;
    PORT
      LAYER M4 ;
        RECT  43.116 37.2 43.2 37.224 ;
    END
  END o[436]
  PIN o[437]
    DIRECTION OUTPUT ;
    USE SIGNAL ;
    PORT
      LAYER M4 ;
        RECT  43.116 37.296 43.2 37.32 ;
    END
  END o[437]
  PIN o[438]
    DIRECTION OUTPUT ;
    USE SIGNAL ;
    PORT
      LAYER M4 ;
        RECT  43.116 37.392 43.2 37.416 ;
    END
  END o[438]
  PIN o[439]
    DIRECTION OUTPUT ;
    USE SIGNAL ;
    PORT
      LAYER M4 ;
        RECT  43.116 37.488 43.2 37.512 ;
    END
  END o[439]
  PIN o[43]
    DIRECTION OUTPUT ;
    USE SIGNAL ;
    PORT
      LAYER M4 ;
        RECT  43.116 40.176 43.2 40.2 ;
    END
  END o[43]
  PIN o[440]
    DIRECTION OUTPUT ;
    USE SIGNAL ;
    PORT
      LAYER M4 ;
        RECT  43.116 37.584 43.2 37.608 ;
    END
  END o[440]
  PIN o[441]
    DIRECTION OUTPUT ;
    USE SIGNAL ;
    PORT
      LAYER M4 ;
        RECT  43.116 37.68 43.2 37.704 ;
    END
  END o[441]
  PIN o[442]
    DIRECTION OUTPUT ;
    USE SIGNAL ;
    PORT
      LAYER M4 ;
        RECT  43.116 37.776 43.2 37.8 ;
    END
  END o[442]
  PIN o[443]
    DIRECTION OUTPUT ;
    USE SIGNAL ;
    PORT
      LAYER M4 ;
        RECT  43.116 37.872 43.2 37.896 ;
    END
  END o[443]
  PIN o[444]
    DIRECTION OUTPUT ;
    USE SIGNAL ;
    PORT
      LAYER M4 ;
        RECT  43.116 37.968 43.2 37.992 ;
    END
  END o[444]
  PIN o[445]
    DIRECTION OUTPUT ;
    USE SIGNAL ;
    PORT
      LAYER M4 ;
        RECT  43.116 38.064 43.2 38.088 ;
    END
  END o[445]
  PIN o[446]
    DIRECTION OUTPUT ;
    USE SIGNAL ;
    PORT
      LAYER M4 ;
        RECT  43.116 38.16 43.2 38.184 ;
    END
  END o[446]
  PIN o[447]
    DIRECTION OUTPUT ;
    USE SIGNAL ;
    PORT
      LAYER M4 ;
        RECT  43.116 38.256 43.2 38.28 ;
    END
  END o[447]
  PIN o[448]
    DIRECTION OUTPUT ;
    USE SIGNAL ;
    PORT
      LAYER M4 ;
        RECT  43.116 29.136 43.2 29.16 ;
    END
  END o[448]
  PIN o[449]
    DIRECTION OUTPUT ;
    USE SIGNAL ;
    PORT
      LAYER M4 ;
        RECT  43.116 29.232 43.2 29.256 ;
    END
  END o[449]
  PIN o[44]
    DIRECTION OUTPUT ;
    USE SIGNAL ;
    PORT
      LAYER M4 ;
        RECT  43.116 40.272 43.2 40.296 ;
    END
  END o[44]
  PIN o[450]
    DIRECTION OUTPUT ;
    USE SIGNAL ;
    PORT
      LAYER M4 ;
        RECT  43.116 29.328 43.2 29.352 ;
    END
  END o[450]
  PIN o[451]
    DIRECTION OUTPUT ;
    USE SIGNAL ;
    PORT
      LAYER M4 ;
        RECT  43.116 29.424 43.2 29.448 ;
    END
  END o[451]
  PIN o[452]
    DIRECTION OUTPUT ;
    USE SIGNAL ;
    PORT
      LAYER M4 ;
        RECT  43.116 29.52 43.2 29.544 ;
    END
  END o[452]
  PIN o[453]
    DIRECTION OUTPUT ;
    USE SIGNAL ;
    PORT
      LAYER M4 ;
        RECT  43.116 29.616 43.2 29.64 ;
    END
  END o[453]
  PIN o[454]
    DIRECTION OUTPUT ;
    USE SIGNAL ;
    PORT
      LAYER M4 ;
        RECT  43.116 29.712 43.2 29.736 ;
    END
  END o[454]
  PIN o[455]
    DIRECTION OUTPUT ;
    USE SIGNAL ;
    PORT
      LAYER M4 ;
        RECT  43.116 29.808 43.2 29.832 ;
    END
  END o[455]
  PIN o[456]
    DIRECTION OUTPUT ;
    USE SIGNAL ;
    PORT
      LAYER M4 ;
        RECT  43.116 29.904 43.2 29.928 ;
    END
  END o[456]
  PIN o[457]
    DIRECTION OUTPUT ;
    USE SIGNAL ;
    PORT
      LAYER M4 ;
        RECT  43.116 30 43.2 30.024 ;
    END
  END o[457]
  PIN o[458]
    DIRECTION OUTPUT ;
    USE SIGNAL ;
    PORT
      LAYER M4 ;
        RECT  43.116 30.096 43.2 30.12 ;
    END
  END o[458]
  PIN o[459]
    DIRECTION OUTPUT ;
    USE SIGNAL ;
    PORT
      LAYER M4 ;
        RECT  43.116 30.192 43.2 30.216 ;
    END
  END o[459]
  PIN o[45]
    DIRECTION OUTPUT ;
    USE SIGNAL ;
    PORT
      LAYER M4 ;
        RECT  43.116 40.368 43.2 40.392 ;
    END
  END o[45]
  PIN o[460]
    DIRECTION OUTPUT ;
    USE SIGNAL ;
    PORT
      LAYER M4 ;
        RECT  43.116 30.288 43.2 30.312 ;
    END
  END o[460]
  PIN o[461]
    DIRECTION OUTPUT ;
    USE SIGNAL ;
    PORT
      LAYER M4 ;
        RECT  43.116 30.384 43.2 30.408 ;
    END
  END o[461]
  PIN o[462]
    DIRECTION OUTPUT ;
    USE SIGNAL ;
    PORT
      LAYER M4 ;
        RECT  43.116 30.48 43.2 30.504 ;
    END
  END o[462]
  PIN o[463]
    DIRECTION OUTPUT ;
    USE SIGNAL ;
    PORT
      LAYER M4 ;
        RECT  43.116 30.576 43.2 30.6 ;
    END
  END o[463]
  PIN o[464]
    DIRECTION OUTPUT ;
    USE SIGNAL ;
    PORT
      LAYER M4 ;
        RECT  43.116 30.672 43.2 30.696 ;
    END
  END o[464]
  PIN o[465]
    DIRECTION OUTPUT ;
    USE SIGNAL ;
    PORT
      LAYER M4 ;
        RECT  43.116 30.768 43.2 30.792 ;
    END
  END o[465]
  PIN o[466]
    DIRECTION OUTPUT ;
    USE SIGNAL ;
    PORT
      LAYER M4 ;
        RECT  43.116 30.864 43.2 30.888 ;
    END
  END o[466]
  PIN o[467]
    DIRECTION OUTPUT ;
    USE SIGNAL ;
    PORT
      LAYER M4 ;
        RECT  43.116 30.96 43.2 30.984 ;
    END
  END o[467]
  PIN o[468]
    DIRECTION OUTPUT ;
    USE SIGNAL ;
    PORT
      LAYER M4 ;
        RECT  43.116 31.056 43.2 31.08 ;
    END
  END o[468]
  PIN o[469]
    DIRECTION OUTPUT ;
    USE SIGNAL ;
    PORT
      LAYER M4 ;
        RECT  43.116 31.152 43.2 31.176 ;
    END
  END o[469]
  PIN o[46]
    DIRECTION OUTPUT ;
    USE SIGNAL ;
    PORT
      LAYER M4 ;
        RECT  43.116 40.464 43.2 40.488 ;
    END
  END o[46]
  PIN o[470]
    DIRECTION OUTPUT ;
    USE SIGNAL ;
    PORT
      LAYER M4 ;
        RECT  43.116 31.248 43.2 31.272 ;
    END
  END o[470]
  PIN o[471]
    DIRECTION OUTPUT ;
    USE SIGNAL ;
    PORT
      LAYER M4 ;
        RECT  43.116 31.344 43.2 31.368 ;
    END
  END o[471]
  PIN o[472]
    DIRECTION OUTPUT ;
    USE SIGNAL ;
    PORT
      LAYER M4 ;
        RECT  43.116 31.44 43.2 31.464 ;
    END
  END o[472]
  PIN o[473]
    DIRECTION OUTPUT ;
    USE SIGNAL ;
    PORT
      LAYER M4 ;
        RECT  43.116 31.536 43.2 31.56 ;
    END
  END o[473]
  PIN o[474]
    DIRECTION OUTPUT ;
    USE SIGNAL ;
    PORT
      LAYER M4 ;
        RECT  43.116 31.632 43.2 31.656 ;
    END
  END o[474]
  PIN o[475]
    DIRECTION OUTPUT ;
    USE SIGNAL ;
    PORT
      LAYER M4 ;
        RECT  43.116 31.728 43.2 31.752 ;
    END
  END o[475]
  PIN o[476]
    DIRECTION OUTPUT ;
    USE SIGNAL ;
    PORT
      LAYER M4 ;
        RECT  43.116 31.824 43.2 31.848 ;
    END
  END o[476]
  PIN o[477]
    DIRECTION OUTPUT ;
    USE SIGNAL ;
    PORT
      LAYER M4 ;
        RECT  43.116 31.92 43.2 31.944 ;
    END
  END o[477]
  PIN o[478]
    DIRECTION OUTPUT ;
    USE SIGNAL ;
    PORT
      LAYER M4 ;
        RECT  43.116 32.016 43.2 32.04 ;
    END
  END o[478]
  PIN o[479]
    DIRECTION OUTPUT ;
    USE SIGNAL ;
    PORT
      LAYER M4 ;
        RECT  43.116 32.112 43.2 32.136 ;
    END
  END o[479]
  PIN o[47]
    DIRECTION OUTPUT ;
    USE SIGNAL ;
    PORT
      LAYER M4 ;
        RECT  43.116 40.56 43.2 40.584 ;
    END
  END o[47]
  PIN o[480]
    DIRECTION OUTPUT ;
    USE SIGNAL ;
    PORT
      LAYER M4 ;
        RECT  43.116 32.208 43.2 32.232 ;
    END
  END o[480]
  PIN o[481]
    DIRECTION OUTPUT ;
    USE SIGNAL ;
    PORT
      LAYER M4 ;
        RECT  43.116 32.304 43.2 32.328 ;
    END
  END o[481]
  PIN o[482]
    DIRECTION OUTPUT ;
    USE SIGNAL ;
    PORT
      LAYER M4 ;
        RECT  43.116 32.4 43.2 32.424 ;
    END
  END o[482]
  PIN o[483]
    DIRECTION OUTPUT ;
    USE SIGNAL ;
    PORT
      LAYER M4 ;
        RECT  43.116 32.496 43.2 32.52 ;
    END
  END o[483]
  PIN o[484]
    DIRECTION OUTPUT ;
    USE SIGNAL ;
    PORT
      LAYER M4 ;
        RECT  43.116 32.592 43.2 32.616 ;
    END
  END o[484]
  PIN o[485]
    DIRECTION OUTPUT ;
    USE SIGNAL ;
    PORT
      LAYER M4 ;
        RECT  43.116 32.688 43.2 32.712 ;
    END
  END o[485]
  PIN o[486]
    DIRECTION OUTPUT ;
    USE SIGNAL ;
    PORT
      LAYER M4 ;
        RECT  43.116 32.784 43.2 32.808 ;
    END
  END o[486]
  PIN o[487]
    DIRECTION OUTPUT ;
    USE SIGNAL ;
    PORT
      LAYER M4 ;
        RECT  43.116 32.88 43.2 32.904 ;
    END
  END o[487]
  PIN o[488]
    DIRECTION OUTPUT ;
    USE SIGNAL ;
    PORT
      LAYER M4 ;
        RECT  43.116 32.976 43.2 33 ;
    END
  END o[488]
  PIN o[489]
    DIRECTION OUTPUT ;
    USE SIGNAL ;
    PORT
      LAYER M4 ;
        RECT  43.116 33.072 43.2 33.096 ;
    END
  END o[489]
  PIN o[48]
    DIRECTION OUTPUT ;
    USE SIGNAL ;
    PORT
      LAYER M4 ;
        RECT  43.116 40.656 43.2 40.68 ;
    END
  END o[48]
  PIN o[490]
    DIRECTION OUTPUT ;
    USE SIGNAL ;
    PORT
      LAYER M4 ;
        RECT  43.116 33.168 43.2 33.192 ;
    END
  END o[490]
  PIN o[491]
    DIRECTION OUTPUT ;
    USE SIGNAL ;
    PORT
      LAYER M4 ;
        RECT  43.116 33.264 43.2 33.288 ;
    END
  END o[491]
  PIN o[492]
    DIRECTION OUTPUT ;
    USE SIGNAL ;
    PORT
      LAYER M4 ;
        RECT  43.116 33.36 43.2 33.384 ;
    END
  END o[492]
  PIN o[493]
    DIRECTION OUTPUT ;
    USE SIGNAL ;
    PORT
      LAYER M4 ;
        RECT  43.116 33.456 43.2 33.48 ;
    END
  END o[493]
  PIN o[494]
    DIRECTION OUTPUT ;
    USE SIGNAL ;
    PORT
      LAYER M4 ;
        RECT  43.116 33.552 43.2 33.576 ;
    END
  END o[494]
  PIN o[495]
    DIRECTION OUTPUT ;
    USE SIGNAL ;
    PORT
      LAYER M4 ;
        RECT  43.116 33.648 43.2 33.672 ;
    END
  END o[495]
  PIN o[496]
    DIRECTION OUTPUT ;
    USE SIGNAL ;
    PORT
      LAYER M4 ;
        RECT  43.116 33.744 43.2 33.768 ;
    END
  END o[496]
  PIN o[497]
    DIRECTION OUTPUT ;
    USE SIGNAL ;
    PORT
      LAYER M4 ;
        RECT  43.116 33.84 43.2 33.864 ;
    END
  END o[497]
  PIN o[498]
    DIRECTION OUTPUT ;
    USE SIGNAL ;
    PORT
      LAYER M4 ;
        RECT  43.116 33.936 43.2 33.96 ;
    END
  END o[498]
  PIN o[499]
    DIRECTION OUTPUT ;
    USE SIGNAL ;
    PORT
      LAYER M4 ;
        RECT  43.116 34.032 43.2 34.056 ;
    END
  END o[499]
  PIN o[49]
    DIRECTION OUTPUT ;
    USE SIGNAL ;
    PORT
      LAYER M4 ;
        RECT  43.116 40.752 43.2 40.776 ;
    END
  END o[49]
  PIN o[4]
    DIRECTION OUTPUT ;
    USE SIGNAL ;
    PORT
      LAYER M4 ;
        RECT  43.116 45.648 43.2 45.672 ;
    END
  END o[4]
  PIN o[500]
    DIRECTION OUTPUT ;
    USE SIGNAL ;
    PORT
      LAYER M4 ;
        RECT  43.116 34.128 43.2 34.152 ;
    END
  END o[500]
  PIN o[501]
    DIRECTION OUTPUT ;
    USE SIGNAL ;
    PORT
      LAYER M4 ;
        RECT  43.116 34.224 43.2 34.248 ;
    END
  END o[501]
  PIN o[502]
    DIRECTION OUTPUT ;
    USE SIGNAL ;
    PORT
      LAYER M4 ;
        RECT  43.116 34.32 43.2 34.344 ;
    END
  END o[502]
  PIN o[503]
    DIRECTION OUTPUT ;
    USE SIGNAL ;
    PORT
      LAYER M4 ;
        RECT  43.116 34.416 43.2 34.44 ;
    END
  END o[503]
  PIN o[504]
    DIRECTION OUTPUT ;
    USE SIGNAL ;
    PORT
      LAYER M4 ;
        RECT  43.116 34.512 43.2 34.536 ;
    END
  END o[504]
  PIN o[505]
    DIRECTION OUTPUT ;
    USE SIGNAL ;
    PORT
      LAYER M4 ;
        RECT  43.116 34.608 43.2 34.632 ;
    END
  END o[505]
  PIN o[506]
    DIRECTION OUTPUT ;
    USE SIGNAL ;
    PORT
      LAYER M4 ;
        RECT  43.116 34.704 43.2 34.728 ;
    END
  END o[506]
  PIN o[507]
    DIRECTION OUTPUT ;
    USE SIGNAL ;
    PORT
      LAYER M4 ;
        RECT  43.116 34.8 43.2 34.824 ;
    END
  END o[507]
  PIN o[508]
    DIRECTION OUTPUT ;
    USE SIGNAL ;
    PORT
      LAYER M4 ;
        RECT  43.116 34.896 43.2 34.92 ;
    END
  END o[508]
  PIN o[509]
    DIRECTION OUTPUT ;
    USE SIGNAL ;
    PORT
      LAYER M4 ;
        RECT  43.116 34.992 43.2 35.016 ;
    END
  END o[509]
  PIN o[50]
    DIRECTION OUTPUT ;
    USE SIGNAL ;
    PORT
      LAYER M4 ;
        RECT  43.116 40.848 43.2 40.872 ;
    END
  END o[50]
  PIN o[510]
    DIRECTION OUTPUT ;
    USE SIGNAL ;
    PORT
      LAYER M4 ;
        RECT  43.116 35.088 43.2 35.112 ;
    END
  END o[510]
  PIN o[511]
    DIRECTION OUTPUT ;
    USE SIGNAL ;
    PORT
      LAYER M4 ;
        RECT  43.116 35.184 43.2 35.208 ;
    END
  END o[511]
  PIN o[512]
    DIRECTION OUTPUT ;
    USE SIGNAL ;
    PORT
      LAYER M4 ;
        RECT  43.116 22.992 43.2 23.016 ;
    END
  END o[512]
  PIN o[513]
    DIRECTION OUTPUT ;
    USE SIGNAL ;
    PORT
      LAYER M4 ;
        RECT  43.116 23.088 43.2 23.112 ;
    END
  END o[513]
  PIN o[514]
    DIRECTION OUTPUT ;
    USE SIGNAL ;
    PORT
      LAYER M4 ;
        RECT  43.116 23.184 43.2 23.208 ;
    END
  END o[514]
  PIN o[515]
    DIRECTION OUTPUT ;
    USE SIGNAL ;
    PORT
      LAYER M4 ;
        RECT  43.116 23.28 43.2 23.304 ;
    END
  END o[515]
  PIN o[516]
    DIRECTION OUTPUT ;
    USE SIGNAL ;
    PORT
      LAYER M4 ;
        RECT  43.116 23.376 43.2 23.4 ;
    END
  END o[516]
  PIN o[517]
    DIRECTION OUTPUT ;
    USE SIGNAL ;
    PORT
      LAYER M4 ;
        RECT  43.116 23.472 43.2 23.496 ;
    END
  END o[517]
  PIN o[518]
    DIRECTION OUTPUT ;
    USE SIGNAL ;
    PORT
      LAYER M4 ;
        RECT  43.116 23.568 43.2 23.592 ;
    END
  END o[518]
  PIN o[519]
    DIRECTION OUTPUT ;
    USE SIGNAL ;
    PORT
      LAYER M4 ;
        RECT  43.116 23.664 43.2 23.688 ;
    END
  END o[519]
  PIN o[51]
    DIRECTION OUTPUT ;
    USE SIGNAL ;
    PORT
      LAYER M4 ;
        RECT  43.116 40.944 43.2 40.968 ;
    END
  END o[51]
  PIN o[520]
    DIRECTION OUTPUT ;
    USE SIGNAL ;
    PORT
      LAYER M4 ;
        RECT  43.116 23.76 43.2 23.784 ;
    END
  END o[520]
  PIN o[521]
    DIRECTION OUTPUT ;
    USE SIGNAL ;
    PORT
      LAYER M4 ;
        RECT  43.116 23.856 43.2 23.88 ;
    END
  END o[521]
  PIN o[522]
    DIRECTION OUTPUT ;
    USE SIGNAL ;
    PORT
      LAYER M4 ;
        RECT  43.116 23.952 43.2 23.976 ;
    END
  END o[522]
  PIN o[523]
    DIRECTION OUTPUT ;
    USE SIGNAL ;
    PORT
      LAYER M4 ;
        RECT  43.116 24.048 43.2 24.072 ;
    END
  END o[523]
  PIN o[524]
    DIRECTION OUTPUT ;
    USE SIGNAL ;
    PORT
      LAYER M4 ;
        RECT  43.116 24.144 43.2 24.168 ;
    END
  END o[524]
  PIN o[525]
    DIRECTION OUTPUT ;
    USE SIGNAL ;
    PORT
      LAYER M4 ;
        RECT  43.116 24.24 43.2 24.264 ;
    END
  END o[525]
  PIN o[526]
    DIRECTION OUTPUT ;
    USE SIGNAL ;
    PORT
      LAYER M4 ;
        RECT  43.116 24.336 43.2 24.36 ;
    END
  END o[526]
  PIN o[527]
    DIRECTION OUTPUT ;
    USE SIGNAL ;
    PORT
      LAYER M4 ;
        RECT  43.116 24.432 43.2 24.456 ;
    END
  END o[527]
  PIN o[528]
    DIRECTION OUTPUT ;
    USE SIGNAL ;
    PORT
      LAYER M4 ;
        RECT  43.116 24.528 43.2 24.552 ;
    END
  END o[528]
  PIN o[52]
    DIRECTION OUTPUT ;
    USE SIGNAL ;
    PORT
      LAYER M4 ;
        RECT  43.116 41.04 43.2 41.064 ;
    END
  END o[52]
  PIN o[53]
    DIRECTION OUTPUT ;
    USE SIGNAL ;
    PORT
      LAYER M4 ;
        RECT  43.116 41.136 43.2 41.16 ;
    END
  END o[53]
  PIN o[54]
    DIRECTION OUTPUT ;
    USE SIGNAL ;
    PORT
      LAYER M4 ;
        RECT  43.116 41.232 43.2 41.256 ;
    END
  END o[54]
  PIN o[55]
    DIRECTION OUTPUT ;
    USE SIGNAL ;
    PORT
      LAYER M4 ;
        RECT  43.116 41.328 43.2 41.352 ;
    END
  END o[55]
  PIN o[56]
    DIRECTION OUTPUT ;
    USE SIGNAL ;
    PORT
      LAYER M4 ;
        RECT  43.116 41.424 43.2 41.448 ;
    END
  END o[56]
  PIN o[57]
    DIRECTION OUTPUT ;
    USE SIGNAL ;
    PORT
      LAYER M4 ;
        RECT  43.116 41.52 43.2 41.544 ;
    END
  END o[57]
  PIN o[58]
    DIRECTION OUTPUT ;
    USE SIGNAL ;
    PORT
      LAYER M4 ;
        RECT  43.116 41.616 43.2 41.64 ;
    END
  END o[58]
  PIN o[59]
    DIRECTION OUTPUT ;
    USE SIGNAL ;
    PORT
      LAYER M4 ;
        RECT  43.116 41.712 43.2 41.736 ;
    END
  END o[59]
  PIN o[5]
    DIRECTION OUTPUT ;
    USE SIGNAL ;
    PORT
      LAYER M4 ;
        RECT  43.116 45.744 43.2 45.768 ;
    END
  END o[5]
  PIN o[60]
    DIRECTION OUTPUT ;
    USE SIGNAL ;
    PORT
      LAYER M4 ;
        RECT  43.116 41.808 43.2 41.832 ;
    END
  END o[60]
  PIN o[61]
    DIRECTION OUTPUT ;
    USE SIGNAL ;
    PORT
      LAYER M4 ;
        RECT  43.116 41.904 43.2 41.928 ;
    END
  END o[61]
  PIN o[62]
    DIRECTION OUTPUT ;
    USE SIGNAL ;
    PORT
      LAYER M4 ;
        RECT  43.116 42 43.2 42.024 ;
    END
  END o[62]
  PIN o[63]
    DIRECTION OUTPUT ;
    USE SIGNAL ;
    PORT
      LAYER M4 ;
        RECT  43.116 42.096 43.2 42.12 ;
    END
  END o[63]
  PIN o[64]
    DIRECTION OUTPUT ;
    USE SIGNAL ;
    PORT
      LAYER M4 ;
        RECT  43.116 51.408 43.2 51.432 ;
    END
  END o[64]
  PIN o[65]
    DIRECTION OUTPUT ;
    USE SIGNAL ;
    PORT
      LAYER M4 ;
        RECT  43.116 51.504 43.2 51.528 ;
    END
  END o[65]
  PIN o[66]
    DIRECTION OUTPUT ;
    USE SIGNAL ;
    PORT
      LAYER M4 ;
        RECT  43.116 51.6 43.2 51.624 ;
    END
  END o[66]
  PIN o[67]
    DIRECTION OUTPUT ;
    USE SIGNAL ;
    PORT
      LAYER M4 ;
        RECT  43.116 51.696 43.2 51.72 ;
    END
  END o[67]
  PIN o[68]
    DIRECTION OUTPUT ;
    USE SIGNAL ;
    PORT
      LAYER M4 ;
        RECT  43.116 51.792 43.2 51.816 ;
    END
  END o[68]
  PIN o[69]
    DIRECTION OUTPUT ;
    USE SIGNAL ;
    PORT
      LAYER M4 ;
        RECT  43.116 51.888 43.2 51.912 ;
    END
  END o[69]
  PIN o[6]
    DIRECTION OUTPUT ;
    USE SIGNAL ;
    PORT
      LAYER M4 ;
        RECT  43.116 45.84 43.2 45.864 ;
    END
  END o[6]
  PIN o[70]
    DIRECTION OUTPUT ;
    USE SIGNAL ;
    PORT
      LAYER M4 ;
        RECT  43.116 51.984 43.2 52.008 ;
    END
  END o[70]
  PIN o[71]
    DIRECTION OUTPUT ;
    USE SIGNAL ;
    PORT
      LAYER M4 ;
        RECT  43.116 52.08 43.2 52.104 ;
    END
  END o[71]
  PIN o[72]
    DIRECTION OUTPUT ;
    USE SIGNAL ;
    PORT
      LAYER M4 ;
        RECT  43.116 52.176 43.2 52.2 ;
    END
  END o[72]
  PIN o[73]
    DIRECTION OUTPUT ;
    USE SIGNAL ;
    PORT
      LAYER M4 ;
        RECT  43.116 52.272 43.2 52.296 ;
    END
  END o[73]
  PIN o[74]
    DIRECTION OUTPUT ;
    USE SIGNAL ;
    PORT
      LAYER M4 ;
        RECT  43.116 52.368 43.2 52.392 ;
    END
  END o[74]
  PIN o[75]
    DIRECTION OUTPUT ;
    USE SIGNAL ;
    PORT
      LAYER M4 ;
        RECT  43.116 52.464 43.2 52.488 ;
    END
  END o[75]
  PIN o[76]
    DIRECTION OUTPUT ;
    USE SIGNAL ;
    PORT
      LAYER M4 ;
        RECT  43.116 52.56 43.2 52.584 ;
    END
  END o[76]
  PIN o[77]
    DIRECTION OUTPUT ;
    USE SIGNAL ;
    PORT
      LAYER M4 ;
        RECT  43.116 52.656 43.2 52.68 ;
    END
  END o[77]
  PIN o[78]
    DIRECTION OUTPUT ;
    USE SIGNAL ;
    PORT
      LAYER M4 ;
        RECT  43.116 52.752 43.2 52.776 ;
    END
  END o[78]
  PIN o[79]
    DIRECTION OUTPUT ;
    USE SIGNAL ;
    PORT
      LAYER M4 ;
        RECT  43.116 52.848 43.2 52.872 ;
    END
  END o[79]
  PIN o[7]
    DIRECTION OUTPUT ;
    USE SIGNAL ;
    PORT
      LAYER M4 ;
        RECT  43.116 45.936 43.2 45.96 ;
    END
  END o[7]
  PIN o[80]
    DIRECTION OUTPUT ;
    USE SIGNAL ;
    PORT
      LAYER M4 ;
        RECT  43.116 52.944 43.2 52.968 ;
    END
  END o[80]
  PIN o[81]
    DIRECTION OUTPUT ;
    USE SIGNAL ;
    PORT
      LAYER M4 ;
        RECT  43.116 53.04 43.2 53.064 ;
    END
  END o[81]
  PIN o[82]
    DIRECTION OUTPUT ;
    USE SIGNAL ;
    PORT
      LAYER M4 ;
        RECT  43.116 53.136 43.2 53.16 ;
    END
  END o[82]
  PIN o[83]
    DIRECTION OUTPUT ;
    USE SIGNAL ;
    PORT
      LAYER M4 ;
        RECT  43.116 53.232 43.2 53.256 ;
    END
  END o[83]
  PIN o[84]
    DIRECTION OUTPUT ;
    USE SIGNAL ;
    PORT
      LAYER M4 ;
        RECT  43.116 53.328 43.2 53.352 ;
    END
  END o[84]
  PIN o[85]
    DIRECTION OUTPUT ;
    USE SIGNAL ;
    PORT
      LAYER M4 ;
        RECT  43.116 53.424 43.2 53.448 ;
    END
  END o[85]
  PIN o[86]
    DIRECTION OUTPUT ;
    USE SIGNAL ;
    PORT
      LAYER M4 ;
        RECT  43.116 53.52 43.2 53.544 ;
    END
  END o[86]
  PIN o[87]
    DIRECTION OUTPUT ;
    USE SIGNAL ;
    PORT
      LAYER M4 ;
        RECT  43.116 53.616 43.2 53.64 ;
    END
  END o[87]
  PIN o[88]
    DIRECTION OUTPUT ;
    USE SIGNAL ;
    PORT
      LAYER M4 ;
        RECT  43.116 53.712 43.2 53.736 ;
    END
  END o[88]
  PIN o[89]
    DIRECTION OUTPUT ;
    USE SIGNAL ;
    PORT
      LAYER M4 ;
        RECT  43.116 53.808 43.2 53.832 ;
    END
  END o[89]
  PIN o[8]
    DIRECTION OUTPUT ;
    USE SIGNAL ;
    PORT
      LAYER M4 ;
        RECT  43.116 46.032 43.2 46.056 ;
    END
  END o[8]
  PIN o[90]
    DIRECTION OUTPUT ;
    USE SIGNAL ;
    PORT
      LAYER M4 ;
        RECT  43.116 53.904 43.2 53.928 ;
    END
  END o[90]
  PIN o[91]
    DIRECTION OUTPUT ;
    USE SIGNAL ;
    PORT
      LAYER M4 ;
        RECT  43.116 54 43.2 54.024 ;
    END
  END o[91]
  PIN o[92]
    DIRECTION OUTPUT ;
    USE SIGNAL ;
    PORT
      LAYER M4 ;
        RECT  43.116 54.096 43.2 54.12 ;
    END
  END o[92]
  PIN o[93]
    DIRECTION OUTPUT ;
    USE SIGNAL ;
    PORT
      LAYER M4 ;
        RECT  43.116 54.192 43.2 54.216 ;
    END
  END o[93]
  PIN o[94]
    DIRECTION OUTPUT ;
    USE SIGNAL ;
    PORT
      LAYER M4 ;
        RECT  43.116 54.288 43.2 54.312 ;
    END
  END o[94]
  PIN o[95]
    DIRECTION OUTPUT ;
    USE SIGNAL ;
    PORT
      LAYER M4 ;
        RECT  43.116 54.384 43.2 54.408 ;
    END
  END o[95]
  PIN o[96]
    DIRECTION OUTPUT ;
    USE SIGNAL ;
    PORT
      LAYER M4 ;
        RECT  43.116 54.48 43.2 54.504 ;
    END
  END o[96]
  PIN o[97]
    DIRECTION OUTPUT ;
    USE SIGNAL ;
    PORT
      LAYER M4 ;
        RECT  43.116 54.576 43.2 54.6 ;
    END
  END o[97]
  PIN o[98]
    DIRECTION OUTPUT ;
    USE SIGNAL ;
    PORT
      LAYER M4 ;
        RECT  43.116 54.672 43.2 54.696 ;
    END
  END o[98]
  PIN o[99]
    DIRECTION OUTPUT ;
    USE SIGNAL ;
    PORT
      LAYER M4 ;
        RECT  43.116 54.768 43.2 54.792 ;
    END
  END o[99]
  PIN o[9]
    DIRECTION OUTPUT ;
    USE SIGNAL ;
    PORT
      LAYER M4 ;
        RECT  43.116 46.128 43.2 46.152 ;
    END
  END o[9]
  PIN rst[0]
    DIRECTION INPUT ;
    USE SIGNAL ;
    PORT
      LAYER M5 ;
        RECT  26.736 0 26.76 0.084 ;
    END
  END rst[0]
  PIN VDD
    DIRECTION INOUT ;
    USE POWER ;
    PORT
      LAYER M5 ;
        RECT  40.392 2.151 40.512 105.849 ;
        RECT  34.992 2.151 35.112 105.849 ;
        RECT  29.592 2.151 29.712 105.849 ;
        RECT  24.192 2.151 24.312 105.849 ;
        RECT  18.792 2.151 18.912 105.849 ;
        RECT  13.392 2.151 13.512 105.849 ;
        RECT  7.992 2.151 8.112 105.849 ;
        RECT  2.592 2.151 2.712 105.849 ;
    END
  END VDD
  PIN VSS
    DIRECTION INOUT ;
    USE GROUND ;
    PORT
      LAYER M5 ;
        RECT  40.2 2.137 40.32 105.863 ;
        RECT  34.8 2.137 34.92 105.863 ;
        RECT  29.4 2.137 29.52 105.863 ;
        RECT  24 2.137 24.12 105.863 ;
        RECT  18.6 2.137 18.72 105.863 ;
        RECT  13.2 2.137 13.32 105.863 ;
        RECT  7.8 2.137 7.92 105.863 ;
        RECT  2.4 2.137 2.52 105.863 ;
    END
  END VSS
  OBS
    LAYER RVTN ;
     RECT  2.16 2.16 41.04 2.295 ;
     RECT  2.16 2.565 41.04 2.835 ;
     RECT  2.16 3.105 41.04 3.375 ;
     RECT  2.16 3.645 41.04 3.915 ;
     RECT  2.16 4.185 41.04 4.455 ;
     RECT  2.16 4.725 41.04 4.995 ;
     RECT  2.16 5.265 41.04 5.535 ;
     RECT  2.16 5.805 41.04 6.075 ;
     RECT  2.16 6.345 41.04 6.615 ;
     RECT  2.16 6.885 41.04 7.155 ;
     RECT  2.16 7.425 41.04 7.695 ;
     RECT  2.16 7.965 41.04 8.235 ;
     RECT  2.16 8.505 41.04 8.775 ;
     RECT  2.16 9.045 41.04 9.315 ;
     RECT  2.16 9.585 41.04 9.855 ;
     RECT  2.16 10.125 41.04 10.395 ;
     RECT  2.16 10.665 41.04 10.935 ;
     RECT  2.16 11.205 41.04 11.475 ;
     RECT  2.16 11.745 41.04 12.015 ;
     RECT  2.16 12.285 41.04 12.555 ;
     RECT  2.16 12.825 41.04 13.095 ;
     RECT  2.16 13.365 41.04 13.635 ;
     RECT  2.16 13.905 41.04 14.175 ;
     RECT  2.16 14.445 41.04 14.715 ;
     RECT  2.16 14.985 41.04 15.255 ;
     RECT  2.16 15.525 41.04 15.795 ;
     RECT  2.16 16.065 41.04 16.335 ;
     RECT  2.16 16.605 41.04 16.875 ;
     RECT  2.16 17.145 41.04 17.415 ;
     RECT  2.16 17.685 41.04 17.955 ;
     RECT  2.16 18.225 41.04 18.495 ;
     RECT  2.16 18.765 41.04 19.035 ;
     RECT  2.16 19.305 41.04 19.575 ;
     RECT  2.16 19.845 41.04 20.115 ;
     RECT  2.16 20.385 41.04 20.655 ;
     RECT  2.16 20.925 41.04 21.195 ;
     RECT  2.16 21.465 41.04 21.735 ;
     RECT  2.16 22.005 41.04 22.275 ;
     RECT  2.16 22.545 41.04 22.815 ;
     RECT  2.16 23.085 41.04 23.355 ;
     RECT  2.16 23.625 41.04 23.895 ;
     RECT  2.16 24.165 41.04 24.435 ;
     RECT  2.16 24.705 41.04 24.975 ;
     RECT  2.16 25.245 41.04 25.515 ;
     RECT  2.16 25.785 41.04 26.055 ;
     RECT  2.16 26.325 41.04 26.595 ;
     RECT  2.16 26.865 41.04 27.135 ;
     RECT  2.16 27.405 41.04 27.675 ;
     RECT  2.16 27.945 41.04 28.215 ;
     RECT  2.16 28.485 41.04 28.755 ;
     RECT  2.16 29.025 41.04 29.295 ;
     RECT  2.16 29.565 41.04 29.835 ;
     RECT  2.16 30.105 41.04 30.375 ;
     RECT  2.16 30.645 41.04 30.915 ;
     RECT  2.16 31.185 41.04 31.455 ;
     RECT  2.16 31.725 41.04 31.995 ;
     RECT  2.16 32.265 41.04 32.535 ;
     RECT  2.16 32.805 41.04 33.075 ;
     RECT  2.16 33.345 41.04 33.615 ;
     RECT  2.16 33.885 41.04 34.155 ;
     RECT  2.16 34.425 41.04 34.695 ;
     RECT  2.16 34.965 41.04 35.235 ;
     RECT  2.16 35.505 41.04 35.775 ;
     RECT  2.16 36.045 41.04 36.315 ;
     RECT  2.16 36.585 41.04 36.855 ;
     RECT  2.16 37.125 41.04 37.395 ;
     RECT  2.16 37.665 41.04 37.935 ;
     RECT  2.16 38.205 41.04 38.475 ;
     RECT  2.16 38.745 41.04 39.015 ;
     RECT  2.16 39.285 41.04 39.555 ;
     RECT  2.16 39.825 41.04 40.095 ;
     RECT  2.16 40.365 41.04 40.635 ;
     RECT  2.16 40.905 41.04 41.175 ;
     RECT  2.16 41.445 41.04 41.715 ;
     RECT  2.16 41.985 41.04 42.255 ;
     RECT  2.16 42.525 41.04 42.795 ;
     RECT  2.16 43.065 41.04 43.335 ;
     RECT  2.16 43.605 41.04 43.875 ;
     RECT  2.16 44.145 41.04 44.415 ;
     RECT  2.16 44.685 41.04 44.955 ;
     RECT  2.16 45.225 41.04 45.495 ;
     RECT  2.16 45.765 41.04 46.035 ;
     RECT  2.16 46.305 41.04 46.575 ;
     RECT  2.16 46.845 41.04 47.115 ;
     RECT  2.16 47.385 41.04 47.655 ;
     RECT  2.16 47.925 41.04 48.195 ;
     RECT  2.16 48.465 41.04 48.735 ;
     RECT  2.16 49.005 41.04 49.275 ;
     RECT  2.16 49.545 41.04 49.815 ;
     RECT  2.16 50.085 41.04 50.355 ;
     RECT  2.16 50.625 41.04 50.895 ;
     RECT  2.16 51.165 41.04 51.435 ;
     RECT  2.16 51.705 41.04 51.975 ;
     RECT  2.16 52.245 41.04 52.515 ;
     RECT  2.16 52.785 41.04 53.055 ;
     RECT  2.16 53.325 41.04 53.595 ;
     RECT  2.16 53.865 41.04 54.135 ;
     RECT  2.16 54.405 41.04 54.675 ;
     RECT  2.16 54.945 41.04 55.215 ;
     RECT  2.16 55.485 41.04 55.755 ;
     RECT  2.16 56.025 41.04 56.295 ;
     RECT  2.16 56.565 41.04 56.835 ;
     RECT  2.16 57.105 41.04 57.375 ;
     RECT  2.16 57.645 41.04 57.915 ;
     RECT  2.16 58.185 41.04 58.455 ;
     RECT  2.16 58.725 41.04 58.995 ;
     RECT  2.16 59.265 41.04 59.535 ;
     RECT  2.16 59.805 41.04 60.075 ;
     RECT  2.16 60.345 41.04 60.615 ;
     RECT  2.16 60.885 41.04 61.155 ;
     RECT  2.16 61.425 41.04 61.695 ;
     RECT  2.16 61.965 41.04 62.235 ;
     RECT  2.16 62.505 41.04 62.775 ;
     RECT  2.16 63.045 41.04 63.315 ;
     RECT  2.16 63.585 41.04 63.855 ;
     RECT  2.16 64.125 41.04 64.395 ;
     RECT  2.16 64.665 41.04 64.935 ;
     RECT  2.16 65.205 41.04 65.475 ;
     RECT  2.16 65.745 41.04 66.015 ;
     RECT  2.16 66.285 41.04 66.555 ;
     RECT  2.16 66.825 41.04 67.095 ;
     RECT  2.16 67.365 41.04 67.635 ;
     RECT  2.16 67.905 41.04 68.175 ;
     RECT  2.16 68.445 41.04 68.715 ;
     RECT  2.16 68.985 41.04 69.255 ;
     RECT  2.16 69.525 41.04 69.795 ;
     RECT  2.16 70.065 41.04 70.335 ;
     RECT  2.16 70.605 41.04 70.875 ;
     RECT  2.16 71.145 41.04 71.415 ;
     RECT  2.16 71.685 41.04 71.955 ;
     RECT  2.16 72.225 41.04 72.495 ;
     RECT  2.16 72.765 41.04 73.035 ;
     RECT  2.16 73.305 41.04 73.575 ;
     RECT  2.16 73.845 41.04 74.115 ;
     RECT  2.16 74.385 41.04 74.655 ;
     RECT  2.16 74.925 41.04 75.195 ;
     RECT  2.16 75.465 41.04 75.735 ;
     RECT  2.16 76.005 41.04 76.275 ;
     RECT  2.16 76.545 41.04 76.815 ;
     RECT  2.16 77.085 41.04 77.355 ;
     RECT  2.16 77.625 41.04 77.895 ;
     RECT  2.16 78.165 41.04 78.435 ;
     RECT  2.16 78.705 41.04 78.975 ;
     RECT  2.16 79.245 41.04 79.515 ;
     RECT  2.16 79.785 41.04 80.055 ;
     RECT  2.16 80.325 41.04 80.595 ;
     RECT  2.16 80.865 41.04 81.135 ;
     RECT  2.16 81.405 41.04 81.675 ;
     RECT  2.16 81.945 41.04 82.215 ;
     RECT  2.16 82.485 41.04 82.755 ;
     RECT  2.16 83.025 41.04 83.295 ;
     RECT  2.16 83.565 41.04 83.835 ;
     RECT  2.16 84.105 41.04 84.375 ;
     RECT  2.16 84.645 41.04 84.915 ;
     RECT  2.16 85.185 41.04 85.455 ;
     RECT  2.16 85.725 41.04 85.995 ;
     RECT  2.16 86.265 41.04 86.535 ;
     RECT  2.16 86.805 41.04 87.075 ;
     RECT  2.16 87.345 41.04 87.615 ;
     RECT  2.16 87.885 41.04 88.155 ;
     RECT  2.16 88.425 41.04 88.695 ;
     RECT  2.16 88.965 41.04 89.235 ;
     RECT  2.16 89.505 41.04 89.775 ;
     RECT  2.16 90.045 41.04 90.315 ;
     RECT  2.16 90.585 41.04 90.855 ;
     RECT  2.16 91.125 41.04 91.395 ;
     RECT  2.16 91.665 41.04 91.935 ;
     RECT  2.16 92.205 41.04 92.475 ;
     RECT  2.16 92.745 41.04 93.015 ;
     RECT  2.16 93.285 41.04 93.555 ;
     RECT  2.16 93.825 41.04 94.095 ;
     RECT  2.16 94.365 41.04 94.635 ;
     RECT  2.16 94.905 41.04 95.175 ;
     RECT  2.16 95.445 41.04 95.715 ;
     RECT  2.16 95.985 41.04 96.255 ;
     RECT  2.16 96.525 41.04 96.795 ;
     RECT  2.16 97.065 41.04 97.335 ;
     RECT  2.16 97.605 41.04 97.875 ;
     RECT  2.16 98.145 41.04 98.415 ;
     RECT  2.16 98.685 41.04 98.955 ;
     RECT  2.16 99.225 41.04 99.495 ;
     RECT  2.16 99.765 41.04 100.035 ;
     RECT  2.16 100.305 41.04 100.575 ;
     RECT  2.16 100.845 41.04 101.115 ;
     RECT  2.16 101.385 41.04 101.655 ;
     RECT  2.16 101.925 41.04 102.195 ;
     RECT  2.16 102.465 41.04 102.735 ;
     RECT  2.16 103.005 41.04 103.275 ;
     RECT  2.16 103.545 41.04 103.815 ;
     RECT  2.16 104.085 41.04 104.355 ;
     RECT  2.16 104.625 41.04 104.895 ;
     RECT  2.16 105.165 41.04 105.435 ;
     RECT  2.16 105.705 41.04 105.84 ;
    LAYER RVTP ;
     RECT  2.16 2.295 41.04 2.565 ;
     RECT  2.16 2.835 41.04 3.105 ;
     RECT  2.16 3.375 41.04 3.645 ;
     RECT  2.16 3.915 41.04 4.185 ;
     RECT  2.16 4.455 41.04 4.725 ;
     RECT  2.16 4.995 41.04 5.265 ;
     RECT  2.16 5.535 41.04 5.805 ;
     RECT  2.16 6.075 41.04 6.345 ;
     RECT  2.16 6.615 41.04 6.885 ;
     RECT  2.16 7.155 41.04 7.425 ;
     RECT  2.16 7.695 41.04 7.965 ;
     RECT  2.16 8.235 41.04 8.505 ;
     RECT  2.16 8.775 41.04 9.045 ;
     RECT  2.16 9.315 41.04 9.585 ;
     RECT  2.16 9.855 41.04 10.125 ;
     RECT  2.16 10.395 41.04 10.665 ;
     RECT  2.16 10.935 41.04 11.205 ;
     RECT  2.16 11.475 41.04 11.745 ;
     RECT  2.16 12.015 41.04 12.285 ;
     RECT  2.16 12.555 41.04 12.825 ;
     RECT  2.16 13.095 41.04 13.365 ;
     RECT  2.16 13.635 41.04 13.905 ;
     RECT  2.16 14.175 41.04 14.445 ;
     RECT  2.16 14.715 41.04 14.985 ;
     RECT  2.16 15.255 41.04 15.525 ;
     RECT  2.16 15.795 41.04 16.065 ;
     RECT  2.16 16.335 41.04 16.605 ;
     RECT  2.16 16.875 41.04 17.145 ;
     RECT  2.16 17.415 41.04 17.685 ;
     RECT  2.16 17.955 41.04 18.225 ;
     RECT  2.16 18.495 41.04 18.765 ;
     RECT  2.16 19.035 41.04 19.305 ;
     RECT  2.16 19.575 41.04 19.845 ;
     RECT  2.16 20.115 41.04 20.385 ;
     RECT  2.16 20.655 41.04 20.925 ;
     RECT  2.16 21.195 41.04 21.465 ;
     RECT  2.16 21.735 41.04 22.005 ;
     RECT  2.16 22.275 41.04 22.545 ;
     RECT  2.16 22.815 41.04 23.085 ;
     RECT  2.16 23.355 41.04 23.625 ;
     RECT  2.16 23.895 41.04 24.165 ;
     RECT  2.16 24.435 41.04 24.705 ;
     RECT  2.16 24.975 41.04 25.245 ;
     RECT  2.16 25.515 41.04 25.785 ;
     RECT  2.16 26.055 41.04 26.325 ;
     RECT  2.16 26.595 41.04 26.865 ;
     RECT  2.16 27.135 41.04 27.405 ;
     RECT  2.16 27.675 41.04 27.945 ;
     RECT  2.16 28.215 41.04 28.485 ;
     RECT  2.16 28.755 41.04 29.025 ;
     RECT  2.16 29.295 41.04 29.565 ;
     RECT  2.16 29.835 41.04 30.105 ;
     RECT  2.16 30.375 41.04 30.645 ;
     RECT  2.16 30.915 41.04 31.185 ;
     RECT  2.16 31.455 41.04 31.725 ;
     RECT  2.16 31.995 41.04 32.265 ;
     RECT  2.16 32.535 41.04 32.805 ;
     RECT  2.16 33.075 41.04 33.345 ;
     RECT  2.16 33.615 41.04 33.885 ;
     RECT  2.16 34.155 41.04 34.425 ;
     RECT  2.16 34.695 41.04 34.965 ;
     RECT  2.16 35.235 41.04 35.505 ;
     RECT  2.16 35.775 41.04 36.045 ;
     RECT  2.16 36.315 41.04 36.585 ;
     RECT  2.16 36.855 41.04 37.125 ;
     RECT  2.16 37.395 41.04 37.665 ;
     RECT  2.16 37.935 41.04 38.205 ;
     RECT  2.16 38.475 41.04 38.745 ;
     RECT  2.16 39.015 41.04 39.285 ;
     RECT  2.16 39.555 41.04 39.825 ;
     RECT  2.16 40.095 41.04 40.365 ;
     RECT  2.16 40.635 41.04 40.905 ;
     RECT  2.16 41.175 41.04 41.445 ;
     RECT  2.16 41.715 41.04 41.985 ;
     RECT  2.16 42.255 41.04 42.525 ;
     RECT  2.16 42.795 41.04 43.065 ;
     RECT  2.16 43.335 41.04 43.605 ;
     RECT  2.16 43.875 41.04 44.145 ;
     RECT  2.16 44.415 41.04 44.685 ;
     RECT  2.16 44.955 41.04 45.225 ;
     RECT  2.16 45.495 41.04 45.765 ;
     RECT  2.16 46.035 41.04 46.305 ;
     RECT  2.16 46.575 41.04 46.845 ;
     RECT  2.16 47.115 41.04 47.385 ;
     RECT  2.16 47.655 41.04 47.925 ;
     RECT  2.16 48.195 41.04 48.465 ;
     RECT  2.16 48.735 41.04 49.005 ;
     RECT  2.16 49.275 41.04 49.545 ;
     RECT  2.16 49.815 41.04 50.085 ;
     RECT  2.16 50.355 41.04 50.625 ;
     RECT  2.16 50.895 41.04 51.165 ;
     RECT  2.16 51.435 41.04 51.705 ;
     RECT  2.16 51.975 41.04 52.245 ;
     RECT  2.16 52.515 41.04 52.785 ;
     RECT  2.16 53.055 41.04 53.325 ;
     RECT  2.16 53.595 41.04 53.865 ;
     RECT  2.16 54.135 41.04 54.405 ;
     RECT  2.16 54.675 41.04 54.945 ;
     RECT  2.16 55.215 41.04 55.485 ;
     RECT  2.16 55.755 41.04 56.025 ;
     RECT  2.16 56.295 41.04 56.565 ;
     RECT  2.16 56.835 41.04 57.105 ;
     RECT  2.16 57.375 41.04 57.645 ;
     RECT  2.16 57.915 41.04 58.185 ;
     RECT  2.16 58.455 41.04 58.725 ;
     RECT  2.16 58.995 41.04 59.265 ;
     RECT  2.16 59.535 41.04 59.805 ;
     RECT  2.16 60.075 41.04 60.345 ;
     RECT  2.16 60.615 41.04 60.885 ;
     RECT  2.16 61.155 41.04 61.425 ;
     RECT  2.16 61.695 41.04 61.965 ;
     RECT  2.16 62.235 41.04 62.505 ;
     RECT  2.16 62.775 41.04 63.045 ;
     RECT  2.16 63.315 41.04 63.585 ;
     RECT  2.16 63.855 41.04 64.125 ;
     RECT  2.16 64.395 41.04 64.665 ;
     RECT  2.16 64.935 41.04 65.205 ;
     RECT  2.16 65.475 41.04 65.745 ;
     RECT  2.16 66.015 41.04 66.285 ;
     RECT  2.16 66.555 41.04 66.825 ;
     RECT  2.16 67.095 41.04 67.365 ;
     RECT  2.16 67.635 41.04 67.905 ;
     RECT  2.16 68.175 41.04 68.445 ;
     RECT  2.16 68.715 41.04 68.985 ;
     RECT  2.16 69.255 41.04 69.525 ;
     RECT  2.16 69.795 41.04 70.065 ;
     RECT  2.16 70.335 41.04 70.605 ;
     RECT  2.16 70.875 41.04 71.145 ;
     RECT  2.16 71.415 41.04 71.685 ;
     RECT  2.16 71.955 41.04 72.225 ;
     RECT  2.16 72.495 41.04 72.765 ;
     RECT  2.16 73.035 41.04 73.305 ;
     RECT  2.16 73.575 41.04 73.845 ;
     RECT  2.16 74.115 41.04 74.385 ;
     RECT  2.16 74.655 41.04 74.925 ;
     RECT  2.16 75.195 41.04 75.465 ;
     RECT  2.16 75.735 41.04 76.005 ;
     RECT  2.16 76.275 41.04 76.545 ;
     RECT  2.16 76.815 41.04 77.085 ;
     RECT  2.16 77.355 41.04 77.625 ;
     RECT  2.16 77.895 41.04 78.165 ;
     RECT  2.16 78.435 41.04 78.705 ;
     RECT  2.16 78.975 41.04 79.245 ;
     RECT  2.16 79.515 41.04 79.785 ;
     RECT  2.16 80.055 41.04 80.325 ;
     RECT  2.16 80.595 41.04 80.865 ;
     RECT  2.16 81.135 41.04 81.405 ;
     RECT  2.16 81.675 41.04 81.945 ;
     RECT  2.16 82.215 41.04 82.485 ;
     RECT  2.16 82.755 41.04 83.025 ;
     RECT  2.16 83.295 41.04 83.565 ;
     RECT  2.16 83.835 41.04 84.105 ;
     RECT  2.16 84.375 41.04 84.645 ;
     RECT  2.16 84.915 41.04 85.185 ;
     RECT  2.16 85.455 41.04 85.725 ;
     RECT  2.16 85.995 41.04 86.265 ;
     RECT  2.16 86.535 41.04 86.805 ;
     RECT  2.16 87.075 41.04 87.345 ;
     RECT  2.16 87.615 41.04 87.885 ;
     RECT  2.16 88.155 41.04 88.425 ;
     RECT  2.16 88.695 41.04 88.965 ;
     RECT  2.16 89.235 41.04 89.505 ;
     RECT  2.16 89.775 41.04 90.045 ;
     RECT  2.16 90.315 41.04 90.585 ;
     RECT  2.16 90.855 41.04 91.125 ;
     RECT  2.16 91.395 41.04 91.665 ;
     RECT  2.16 91.935 41.04 92.205 ;
     RECT  2.16 92.475 41.04 92.745 ;
     RECT  2.16 93.015 41.04 93.285 ;
     RECT  2.16 93.555 41.04 93.825 ;
     RECT  2.16 94.095 41.04 94.365 ;
     RECT  2.16 94.635 41.04 94.905 ;
     RECT  2.16 95.175 41.04 95.445 ;
     RECT  2.16 95.715 41.04 95.985 ;
     RECT  2.16 96.255 41.04 96.525 ;
     RECT  2.16 96.795 41.04 97.065 ;
     RECT  2.16 97.335 41.04 97.605 ;
     RECT  2.16 97.875 41.04 98.145 ;
     RECT  2.16 98.415 41.04 98.685 ;
     RECT  2.16 98.955 41.04 99.225 ;
     RECT  2.16 99.495 41.04 99.765 ;
     RECT  2.16 100.035 41.04 100.305 ;
     RECT  2.16 100.575 41.04 100.845 ;
     RECT  2.16 101.115 41.04 101.385 ;
     RECT  2.16 101.655 41.04 101.925 ;
     RECT  2.16 102.195 41.04 102.465 ;
     RECT  2.16 102.735 41.04 103.005 ;
     RECT  2.16 103.275 41.04 103.545 ;
     RECT  2.16 103.815 41.04 104.085 ;
     RECT  2.16 104.355 41.04 104.625 ;
     RECT  2.16 104.895 41.04 105.165 ;
     RECT  2.16 105.435 41.04 105.705 ;
    LAYER M1 ;
     RECT  2.16 2.151 41.04 105.849 ;
    LAYER M2 ;
     RECT  0.031 69.921 0.067 69.939 ;
     RECT  0.067 48.006 0.103 48.024 ;
     RECT  0.067 60.894 0.103 60.912 ;
     RECT  0.031 78.444 0.103 78.462 ;
     RECT  0.031 80.568 0.103 80.586 ;
     RECT  0.067 69.876 0.131 69.939 ;
     RECT  0.103 79.992 0.131 80.586 ;
     RECT  0.103 59.04 0.139 59.058 ;
     RECT  0.131 69.876 0.139 69.894 ;
     RECT  0.103 73.512 0.139 74.106 ;
     RECT  0.067 37.908 0.167 37.926 ;
     RECT  0.139 59.04 0.175 59.526 ;
     RECT  0.103 60.39 0.175 60.912 ;
     RECT  0.103 65.016 0.175 65.736 ;
     RECT  0.139 73.35 0.175 74.106 ;
     RECT  0.067 74.898 0.175 74.916 ;
     RECT  0.103 77.598 0.175 77.616 ;
     RECT  0.103 82.8 0.175 82.818 ;
     RECT  0.139 83.772 0.175 83.79 ;
     RECT  0.103 31.5 0.203 31.752 ;
     RECT  0.103 33.552 0.203 34.146 ;
     RECT  0.103 38.718 0.203 38.736 ;
     RECT  0.103 43.92 0.203 43.938 ;
     RECT  0.103 46.044 0.203 46.062 ;
     RECT  0.103 48.006 0.203 48.726 ;
     RECT  0.175 65.016 0.203 65.808 ;
     RECT  0.103 75.978 0.203 75.996 ;
     RECT  0.175 77.526 0.203 77.616 ;
     RECT  0.103 41.301 0.211 41.589 ;
     RECT  0.175 59.04 0.211 60.912 ;
     RECT  0.203 77.526 0.211 77.544 ;
     RECT  0.211 41.148 0.239 41.589 ;
     RECT  0.203 48.006 0.239 48.258 ;
     RECT  0.103 62.316 0.239 63 ;
     RECT  0.203 65.718 0.239 65.808 ;
     RECT  0.139 68.76 0.239 69.894 ;
     RECT  0.139 51.786 0.247 51.804 ;
     RECT  0.139 64.062 0.247 64.08 ;
     RECT  0.239 65.79 0.247 65.808 ;
     RECT  0.103 72 0.247 72.018 ;
     RECT  0.175 72.81 0.247 74.916 ;
     RECT  0.211 77.4 0.275 77.544 ;
     RECT  0.203 33.552 0.347 33.912 ;
     RECT  0.239 41.148 0.347 41.436 ;
     RECT  0.239 62.514 0.347 63 ;
     RECT  0.067 57.96 0.391 57.978 ;
     RECT  0.211 59.04 0.391 60.948 ;
     RECT  0.247 51.786 0.455 52.236 ;
     RECT  0.391 57.726 0.463 60.948 ;
     RECT  0.247 63.792 0.463 64.08 ;
     RECT  0.283 64.872 0.463 64.962 ;
     RECT  0.103 53.532 0.499 54.36 ;
     RECT  0.347 62.55 0.499 63 ;
     RECT  0.463 63.792 0.499 64.962 ;
     RECT  0.247 72 0.499 74.916 ;
     RECT  0.455 51.786 0.535 52.038 ;
     RECT  0.499 53.298 0.535 54.36 ;
     RECT  0.499 71.658 0.535 74.916 ;
     RECT  0.103 78.444 0.535 79.2 ;
     RECT  0.131 79.992 0.535 80.01 ;
     RECT  0.463 57.726 0.563 61.758 ;
     RECT  0.239 48.006 1.147 48.024 ;
     RECT  0.535 51.714 1.175 52.038 ;
     RECT  1.147 47.322 1.399 48.024 ;
     RECT  0.247 65.79 1.435 66.006 ;
     RECT  0.275 77.4 1.435 77.418 ;
     RECT  0.535 78.444 1.435 80.01 ;
     RECT  1.399 47.322 1.723 48.69 ;
     RECT  0.535 71.658 2.011 75.222 ;
     RECT  0.239 68.922 2.047 69.894 ;
     RECT  0.823 70.65 2.047 70.668 ;
     RECT  0.347 33.894 2.16 33.912 ;
     RECT  0.535 42.732 2.16 42.75 ;
     RECT  0.031 44.766 2.16 44.784 ;
     RECT  1.723 46.746 2.16 48.69 ;
     RECT  1.723 50.13 2.16 50.148 ;
     RECT  1.975 50.94 2.16 50.958 ;
     RECT  1.175 51.714 2.16 51.966 ;
     RECT  0.535 52.83 2.16 54.36 ;
     RECT  0.103 55.8 2.16 55.818 ;
     RECT  0.563 57.726 2.16 58.014 ;
     RECT  0.563 59.04 2.16 61.758 ;
     RECT  0.499 62.55 2.16 64.962 ;
     RECT  1.435 65.79 2.16 66.078 ;
     RECT  0.103 66.87 2.16 66.888 ;
     RECT  2.047 68.922 2.16 70.668 ;
     RECT  2.011 71.46 2.16 75.222 ;
     RECT  2.047 76.59 2.16 76.608 ;
     RECT  1.435 77.4 2.16 80.01 ;
     RECT  0.175 82.8 2.16 83.79 ;
     RECT  2.16 2.151 41.04 105.849 ;
     RECT  41.04 22.986 41.063 23.004 ;
     RECT  41.04 26.496 41.063 38.394 ;
     RECT  41.04 39.222 41.387 76.374 ;
     RECT  41.063 26.496 41.567 27.324 ;
     RECT  41.04 23.796 41.603 24.624 ;
     RECT  41.063 28.116 41.603 38.394 ;
     RECT  41.387 50.166 41.639 76.374 ;
     RECT  41.639 50.166 41.783 71.172 ;
     RECT  41.783 50.256 41.927 71.172 ;
     RECT  41.567 26.496 42.071 27.234 ;
     RECT  41.603 24.246 42.143 24.624 ;
     RECT  41.603 28.116 42.143 31.284 ;
     RECT  42.143 24.606 42.179 24.624 ;
     RECT  42.071 26.496 42.179 26.964 ;
     RECT  42.143 28.116 42.179 29.286 ;
     RECT  42.143 30.348 42.179 31.284 ;
     RECT  41.387 39.222 42.179 49.374 ;
     RECT  41.927 50.256 42.179 53.01 ;
     RECT  41.927 54.036 42.179 71.172 ;
     RECT  41.639 72.576 42.179 76.374 ;
     RECT  42.179 30.348 42.215 30.366 ;
     RECT  41.603 32.04 42.215 38.394 ;
     RECT  42.179 44.316 42.215 46.566 ;
     RECT  42.179 47.736 42.215 47.754 ;
     RECT  42.179 50.256 42.215 51.309 ;
     RECT  42.179 52.218 42.215 53.01 ;
     RECT  42.179 61.128 42.215 68.904 ;
     RECT  42.179 75.744 42.215 76.374 ;
     RECT  42.215 34.506 42.251 38.394 ;
     RECT  42.179 57.348 42.251 60.372 ;
     RECT  42.215 61.128 42.251 61.614 ;
     RECT  42.215 62.442 42.251 68.814 ;
     RECT  42.179 39.222 42.287 41.472 ;
     RECT  42.215 51.066 42.287 51.309 ;
     RECT  42.179 54.036 42.287 56.25 ;
     RECT  42.251 62.442 42.323 66.312 ;
     RECT  42.251 34.821 42.871 38.394 ;
     RECT  42.287 39.222 42.871 41.364 ;
     RECT  42.179 28.836 42.907 29.286 ;
     RECT  42.179 48.51 42.907 49.374 ;
     RECT  42.287 51.291 42.907 51.309 ;
     RECT  42.215 52.218 42.907 52.974 ;
     RECT  42.215 32.04 42.935 33.714 ;
     RECT  42.287 55.188 42.935 56.25 ;
     RECT  42.323 63.252 42.935 66.312 ;
     RECT  42.871 34.821 42.971 41.364 ;
     RECT  42.215 44.316 42.971 45.414 ;
     RECT  42.907 51.291 42.971 52.974 ;
     RECT  42.935 63.486 42.971 66.312 ;
     RECT  42.215 46.314 42.979 46.566 ;
     RECT  42.935 32.346 43.007 33.714 ;
     RECT  42.971 34.821 43.007 36.774 ;
     RECT  42.971 37.674 43.007 38.304 ;
     RECT  42.971 51.291 43.007 51.804 ;
     RECT  42.251 57.348 43.007 58.788 ;
     RECT  42.251 59.544 43.007 60.372 ;
     RECT  42.971 63.828 43.007 66.312 ;
     RECT  42.179 26.946 43.015 26.964 ;
     RECT  43.007 34.821 43.015 35.226 ;
     RECT  42.971 52.758 43.015 52.974 ;
     RECT  42.287 54.036 43.015 54.324 ;
     RECT  42.935 56.232 43.015 56.25 ;
     RECT  43.007 36.486 43.043 36.774 ;
     RECT  42.179 42.426 43.043 43.326 ;
     RECT  42.971 44.316 43.043 44.478 ;
     RECT  43.015 52.758 43.043 54.324 ;
     RECT  42.251 67.176 43.043 68.814 ;
     RECT  42.907 28.764 43.051 29.286 ;
     RECT  42.979 46.314 43.051 46.719 ;
     RECT  43.051 28.764 43.079 30.024 ;
     RECT  42.179 31.266 43.079 31.284 ;
     RECT  43.007 32.346 43.079 32.364 ;
     RECT  43.007 33.354 43.079 33.714 ;
     RECT  43.015 34.74 43.079 35.226 ;
     RECT  43.043 36.558 43.079 36.774 ;
     RECT  43.007 38.286 43.079 38.304 ;
     RECT  42.971 39.141 43.079 41.364 ;
     RECT  43.043 42.732 43.079 43.326 ;
     RECT  42.971 45.306 43.079 45.414 ;
     RECT  42.907 48.51 43.079 49.419 ;
     RECT  42.935 55.188 43.079 55.314 ;
     RECT  43.007 57.348 43.079 58.14 ;
     RECT  43.007 60.048 43.079 60.372 ;
     RECT  43.007 63.828 43.079 65.538 ;
     RECT  43.043 67.176 43.079 67.734 ;
     RECT  43.043 68.49 43.079 68.814 ;
     RECT  43.015 26.946 43.115 27.234 ;
     RECT  43.079 36.558 43.115 36.576 ;
     RECT  43.079 39.141 43.115 40.464 ;
     RECT  43.079 41.346 43.115 41.364 ;
     RECT  43.079 43.146 43.115 43.326 ;
     RECT  43.043 44.316 43.115 44.334 ;
     RECT  43.079 45.306 43.115 45.324 ;
     RECT  43.079 49.176 43.115 49.419 ;
     RECT  42.215 50.256 43.115 50.274 ;
     RECT  43.043 52.758 43.115 54.09 ;
     RECT  43.079 55.296 43.115 55.314 ;
     RECT  43.015 56.232 43.115 56.394 ;
     RECT  43.079 57.384 43.115 57.87 ;
     RECT  42.251 61.128 43.115 61.524 ;
     RECT  43.079 64.476 43.115 65.538 ;
     RECT  43.007 66.294 43.115 66.312 ;
     RECT  43.079 67.536 43.115 67.734 ;
     RECT  42.179 69.696 43.115 69.984 ;
     RECT  42.179 72.774 43.115 73.944 ;
     RECT  42.179 74.862 43.115 74.88 ;
     RECT  42.215 76.356 43.115 76.374 ;
     RECT  43.079 34.74 43.151 34.758 ;
     RECT  43.115 40.446 43.151 40.464 ;
     RECT  43.051 46.314 43.151 46.764 ;
     RECT  43.115 52.758 43.151 52.776 ;
     RECT  43.115 61.128 43.151 61.146 ;
     RECT  43.115 64.638 43.151 64.656 ;
     RECT  43.115 65.52 43.151 65.538 ;
     RECT  43.079 68.49 43.151 68.508 ;
     RECT  43.079 30.006 43.187 30.024 ;
     RECT  43.151 46.314 43.187 46.332 ;
     RECT  43.007 51.291 43.187 51.309 ;
     RECT  43.079 60.048 43.187 60.066 ;
     RECT  42.323 62.442 43.187 62.46 ;
     RECT  43.115 67.536 43.187 67.554 ;
    LAYER M3 ;
     RECT  26.712 1.723 26.73 2.255 ;
     RECT  2.415 2.143 2.505 2.413 ;
     RECT  7.815 2.143 7.905 2.413 ;
     RECT  13.215 2.143 13.305 2.413 ;
     RECT  18.615 2.143 18.705 2.413 ;
     RECT  24.015 2.143 24.105 2.413 ;
     RECT  29.415 2.143 29.505 2.413 ;
     RECT  34.815 2.143 34.905 2.413 ;
     RECT  40.215 2.143 40.305 2.413 ;
     RECT  26.784 2.371 26.802 2.795 ;
     RECT  26.856 2.803 26.874 5.531 ;
     RECT  26.748 5.611 26.766 9.275 ;
     RECT  25.38 11.947 25.398 12.865 ;
     RECT  26.496 9.391 26.514 12.865 ;
     RECT  25.38 12.865 26.622 13.051 ;
     RECT  25.344 13.051 26.622 13.091 ;
     RECT  25.776 13.091 26.622 13.171 ;
     RECT  25.776 13.171 26.658 13.531 ;
     RECT  25.776 13.531 27.09 13.667 ;
     RECT  26.604 13.667 27.09 13.703 ;
     RECT  27.072 13.703 27.09 19.229 ;
     RECT  40.215 2.413 40.497 22.981 ;
     RECT  40.215 22.981 41.058 23.021 ;
     RECT  38.664 23.083 38.682 23.371 ;
     RECT  41.58 23.275 41.598 23.467 ;
     RECT  41.58 23.467 41.886 23.563 ;
     RECT  40.215 23.021 40.497 23.659 ;
     RECT  41.58 23.563 42.066 23.819 ;
     RECT  29.415 2.413 29.697 23.827 ;
     RECT  41.832 23.819 42.066 23.885 ;
     RECT  41.868 23.885 42.066 23.947 ;
     RECT  38.664 23.371 38.754 24.187 ;
     RECT  39.672 23.659 40.497 24.187 ;
     RECT  38.664 24.187 40.518 24.241 ;
     RECT  38.412 24.241 40.518 24.359 ;
     RECT  19.62 23.017 19.638 24.367 ;
     RECT  38.664 24.359 40.518 24.461 ;
     RECT  41.868 23.947 42.174 24.629 ;
     RECT  4.86 25.447 4.878 25.979 ;
     RECT  41.868 24.629 42.066 26.155 ;
     RECT  43.056 24.043 43.074 26.443 ;
     RECT  34.815 2.413 35.097 26.491 ;
     RECT  41.868 26.155 42.174 26.539 ;
     RECT  43.02 26.443 43.074 26.635 ;
     RECT  11.988 24.637 12.006 26.797 ;
     RECT  41.58 26.539 42.174 26.861 ;
     RECT  7.815 2.413 8.097 26.869 ;
     RECT  38.664 24.461 40.497 26.905 ;
     RECT  41.58 26.861 42.066 26.923 ;
     RECT  29.415 23.827 29.898 26.941 ;
     RECT  41.544 26.923 42.066 27.019 ;
     RECT  28.8 26.941 29.898 27.059 ;
     RECT  27.288 19.345 27.306 27.103 ;
     RECT  38.52 26.905 40.497 27.115 ;
     RECT  34.815 26.491 35.55 27.139 ;
     RECT  37.404 26.347 37.422 27.139 ;
     RECT  38.52 27.115 40.59 27.139 ;
     RECT  37.404 27.139 40.59 27.163 ;
     RECT  18.615 2.413 18.897 27.175 ;
     RECT  19.62 24.367 19.998 27.175 ;
     RECT  28.656 27.103 28.674 27.175 ;
     RECT  26.856 27.103 27.306 27.203 ;
     RECT  28.512 27.175 28.674 27.203 ;
     RECT  34.776 27.139 35.55 27.239 ;
     RECT  43.02 26.635 43.11 27.239 ;
     RECT  43.056 27.239 43.11 27.248 ;
     RECT  11.988 26.797 12.114 27.301 ;
     RECT  37.368 27.163 40.59 27.595 ;
     RECT  41.508 27.019 42.066 27.595 ;
     RECT  37.368 27.595 42.066 27.787 ;
     RECT  43.056 27.248 43.074 28.075 ;
     RECT  37.368 27.787 42.174 28.139 ;
     RECT  7.236 26.869 8.097 28.183 ;
     RECT  24.015 2.413 24.297 28.219 ;
     RECT  37.368 28.139 42.03 28.411 ;
     RECT  43.056 28.075 43.11 28.759 ;
     RECT  13.215 2.413 13.497 28.921 ;
     RECT  34.056 28.699 34.074 28.921 ;
     RECT  34.815 27.239 35.55 28.921 ;
     RECT  36.828 28.411 42.03 29.035 ;
     RECT  34.056 28.921 35.55 29.057 ;
     RECT  34.815 29.057 35.55 29.227 ;
     RECT  34.815 29.227 36.054 29.489 ;
     RECT  21.132 26.527 21.15 29.569 ;
     RECT  36.828 29.035 42.174 29.839 ;
     RECT  13.215 28.921 13.662 30.001 ;
     RECT  42.912 28.759 43.11 30.001 ;
     RECT  36.504 29.839 42.174 30.029 ;
     RECT  22.536 24.403 22.554 30.037 ;
     RECT  36.648 30.029 42.174 30.179 ;
     RECT  36.828 30.179 42.174 30.187 ;
     RECT  42.912 30.001 43.182 30.187 ;
     RECT  21.132 29.569 21.51 30.307 ;
     RECT  36.828 30.187 43.182 30.371 ;
     RECT  18.615 27.175 19.998 30.847 ;
     RECT  20.952 30.307 21.51 30.847 ;
     RECT  36.828 30.371 42.174 30.875 ;
     RECT  36.828 30.875 42.138 30.947 ;
     RECT  34.815 29.489 35.55 31.189 ;
     RECT  4.536 26.131 4.554 31.225 ;
     RECT  2.415 2.413 2.697 31.243 ;
     RECT  7.236 28.183 8.442 31.243 ;
     RECT  2.304 31.243 2.697 31.289 ;
     RECT  31.428 26.905 31.446 31.351 ;
     RECT  0.108 31.339 0.126 31.387 ;
     RECT  11.556 27.301 12.114 31.387 ;
     RECT  13.14 30.001 13.662 31.435 ;
     RECT  11.412 31.387 12.114 31.483 ;
     RECT  36.828 30.947 42.03 31.495 ;
     RECT  32.688 30.091 32.706 31.621 ;
     RECT  15.192 31.693 15.21 31.723 ;
     RECT  10.836 31.483 12.114 31.757 ;
     RECT  34.815 31.189 35.874 31.765 ;
     RECT  36.72 31.495 42.03 31.765 ;
     RECT  15.048 31.723 15.21 31.793 ;
     RECT  32.58 31.621 32.706 31.801 ;
     RECT  0.108 31.387 0.198 31.805 ;
     RECT  0.108 31.805 0.126 31.853 ;
     RECT  32.58 31.801 33.138 31.891 ;
     RECT  7.092 31.243 8.442 31.915 ;
     RECT  15.12 31.793 15.21 31.919 ;
     RECT  6.84 31.915 8.442 31.963 ;
     RECT  9.216 27.337 9.234 31.963 ;
     RECT  13.104 31.435 13.662 31.999 ;
     RECT  16.38 27.211 16.398 32.011 ;
     RECT  34.815 31.765 42.03 32.011 ;
     RECT  2.415 31.289 2.697 32.059 ;
     RECT  42.912 30.371 43.182 32.063 ;
     RECT  10.872 31.757 12.114 32.071 ;
     RECT  13.104 31.999 13.806 32.071 ;
     RECT  34.056 29.057 34.074 32.071 ;
     RECT  34.815 32.011 42.174 32.071 ;
     RECT  2.415 32.059 2.79 32.099 ;
     RECT  15.408 32.011 16.398 32.197 ;
     RECT  24.015 28.219 24.858 32.233 ;
     RECT  25.668 27.877 25.686 32.233 ;
     RECT  15.408 32.197 16.974 32.269 ;
     RECT  18.615 30.847 21.51 32.269 ;
     RECT  10.872 32.071 13.806 32.341 ;
     RECT  15.408 32.269 21.51 32.369 ;
     RECT  2.415 32.099 2.697 32.395 ;
     RECT  15.408 32.369 16.398 32.495 ;
     RECT  24.015 32.233 25.686 32.531 ;
     RECT  34.056 32.071 42.174 32.779 ;
     RECT  31.068 31.351 31.446 32.809 ;
     RECT  10.872 32.341 14.202 32.845 ;
     RECT  14.94 32.827 14.958 32.845 ;
     RECT  10.872 32.845 14.958 32.875 ;
     RECT  42.984 32.063 43.182 32.875 ;
     RECT  6.84 31.963 9.234 32.881 ;
     RECT  30.96 32.809 31.446 32.881 ;
     RECT  32.4 31.891 33.138 32.881 ;
     RECT  28.512 27.203 28.53 32.971 ;
     RECT  6.84 32.881 9.306 32.999 ;
     RECT  2.304 32.395 2.697 33.008 ;
     RECT  6.84 32.999 9.234 33.035 ;
     RECT  10.836 32.875 14.958 33.035 ;
     RECT  10.836 33.035 14.814 33.053 ;
     RECT  11.412 33.053 14.814 33.071 ;
     RECT  27.288 27.203 27.306 33.151 ;
     RECT  30.96 32.881 33.138 33.151 ;
     RECT  34.056 32.779 42.21 33.151 ;
     RECT  26.784 33.151 27.306 33.313 ;
     RECT  0.144 33.163 0.162 33.355 ;
     RECT  0.144 33.355 0.342 33.451 ;
     RECT  0.144 33.451 0.378 33.547 ;
     RECT  2.415 33.008 2.697 33.547 ;
     RECT  3.78 33.355 3.798 33.547 ;
     RECT  0.108 33.547 0.378 33.581 ;
     RECT  26.604 33.313 27.306 33.583 ;
     RECT  28.368 32.971 28.53 33.583 ;
     RECT  24.015 32.531 24.858 33.853 ;
     RECT  25.668 32.531 25.686 33.853 ;
     RECT  26.604 33.583 28.53 33.925 ;
     RECT  17.64 32.369 21.51 33.961 ;
     RECT  0.108 33.581 0.27 34.109 ;
     RECT  2.415 33.547 3.798 34.123 ;
     RECT  4.536 31.225 5.274 34.123 ;
     RECT  30.96 33.151 42.21 34.219 ;
     RECT  42.948 32.875 43.182 34.219 ;
     RECT  11.412 33.071 14.778 34.321 ;
     RECT  0.108 34.109 0.198 34.349 ;
     RECT  2.415 34.123 5.274 34.363 ;
     RECT  0.144 34.349 0.198 34.397 ;
     RECT  29.415 27.059 29.898 34.501 ;
     RECT  2.415 34.363 5.454 34.507 ;
     RECT  15.948 32.495 16.398 34.663 ;
     RECT  17.64 33.961 21.618 34.663 ;
     RECT  2.304 34.507 5.454 34.735 ;
     RECT  29.415 34.501 30.006 34.735 ;
     RECT  30.96 34.219 43.182 34.735 ;
     RECT  7.092 33.035 9.234 34.771 ;
     RECT  15.948 34.663 21.618 34.799 ;
     RECT  7.092 34.771 9.342 34.861 ;
     RECT  7.092 34.861 9.954 34.891 ;
     RECT  2.304 34.735 5.742 34.925 ;
     RECT  10.836 34.321 14.778 34.933 ;
     RECT  6.876 34.891 9.954 34.997 ;
     RECT  24.015 33.853 25.686 35.041 ;
     RECT  6.876 34.997 9.774 35.069 ;
     RECT  10.8 34.933 14.778 35.069 ;
     RECT  23.436 35.041 25.686 35.159 ;
     RECT  11.016 35.069 14.778 35.239 ;
     RECT  17.172 34.799 21.618 35.275 ;
     RECT  22.428 30.037 22.554 35.275 ;
     RECT  6.876 35.069 9.522 35.309 ;
     RECT  2.304 34.925 3.798 35.609 ;
     RECT  0.144 34.397 0.162 35.837 ;
     RECT  11.016 35.239 14.85 35.947 ;
     RECT  7.092 35.309 9.522 36.005 ;
     RECT  10.836 35.947 14.85 36.013 ;
     RECT  10.836 36.013 14.886 36.043 ;
     RECT  15.948 34.799 16.398 36.043 ;
     RECT  10.836 36.043 16.398 36.211 ;
     RECT  0.324 36.139 0.342 36.269 ;
     RECT  2.34 35.609 3.798 36.523 ;
     RECT  4.536 34.925 5.742 36.523 ;
     RECT  2.34 36.523 5.742 36.715 ;
     RECT  7.308 36.005 9.522 36.751 ;
     RECT  17.172 35.275 22.554 36.751 ;
     RECT  6.948 36.751 9.522 36.787 ;
     RECT  17.172 36.751 22.842 36.787 ;
     RECT  2.304 36.715 5.742 36.811 ;
     RECT  1.98 36.811 5.742 36.859 ;
     RECT  6.912 36.787 9.522 36.859 ;
     RECT  10.764 36.211 16.398 36.859 ;
     RECT  17.172 36.787 22.914 36.887 ;
     RECT  10.728 36.859 16.398 36.895 ;
     RECT  17.172 36.887 22.554 36.895 ;
     RECT  10.728 36.895 22.554 36.959 ;
     RECT  0.144 36.859 0.162 37.037 ;
     RECT  1.98 36.859 9.522 37.193 ;
     RECT  10.764 36.959 22.554 37.661 ;
     RECT  12.852 37.661 22.554 37.669 ;
     RECT  24.015 35.159 25.686 37.669 ;
     RECT  26.496 33.925 28.53 37.669 ;
     RECT  24.015 37.669 28.53 37.769 ;
     RECT  0.144 37.867 0.162 37.903 ;
     RECT  1.98 37.193 3.798 38.011 ;
     RECT  4.536 37.193 9.522 38.011 ;
     RECT  1.98 38.011 9.522 38.165 ;
     RECT  12.852 37.669 22.878 38.281 ;
     RECT  12.852 38.281 22.986 38.399 ;
     RECT  29.415 34.735 43.182 38.399 ;
     RECT  0.072 37.903 0.162 38.713 ;
     RECT  1.98 38.165 9.45 38.777 ;
     RECT  0.072 38.713 0.198 38.923 ;
     RECT  10.764 37.661 12.078 39.019 ;
     RECT  12.852 38.399 15.39 39.019 ;
     RECT  10.584 39.019 15.39 39.047 ;
     RECT  0.072 38.923 0.342 39.053 ;
     RECT  6.516 38.777 9.45 39.091 ;
     RECT  0.072 39.053 0.234 39.197 ;
     RECT  10.584 39.047 14.022 39.209 ;
     RECT  16.38 38.399 22.986 39.217 ;
     RECT  6.516 39.091 9.558 39.245 ;
     RECT  14.868 39.047 15.39 39.281 ;
     RECT  14.904 39.281 15.39 39.317 ;
     RECT  29.415 38.399 42.102 39.403 ;
     RECT  42.876 38.399 43.182 39.403 ;
     RECT  16.38 39.217 23.022 39.559 ;
     RECT  24.015 37.769 25.686 39.559 ;
     RECT  16.38 39.559 25.686 39.749 ;
     RECT  1.98 38.777 5.742 39.901 ;
     RECT  6.516 39.245 9.45 39.901 ;
     RECT  16.38 39.749 21.618 40.135 ;
     RECT  0.072 39.197 0.162 40.171 ;
     RECT  1.98 39.901 9.45 40.171 ;
     RECT  10.584 39.209 12.078 40.171 ;
     RECT  12.852 39.209 14.022 40.171 ;
     RECT  22.428 39.749 25.686 40.261 ;
     RECT  26.496 37.769 28.53 40.261 ;
     RECT  1.98 40.171 14.022 40.289 ;
     RECT  12.852 40.289 14.022 40.441 ;
     RECT  14.94 39.317 15.39 40.441 ;
     RECT  0.072 40.171 0.234 40.459 ;
     RECT  12.852 40.441 15.39 40.531 ;
     RECT  16.272 40.135 21.618 40.531 ;
     RECT  12.852 40.531 21.618 40.945 ;
     RECT  0.072 40.459 0.27 41.143 ;
     RECT  1.98 40.289 12.006 41.179 ;
     RECT  12.852 40.945 21.654 41.179 ;
     RECT  22.428 40.261 28.53 41.449 ;
     RECT  29.415 39.403 43.182 41.449 ;
     RECT  0.072 41.143 0.342 41.453 ;
     RECT  1.98 41.179 21.654 41.791 ;
     RECT  22.428 41.449 43.182 41.791 ;
     RECT  0.072 41.453 0.234 41.981 ;
     RECT  0.072 41.981 0.09 42.727 ;
     RECT  0.072 42.727 0.558 42.893 ;
     RECT  1.98 41.791 43.182 42.989 ;
     RECT  1.98 42.989 42.21 43.181 ;
     RECT  1.98 43.181 42.174 43.601 ;
     RECT  0.072 42.893 0.09 43.723 ;
     RECT  0.072 43.723 0.162 43.9 ;
     RECT  0.072 43.9 0.198 44.093 ;
     RECT  1.98 43.601 42.138 44.491 ;
     RECT  42.948 42.989 43.182 44.491 ;
     RECT  0.072 44.093 0.162 44.761 ;
     RECT  1.98 44.491 43.182 44.779 ;
     RECT  1.728 44.779 43.182 44.879 ;
     RECT  1.728 44.879 42.174 45.259 ;
     RECT  1.152 45.259 42.174 45.835 ;
     RECT  0.036 44.761 0.162 46.039 ;
     RECT  42.948 44.879 43.182 46.061 ;
     RECT  0.036 46.039 0.198 46.109 ;
     RECT  1.152 45.835 42.21 46.139 ;
     RECT  42.984 46.061 43.182 46.337 ;
     RECT  42.984 46.337 43.146 46.724 ;
     RECT  43.056 46.724 43.146 46.769 ;
     RECT  0.036 46.109 0.162 46.891 ;
     RECT  0.036 46.891 0.342 47.117 ;
     RECT  1.152 46.139 42.174 47.345 ;
     RECT  1.404 47.345 42.174 47.731 ;
     RECT  1.404 47.731 42.21 47.885 ;
     RECT  43.128 46.769 43.146 48.043 ;
     RECT  42.912 48.043 43.146 48.173 ;
     RECT  0.036 47.117 0.198 48.235 ;
     RECT  1.404 47.885 42.174 48.695 ;
     RECT  1.728 48.695 42.174 48.703 ;
     RECT  1.728 48.703 42.21 48.839 ;
     RECT  43.056 48.173 43.146 49.099 ;
     RECT  0.036 48.235 0.234 49.387 ;
     RECT  0.036 49.387 0.342 49.517 ;
     RECT  42.876 49.099 43.146 49.517 ;
     RECT  1.728 48.839 41.922 49.675 ;
     RECT  1.728 49.675 42.21 50.153 ;
     RECT  0.036 49.517 0.126 50.395 ;
     RECT  1.98 50.153 42.21 50.539 ;
     RECT  42.948 49.517 43.146 50.539 ;
     RECT  0.036 50.395 0.198 50.621 ;
     RECT  1.98 50.539 43.146 50.963 ;
     RECT  2.304 50.963 43.146 51.286 ;
     RECT  1.224 51.307 1.242 51.485 ;
     RECT  0.036 50.621 0.054 51.595 ;
     RECT  2.304 51.286 43.182 51.629 ;
     RECT  0.036 51.595 0.342 51.709 ;
     RECT  1.152 51.499 1.17 51.709 ;
     RECT  42.84 51.629 43.182 51.725 ;
     RECT  42.912 51.725 43.182 51.809 ;
     RECT  0.036 51.709 1.17 52.043 ;
     RECT  42.948 51.809 43.182 52.241 ;
     RECT  2.304 51.629 41.922 52.459 ;
     RECT  2.304 52.459 42.174 52.717 ;
     RECT  2.304 52.717 42.246 53.015 ;
     RECT  0.036 52.043 0.558 53.035 ;
     RECT  0.036 53.035 0.666 53.165 ;
     RECT  0.036 53.165 0.594 53.321 ;
     RECT  0.036 53.321 0.522 53.357 ;
     RECT  42.984 52.241 43.182 53.419 ;
     RECT  42.912 53.419 43.182 53.549 ;
     RECT  2.304 53.015 41.922 53.699 ;
     RECT  42.984 53.549 43.182 54.379 ;
     RECT  0.036 53.357 0.342 54.413 ;
     RECT  2.304 53.699 41.886 54.475 ;
     RECT  0.036 54.413 0.234 54.605 ;
     RECT  2.304 54.475 42.174 54.667 ;
     RECT  42.912 54.379 43.182 54.667 ;
     RECT  2.304 54.667 43.182 55.051 ;
     RECT  2.232 55.051 43.182 55.175 ;
     RECT  2.304 55.175 43.182 55.517 ;
     RECT  0.036 54.605 0.198 55.675 ;
     RECT  0.036 55.675 0.234 55.853 ;
     RECT  42.912 55.517 43.182 55.859 ;
     RECT  2.304 55.517 41.922 56.065 ;
     RECT  2.268 56.065 41.922 56.141 ;
     RECT  42.948 55.859 43.182 56.237 ;
     RECT  2.304 56.141 41.922 56.491 ;
     RECT  0.036 55.853 0.126 56.587 ;
     RECT  0.036 56.587 0.45 57.307 ;
     RECT  2.304 56.491 42.174 57.911 ;
     RECT  2.34 57.911 42.174 57.919 ;
     RECT  2.34 57.919 42.21 58.349 ;
     RECT  42.984 56.237 43.182 58.621 ;
     RECT  2.34 58.349 41.922 58.747 ;
     RECT  2.304 58.747 41.922 59.179 ;
     RECT  42.84 58.621 43.182 59.179 ;
     RECT  0.036 57.307 0.558 59.309 ;
     RECT  2.304 59.179 43.182 60.071 ;
     RECT  2.304 60.071 43.11 60.08 ;
     RECT  0.036 59.309 0.486 60.115 ;
     RECT  2.304 60.08 43.074 60.305 ;
     RECT  0.036 60.115 0.558 60.557 ;
     RECT  2.415 60.305 43.074 60.653 ;
     RECT  2.415 60.653 42.174 60.809 ;
     RECT  2.415 60.809 41.886 61.087 ;
     RECT  42.912 60.653 43.074 61.123 ;
     RECT  2.376 61.087 41.886 61.195 ;
     RECT  42.912 61.123 43.146 61.325 ;
     RECT  0.036 60.557 0.234 61.357 ;
     RECT  2.304 61.195 41.886 61.483 ;
     RECT  2.268 61.483 41.886 61.591 ;
     RECT  0.036 61.357 0.522 61.735 ;
     RECT  43.092 61.325 43.146 61.997 ;
     RECT  2.268 61.591 42.246 62.195 ;
     RECT  43.128 61.997 43.146 62.437 ;
     RECT  2.304 62.195 42.246 62.509 ;
     RECT  2.304 62.509 42.318 63.041 ;
     RECT  0.036 61.735 0.558 63.247 ;
     RECT  28.08 63.041 42.318 63.247 ;
     RECT  43.128 62.437 43.182 63.247 ;
     RECT  0.036 63.247 1.17 63.391 ;
     RECT  2.304 63.041 27.126 63.553 ;
     RECT  0.036 63.391 1.422 63.931 ;
     RECT  2.268 63.553 27.126 63.931 ;
     RECT  28.08 63.247 43.182 64.165 ;
     RECT  27.936 64.165 43.182 64.769 ;
     RECT  28.08 64.769 43.182 64.781 ;
     RECT  28.08 64.781 42.174 64.973 ;
     RECT  42.912 64.781 43.182 65.261 ;
     RECT  28.08 64.973 42.138 65.357 ;
     RECT  28.08 65.357 42.102 65.453 ;
     RECT  28.08 65.453 41.958 65.939 ;
     RECT  33.264 65.939 41.958 66.253 ;
     RECT  42.984 65.261 43.182 66.253 ;
     RECT  0.036 63.931 27.126 66.509 ;
     RECT  0.036 66.509 0.558 66.701 ;
     RECT  1.404 66.509 27.126 66.929 ;
     RECT  33.264 66.253 43.182 67.181 ;
     RECT  33.264 67.181 42.318 67.277 ;
     RECT  28.08 65.939 32.49 67.441 ;
     RECT  33.264 67.277 42.174 67.441 ;
     RECT  43.056 67.181 43.182 67.559 ;
     RECT  28.08 67.441 42.174 67.595 ;
     RECT  22.068 66.929 27.126 67.603 ;
     RECT  28.08 67.595 32.49 67.603 ;
     RECT  33.264 67.595 42.174 68.099 ;
     RECT  43.056 67.559 43.146 68.251 ;
     RECT  43.02 68.251 43.146 68.513 ;
     RECT  0.036 66.701 0.27 68.587 ;
     RECT  33.264 68.099 41.958 68.881 ;
     RECT  1.404 66.929 21.15 68.909 ;
     RECT  0.036 68.587 0.342 68.917 ;
     RECT  33.264 68.881 42.21 69.101 ;
     RECT  0.036 68.917 0.558 69.223 ;
     RECT  1.404 68.909 21.042 69.223 ;
     RECT  43.02 68.513 43.11 69.485 ;
     RECT  33.264 69.101 42.174 69.521 ;
     RECT  0.036 69.223 21.042 69.677 ;
     RECT  43.056 69.485 43.11 69.677 ;
     RECT  22.068 67.603 32.49 69.791 ;
     RECT  22.068 69.791 31.59 69.869 ;
     RECT  0.036 69.677 0.27 69.944 ;
     RECT  1.116 69.677 21.042 70.025 ;
     RECT  18.288 70.025 21.042 70.097 ;
     RECT  22.068 69.869 31.554 70.169 ;
     RECT  22.392 70.169 31.554 70.331 ;
     RECT  33.264 69.521 35.334 70.411 ;
     RECT  36.36 69.521 42.174 70.411 ;
     RECT  43.092 69.677 43.11 70.445 ;
     RECT  0.072 69.944 0.27 70.645 ;
     RECT  1.116 70.025 17.478 70.645 ;
     RECT  33.264 70.411 42.174 70.835 ;
     RECT  33.264 70.835 35.37 70.943 ;
     RECT  0.072 70.645 17.478 71.117 ;
     RECT  36.36 70.835 42.174 71.177 ;
     RECT  33.264 70.943 35.097 71.339 ;
     RECT  34.272 71.339 35.097 71.375 ;
     RECT  1.98 71.117 17.478 71.405 ;
     RECT  32.472 69.791 32.49 71.491 ;
     RECT  25.668 70.331 31.554 71.519 ;
     RECT  0.072 71.117 1.134 71.597 ;
     RECT  36.504 71.177 42.174 71.597 ;
     RECT  32.436 71.491 32.49 71.609 ;
     RECT  28.512 71.519 31.554 71.879 ;
     RECT  25.668 71.519 27.63 71.915 ;
     RECT  18.504 70.097 21.042 71.951 ;
     RECT  28.548 71.879 31.554 72.023 ;
     RECT  22.392 70.331 24.786 72.059 ;
     RECT  26.676 71.915 27.63 72.059 ;
     RECT  14.328 71.405 17.478 72.149 ;
     RECT  28.548 72.023 30.762 72.185 ;
     RECT  28.728 72.185 30.762 72.257 ;
     RECT  26.676 72.059 27.306 72.293 ;
     RECT  34.776 71.375 35.097 72.391 ;
     RECT  28.764 72.257 30.762 72.419 ;
     RECT  36.504 71.597 41.922 72.419 ;
     RECT  34.776 72.391 35.442 72.491 ;
     RECT  36.756 72.419 41.922 72.563 ;
     RECT  31.536 72.023 31.554 72.571 ;
     RECT  32.472 71.609 32.49 72.571 ;
     RECT  37.296 72.563 41.922 72.571 ;
     RECT  15.264 72.149 17.478 72.599 ;
     RECT  28.764 72.419 30.69 72.599 ;
     RECT  25.668 71.915 25.938 72.689 ;
     RECT  29.415 72.599 30.69 72.725 ;
     RECT  22.392 72.059 23.13 72.761 ;
     RECT  18.615 71.951 21.042 72.841 ;
     RECT  37.296 72.571 42.174 72.941 ;
     RECT  25.776 72.689 25.938 72.959 ;
     RECT  31.536 72.571 32.49 73.229 ;
     RECT  15.264 72.599 17.226 73.265 ;
     RECT  31.536 73.229 31.554 73.265 ;
     RECT  32.328 73.229 32.346 73.265 ;
     RECT  33.264 71.339 33.462 73.309 ;
     RECT  33.12 73.309 33.93 73.409 ;
     RECT  26.676 72.293 26.694 73.651 ;
     RECT  29.415 72.725 30.402 73.651 ;
     RECT  37.296 72.941 41.922 73.741 ;
     RECT  29.415 73.651 30.798 73.769 ;
     RECT  29.415 73.769 30.114 73.805 ;
     RECT  33.264 73.409 33.858 73.805 ;
     RECT  26.676 73.651 26.802 73.841 ;
     RECT  34.776 72.491 35.097 73.877 ;
     RECT  24.015 72.059 24.786 73.921 ;
     RECT  23.652 73.921 24.786 74.039 ;
     RECT  36.972 73.741 41.922 74.075 ;
     RECT  37.62 74.075 41.922 74.155 ;
     RECT  24.015 74.039 24.786 74.489 ;
     RECT  18.324 72.841 21.042 74.579 ;
     RECT  37.62 74.155 42.174 74.615 ;
     RECT  15.696 73.265 17.226 74.623 ;
     RECT  18.324 74.579 18.897 74.623 ;
     RECT  15.696 74.623 18.897 74.669 ;
     RECT  0.072 71.597 0.882 74.921 ;
     RECT  0.144 74.921 0.882 74.957 ;
     RECT  0.216 74.957 0.882 74.965 ;
     RECT  1.98 71.405 13.497 74.965 ;
     RECT  0.216 74.965 13.497 75.053 ;
     RECT  25.92 72.959 25.938 75.155 ;
     RECT  37.62 74.615 38.502 75.211 ;
     RECT  15.696 74.669 17.226 75.263 ;
     RECT  33.264 73.805 33.462 75.271 ;
     RECT  37.548 75.211 38.502 75.361 ;
     RECT  30.78 75.271 30.798 75.389 ;
     RECT  33.264 75.271 33.606 75.389 ;
     RECT  33.264 75.389 33.426 75.425 ;
     RECT  37.44 75.361 38.502 75.461 ;
     RECT  0.54 75.053 13.497 75.533 ;
     RECT  43.092 72.769 43.11 75.533 ;
     RECT  37.836 75.461 38.502 75.569 ;
     RECT  39.24 74.615 42.174 75.629 ;
     RECT  38.484 75.569 38.502 75.631 ;
     RECT  39.24 75.629 40.842 75.631 ;
     RECT  15.696 75.263 16.794 75.659 ;
     RECT  26.676 73.841 26.694 75.659 ;
     RECT  38.484 75.631 40.842 75.695 ;
     RECT  41.58 75.629 42.174 75.739 ;
     RECT  38.484 75.695 40.497 75.803 ;
     RECT  0.54 75.533 10.314 75.883 ;
     RECT  15.408 75.811 15.426 75.929 ;
     RECT  19.692 74.579 21.042 75.929 ;
     RECT  33.264 75.425 33.282 75.929 ;
     RECT  18.324 74.669 18.897 75.931 ;
     RECT  19.692 75.929 20.286 75.931 ;
     RECT  38.484 75.803 38.502 75.965 ;
     RECT  0.108 75.883 10.314 76.001 ;
     RECT  21.024 75.929 21.042 76.081 ;
     RECT  34.815 73.877 35.097 76.081 ;
     RECT  21.024 76.081 21.654 76.109 ;
     RECT  41.58 75.739 42.21 76.109 ;
     RECT  0.144 76.001 10.314 76.199 ;
     RECT  21.564 76.109 21.654 76.199 ;
     RECT  39.528 75.803 40.497 76.235 ;
     RECT  34.776 76.081 35.097 76.343 ;
     RECT  43.092 76.351 43.11 76.397 ;
     RECT  41.58 76.109 42.138 76.493 ;
     RECT  18.324 75.931 20.286 76.541 ;
     RECT  41.58 76.493 41.67 76.589 ;
     RECT  18.324 76.541 18.897 76.621 ;
     RECT  41.652 76.589 41.67 76.685 ;
     RECT  0.144 76.199 9.99 76.829 ;
     RECT  0.18 76.829 9.99 77.069 ;
     RECT  9.216 77.069 9.99 77.279 ;
     RECT  0.18 77.069 8.154 77.593 ;
     RECT  21.564 76.199 21.582 77.947 ;
     RECT  0.108 77.593 8.154 77.999 ;
     RECT  21.384 77.947 21.582 78.089 ;
     RECT  22.392 72.761 22.518 78.089 ;
     RECT  0.108 77.999 8.097 78.317 ;
     RECT  1.404 78.317 8.097 78.359 ;
     RECT  11.34 75.533 13.497 78.359 ;
     RECT  9.36 77.279 9.99 78.367 ;
     RECT  0.108 78.317 0.558 78.439 ;
     RECT  9.36 78.367 10.566 78.511 ;
     RECT  11.34 78.359 12.258 78.511 ;
     RECT  1.404 78.359 6.21 78.629 ;
     RECT  14.328 72.149 14.346 78.629 ;
     RECT  6.048 78.629 6.21 78.701 ;
     RECT  9.36 78.511 12.258 79.169 ;
     RECT  9.36 79.169 11.61 79.229 ;
     RECT  18.216 76.621 18.897 79.243 ;
     RECT  6.12 78.701 6.21 79.483 ;
     RECT  6.948 78.359 8.097 79.483 ;
     RECT  11.34 79.229 11.61 79.709 ;
     RECT  22.5 78.089 22.518 79.709 ;
     RECT  24.015 74.489 24.714 79.709 ;
     RECT  17.856 79.243 18.897 79.745 ;
     RECT  24.015 79.709 24.297 79.753 ;
     RECT  0.036 78.439 0.558 79.853 ;
     RECT  23.94 79.753 24.297 79.979 ;
     RECT  1.404 78.629 5.274 80.023 ;
     RECT  6.12 79.483 8.097 80.023 ;
     RECT  1.404 80.023 8.097 80.123 ;
     RECT  21.564 78.089 21.582 80.249 ;
     RECT  1.404 80.123 6.966 80.333 ;
     RECT  7.704 80.123 8.097 80.347 ;
     RECT  16.236 75.659 16.794 80.393 ;
     RECT  18.216 79.745 18.897 80.429 ;
     RECT  9.36 79.229 10.566 80.519 ;
     RECT  7.704 80.347 8.442 80.525 ;
     RECT  0.036 79.853 0.126 80.591 ;
     RECT  1.44 80.333 6.966 80.669 ;
     RECT  1.44 80.669 5.274 80.699 ;
     RECT  11.412 79.709 11.61 80.789 ;
     RECT  1.44 80.699 4.698 81.005 ;
     RECT  6.084 80.669 6.966 81.059 ;
     RECT  0.108 80.591 0.126 81.101 ;
     RECT  19.692 76.541 20.286 81.203 ;
     RECT  16.776 80.393 16.794 81.239 ;
     RECT  2.052 81.005 4.698 81.329 ;
     RECT  6.084 81.059 6.57 81.329 ;
     RECT  9.396 80.519 10.566 81.329 ;
     RECT  7.815 80.525 8.442 81.481 ;
     RECT  11.412 80.789 11.43 81.869 ;
     RECT  7.815 81.481 8.622 82.409 ;
     RECT  7.815 82.409 8.097 82.525 ;
     RECT  19.692 81.203 19.71 82.679 ;
     RECT  4.644 81.329 4.698 82.789 ;
     RECT  2.052 81.329 3.69 82.795 ;
     RECT  2.052 82.795 3.726 82.831 ;
     RECT  4.644 82.789 4.806 82.831 ;
     RECT  2.052 82.831 3.87 82.921 ;
     RECT  4.644 82.831 4.95 82.921 ;
     RECT  2.052 82.921 4.95 82.949 ;
     RECT  6.084 81.329 6.102 82.949 ;
     RECT  7.38 82.525 8.097 83.219 ;
     RECT  0.108 82.795 0.126 83.227 ;
     RECT  2.052 82.949 4.698 83.489 ;
     RECT  9.972 81.329 10.566 83.759 ;
     RECT  2.052 83.489 3.69 83.789 ;
     RECT  2.196 83.789 3.69 83.867 ;
     RECT  2.196 83.867 3.474 84.029 ;
     RECT  9.972 83.759 9.99 84.029 ;
     RECT  0.108 83.227 0.198 84.077 ;
     RECT  2.196 84.029 3.438 84.299 ;
     RECT  2.196 84.299 3.33 84.443 ;
     RECT  0.144 84.077 0.198 84.557 ;
     RECT  5.472 83.065 5.49 84.569 ;
     RECT  4.68 84.685 4.698 84.839 ;
     RECT  2.268 84.443 3.33 84.875 ;
     RECT  0.18 84.557 0.198 84.941 ;
     RECT  2.304 84.875 3.33 85.145 ;
     RECT  2.34 85.145 3.33 85.379 ;
     RECT  2.34 85.379 3.078 85.649 ;
     RECT  2.34 85.649 2.754 85.919 ;
     RECT  2.34 85.919 2.697 86.059 ;
     RECT  2.304 86.059 2.697 86.225 ;
     RECT  2.415 86.225 2.697 105.587 ;
     RECT  7.815 83.219 8.097 105.587 ;
     RECT  13.215 78.359 13.497 105.587 ;
     RECT  18.615 80.429 18.897 105.587 ;
     RECT  24.015 79.979 24.297 105.587 ;
     RECT  29.415 73.805 29.697 105.587 ;
     RECT  34.815 76.343 35.097 105.587 ;
     RECT  40.215 76.235 40.497 105.587 ;
     RECT  2.415 105.587 2.505 105.857 ;
     RECT  7.815 105.587 7.905 105.857 ;
     RECT  13.215 105.587 13.305 105.857 ;
     RECT  18.615 105.587 18.705 105.857 ;
     RECT  24.015 105.587 24.105 105.857 ;
     RECT  29.415 105.587 29.505 105.857 ;
     RECT  34.815 105.587 34.905 105.857 ;
     RECT  40.215 105.587 40.305 105.857 ;
    LAYER M4 ;
     RECT  0.06 31.248 0.133 81.864 ;
     RECT  0.06 83.376 0.209 84.936 ;
     RECT  0.133 31.248 0.569 82.104 ;
     RECT  0.569 31.248 2.408 68.808 ;
     RECT  0.569 69.936 2.408 82.104 ;
     RECT  0.209 83.376 2.408 84.84 ;
     RECT  0.133 86.064 2.408 86.088 ;
     RECT  2.408 2.148 2.512 105.852 ;
     RECT  2.512 2.418 2.704 105.582 ;
     RECT  2.704 75.792 2.765 81.672 ;
     RECT  2.704 84.336 2.765 84.36 ;
     RECT  2.765 81.648 2.801 81.672 ;
     RECT  2.704 70.32 2.837 74.712 ;
     RECT  2.765 75.792 2.837 80.616 ;
     RECT  2.837 74.4 2.873 74.712 ;
     RECT  2.837 75.792 2.909 77.928 ;
     RECT  2.873 74.496 3.089 74.712 ;
     RECT  3.089 74.496 3.161 74.616 ;
     RECT  2.837 80.592 3.161 80.616 ;
     RECT  2.704 61.44 3.449 68.808 ;
     RECT  3.449 61.968 4.165 68.808 ;
     RECT  2.837 70.32 4.165 73.32 ;
     RECT  3.161 74.496 4.165 74.52 ;
     RECT  2.704 31.248 4.169 59.592 ;
     RECT  4.165 70.32 4.205 74.616 ;
     RECT  4.205 70.608 4.277 74.616 ;
     RECT  4.169 40.272 4.309 59.592 ;
     RECT  4.165 61.968 4.561 68.904 ;
     RECT  4.309 40.272 4.565 60.216 ;
     RECT  4.277 74.496 4.597 74.616 ;
     RECT  4.565 60.192 4.633 60.216 ;
     RECT  4.561 61.968 4.633 68.952 ;
     RECT  4.565 40.272 4.637 59.016 ;
     RECT  4.597 74.496 4.781 74.664 ;
     RECT  3.697 82.8 4.881 82.824 ;
     RECT  4.637 40.272 4.925 49.224 ;
     RECT  4.789 80.16 4.997 80.664 ;
     RECT  4.633 60.192 5.137 68.952 ;
     RECT  4.637 50.208 5.171 59.016 ;
     RECT  4.925 40.464 5.213 49.224 ;
     RECT  5.137 60.192 5.249 69.432 ;
     RECT  4.169 31.248 5.357 38.952 ;
     RECT  2.909 75.792 5.357 77.688 ;
     RECT  4.277 70.608 5.425 73.512 ;
     RECT  5.357 75.792 5.429 77.64 ;
     RECT  5.249 61.104 5.645 69.432 ;
     RECT  5.425 70.56 5.853 73.512 ;
     RECT  5.645 61.44 5.897 69.432 ;
     RECT  4.997 80.496 5.933 80.664 ;
     RECT  5.897 67.248 6.131 69.432 ;
     RECT  5.213 40.464 6.217 42.792 ;
     RECT  5.357 31.248 6.229 38.76 ;
     RECT  5.213 44.4 6.361 49.224 ;
     RECT  5.171 50.304 6.361 59.016 ;
     RECT  5.853 70.56 6.509 73.32 ;
     RECT  6.361 44.4 6.617 59.016 ;
     RECT  6.509 71.376 6.617 73.32 ;
     RECT  5.653 60.096 6.649 60.12 ;
     RECT  6.649 60.048 6.757 60.12 ;
     RECT  5.897 61.44 6.757 66.072 ;
     RECT  6.617 48.432 6.829 59.016 ;
     RECT  6.757 60.048 6.829 66.072 ;
     RECT  5.429 75.792 6.829 77.592 ;
     RECT  6.829 48.432 7.117 66.072 ;
     RECT  6.131 67.392 7.117 69.432 ;
     RECT  6.829 75.696 7.436 77.592 ;
     RECT  6.217 40.08 7.585 42.792 ;
     RECT  6.229 31.152 7.808 38.76 ;
     RECT  7.585 40.08 7.808 42.984 ;
     RECT  6.617 44.4 7.808 47.352 ;
     RECT  7.117 48.432 7.808 69.432 ;
     RECT  6.617 71.376 7.808 73.128 ;
     RECT  4.781 74.496 7.808 74.52 ;
     RECT  7.436 75.696 7.808 77.928 ;
     RECT  5.933 80.496 7.808 80.52 ;
     RECT  7.808 2.148 7.912 105.852 ;
     RECT  7.912 2.418 8.104 105.582 ;
     RECT  8.104 66.048 8.489 68.952 ;
     RECT  8.489 66.048 8.561 68.904 ;
     RECT  8.104 74.448 8.819 77.928 ;
     RECT  8.104 80.352 8.819 80.376 ;
     RECT  8.819 74.448 8.849 77.064 ;
     RECT  8.849 74.448 8.885 76.584 ;
     RECT  8.885 74.448 9.107 75.96 ;
     RECT  8.104 63.072 9.133 63.096 ;
     RECT  8.104 64.08 9.133 64.392 ;
     RECT  8.104 40.08 9.169 42.072 ;
     RECT  9.107 75.696 9.203 75.96 ;
     RECT  9.133 63.072 9.205 64.392 ;
     RECT  8.104 31.152 9.245 36.936 ;
     RECT  8.104 44.4 9.245 56.328 ;
     RECT  9.169 40.08 9.389 43.032 ;
     RECT  9.205 62.928 9.421 64.824 ;
     RECT  8.561 66.768 9.533 68.904 ;
     RECT  9.533 66.768 9.637 67.272 ;
     RECT  9.245 46.848 9.641 56.328 ;
     RECT  9.421 62.928 9.641 64.968 ;
     RECT  8.104 57.6 9.673 61.944 ;
     RECT  9.389 40.08 9.785 42.072 ;
     RECT  8.104 71.376 9.817 71.688 ;
     RECT  8.104 72.816 9.817 73.128 ;
     RECT  9.641 46.848 9.821 49.896 ;
     RECT  9.641 50.976 10.001 56.328 ;
     RECT  9.203 75.792 10.073 75.96 ;
     RECT  9.107 74.448 10.145 74.472 ;
     RECT  9.637 66.72 10.217 67.272 ;
     RECT  9.245 44.4 10.253 45.864 ;
     RECT  9.821 48.48 10.289 49.896 ;
     RECT  8.104 79.296 10.357 79.32 ;
     RECT  10.357 79.2 10.397 79.32 ;
     RECT  9.821 46.848 10.645 47.16 ;
     RECT  10.289 48.72 10.645 49.896 ;
     RECT  10.001 50.976 10.645 56.232 ;
     RECT  9.533 68.4 10.649 68.904 ;
     RECT  9.673 57.408 10.681 61.944 ;
     RECT  9.641 62.928 10.681 63.768 ;
     RECT  10.217 66.72 10.757 66.744 ;
     RECT  10.681 57.408 10.829 63.768 ;
     RECT  10.829 57.408 10.861 58.824 ;
     RECT  9.817 71.376 10.865 73.128 ;
     RECT  9.641 64.944 10.897 64.968 ;
     RECT  10.897 64.848 11.009 64.968 ;
     RECT  10.829 59.856 11.081 63.768 ;
     RECT  10.861 57.312 11.189 58.824 ;
     RECT  10.397 79.2 11.297 79.224 ;
     RECT  10.645 46.128 11.329 47.16 ;
     RECT  10.645 48.72 11.405 56.232 ;
     RECT  11.081 59.856 11.405 63.288 ;
     RECT  11.329 46.128 11.413 47.304 ;
     RECT  11.189 57.408 11.869 58.824 ;
     RECT  10.649 68.4 11.893 68.664 ;
     RECT  10.865 71.376 11.909 73.032 ;
     RECT  11.893 68.352 11.939 68.664 ;
     RECT  11.909 71.376 11.939 71.832 ;
     RECT  11.939 68.352 11.941 68.376 ;
     RECT  11.869 57.408 11.977 58.872 ;
     RECT  11.405 59.856 11.977 62.952 ;
     RECT  11.977 57.408 11.981 62.952 ;
     RECT  11.941 67.824 11.981 68.376 ;
     RECT  11.905 66.096 11.989 66.12 ;
     RECT  11.981 57.552 12.017 62.952 ;
     RECT  11.981 67.824 12.025 68.136 ;
     RECT  10.253 44.4 12.085 45.048 ;
     RECT  11.413 46.128 12.085 47.88 ;
     RECT  12.157 43.2 12.188 43.224 ;
     RECT  12.188 43.2 12.301 43.272 ;
     RECT  11.405 48.912 12.661 56.232 ;
     RECT  9.785 40.08 12.733 41.976 ;
     RECT  12.301 43.2 12.733 43.32 ;
     RECT  12.017 57.6 12.769 62.952 ;
     RECT  12.769 57.6 13.057 63.288 ;
     RECT  12.733 40.08 13.093 43.32 ;
     RECT  12.085 44.4 13.093 47.88 ;
     RECT  12.661 48.912 13.093 56.376 ;
     RECT  13.057 57.408 13.093 63.288 ;
     RECT  9.245 31.152 13.208 36.888 ;
     RECT  13.093 40.08 13.208 43.416 ;
     RECT  13.093 44.4 13.208 63.288 ;
     RECT  11.009 64.848 13.208 64.872 ;
     RECT  12.025 68.112 13.208 68.136 ;
     RECT  11.939 71.376 13.208 71.688 ;
     RECT  11.909 72.816 13.208 73.032 ;
     RECT  10.073 75.792 13.208 75.816 ;
     RECT  11.977 78.432 13.208 78.456 ;
     RECT  13.208 2.148 13.312 105.852 ;
     RECT  13.312 2.418 13.504 105.582 ;
     RECT  13.504 46.416 13.565 54.984 ;
     RECT  13.504 30.768 13.66 33.048 ;
     RECT  13.565 46.416 13.667 53.688 ;
     RECT  13.504 41.952 13.673 45.048 ;
     RECT  13.504 71.376 13.673 71.688 ;
     RECT  13.667 46.512 13.709 53.688 ;
     RECT  13.673 41.952 13.745 44.424 ;
     RECT  13.745 42.096 13.853 44.424 ;
     RECT  13.504 34.944 13.997 36.888 ;
     RECT  13.853 42.096 14.003 42.12 ;
     RECT  13.853 43.2 14.003 44.424 ;
     RECT  14.003 43.344 14.213 44.424 ;
     RECT  13.504 64.944 14.332 65.4 ;
     RECT  14.636 66.432 14.677 66.456 ;
     RECT  14.332 65.376 14.785 65.4 ;
     RECT  14.677 66.432 14.785 66.744 ;
     RECT  13.66 31.152 14.789 33.048 ;
     RECT  14.213 44.208 14.857 44.424 ;
     RECT  13.709 46.848 14.857 53.688 ;
     RECT  13.565 54.672 14.857 54.984 ;
     RECT  14.789 31.152 14.969 32.856 ;
     RECT  14.857 46.848 15.005 54.984 ;
     RECT  14.785 65.376 15.005 66.744 ;
     RECT  14.857 44.208 15.113 45.048 ;
     RECT  13.504 56.016 15.217 61.992 ;
     RECT  13.504 63.072 15.329 63.816 ;
     RECT  15.005 65.376 15.365 66.504 ;
     RECT  13.673 71.616 15.397 71.688 ;
     RECT  14.969 31.152 15.437 32.232 ;
     RECT  15.397 71.616 15.437 71.832 ;
     RECT  15.005 48.864 15.493 54.984 ;
     RECT  15.217 55.968 15.493 61.992 ;
     RECT  15.493 48.864 15.581 61.992 ;
     RECT  13.504 72.96 15.689 73.032 ;
     RECT  15.329 63.072 15.721 63.288 ;
     RECT  13.504 68.112 15.781 68.136 ;
     RECT  15.437 31.152 15.833 32.04 ;
     RECT  15.581 54.672 15.833 61.992 ;
     RECT  15.365 65.376 15.865 65.4 ;
     RECT  15.781 67.824 15.869 68.808 ;
     RECT  15.365 66.48 15.977 66.504 ;
     RECT  13.504 40.08 16.508 40.584 ;
     RECT  15.005 46.848 16.508 47.832 ;
     RECT  15.869 67.824 16.589 67.848 ;
     RECT  16.508 40.08 16.595 41.016 ;
     RECT  15.217 42.144 16.595 42.168 ;
     RECT  16.595 40.08 16.697 40.584 ;
     RECT  15.581 48.864 16.837 53.688 ;
     RECT  15.833 54.672 16.837 61.752 ;
     RECT  16.508 46.752 16.981 47.832 ;
     RECT  16.837 48.864 16.981 61.752 ;
     RECT  16.981 46.752 17.233 61.752 ;
     RECT  15.721 62.976 17.305 63.288 ;
     RECT  17.305 62.784 17.309 63.288 ;
     RECT  13.504 78.432 17.797 78.456 ;
     RECT  15.865 65.184 17.893 65.4 ;
     RECT  16.765 66.72 17.893 66.744 ;
     RECT  15.437 71.808 17.941 71.832 ;
     RECT  15.689 72.96 17.941 72.984 ;
     RECT  17.233 45.792 18.097 61.752 ;
     RECT  15.113 44.208 18.277 44.424 ;
     RECT  15.833 31.152 18.608 31.992 ;
     RECT  13.997 34.944 18.608 36.6 ;
     RECT  16.697 40.08 18.608 40.104 ;
     RECT  18.277 43.344 18.608 44.424 ;
     RECT  18.097 45.456 18.608 61.752 ;
     RECT  17.309 62.784 18.608 63 ;
     RECT  17.893 65.184 18.608 66.744 ;
     RECT  17.893 67.824 18.608 67.848 ;
     RECT  17.941 71.808 18.608 72.984 ;
     RECT  17.881 74.64 18.608 74.664 ;
     RECT  17.797 75.936 18.608 75.96 ;
     RECT  17.797 78.432 18.608 79.272 ;
     RECT  18.608 2.148 18.712 105.852 ;
     RECT  18.712 2.418 18.904 105.582 ;
     RECT  18.904 41.712 19.037 41.736 ;
     RECT  18.904 71.424 19.043 72.984 ;
     RECT  18.904 43.584 19.109 54.984 ;
     RECT  19.109 43.584 19.145 47.256 ;
     RECT  18.904 67.824 19.181 67.848 ;
     RECT  19.145 44.208 19.253 47.256 ;
     RECT  19.043 72.24 19.325 72.984 ;
     RECT  19.325 72.24 19.433 72.264 ;
     RECT  19.253 46.8 20.009 47.256 ;
     RECT  18.904 75.936 20.153 75.96 ;
     RECT  18.904 56.016 20.189 61.752 ;
     RECT  19.253 44.208 20.581 45.816 ;
     RECT  20.009 46.8 20.581 47.16 ;
     RECT  20.581 42.768 20.873 42.792 ;
     RECT  20.189 56.208 21.157 61.752 ;
     RECT  19.109 48.384 21.253 54.984 ;
     RECT  21.157 56.016 21.253 61.752 ;
     RECT  18.904 62.784 21.373 63 ;
     RECT  21.253 48.384 21.485 61.752 ;
     RECT  21.373 62.784 21.635 63.768 ;
     RECT  21.635 62.976 21.701 63.768 ;
     RECT  20.581 44.208 22.129 47.16 ;
     RECT  21.485 48.384 22.129 60.648 ;
     RECT  22.021 42.72 22.237 42.744 ;
     RECT  22.129 44.208 22.237 60.648 ;
     RECT  22.237 42.72 22.637 60.648 ;
     RECT  22.849 38.16 22.877 38.184 ;
     RECT  22.637 42.72 22.925 44.664 ;
     RECT  22.877 38.16 22.961 38.76 ;
     RECT  22.988 69.696 23.029 69.72 ;
     RECT  21.701 62.976 23.065 63.288 ;
     RECT  22.637 45.696 23.173 60.648 ;
     RECT  21.485 61.68 23.173 61.752 ;
     RECT  18.904 31.152 24.008 31.992 ;
     RECT  18.904 36.24 24.008 36.6 ;
     RECT  22.961 38.16 24.008 38.184 ;
     RECT  18.904 40.08 24.008 40.104 ;
     RECT  22.925 42.72 24.008 44.472 ;
     RECT  23.173 45.696 24.008 61.752 ;
     RECT  23.065 62.976 24.008 63.816 ;
     RECT  23.029 69.696 24.008 70.248 ;
     RECT  21.373 77.952 24.008 77.976 ;
     RECT  24.008 2.148 24.112 105.852 ;
     RECT  24.112 2.418 24.304 105.582 ;
     RECT  24.304 36.24 25.049 38.184 ;
     RECT  24.304 40.08 25.229 40.44 ;
     RECT  24.304 42.72 25.283 44.424 ;
     RECT  24.304 13.632 25.292 13.656 ;
     RECT  25.049 36.24 25.373 36.792 ;
     RECT  25.292 13.056 25.379 13.656 ;
     RECT  25.283 43.92 25.669 44.424 ;
     RECT  24.304 45.696 25.669 52.392 ;
     RECT  25.379 13.632 25.805 13.656 ;
     RECT  25.283 42.72 25.909 42.744 ;
     RECT  25.049 38.16 25.955 38.184 ;
     RECT  25.669 43.92 26.017 52.392 ;
     RECT  24.304 53.664 26.017 61.752 ;
     RECT  26.017 43.92 26.129 61.752 ;
     RECT  26.129 45.792 26.197 61.752 ;
     RECT  24.304 62.736 26.197 63.24 ;
     RECT  26.125 65.328 26.197 65.352 ;
     RECT  26.197 45.792 26.453 63.24 ;
     RECT  25.909 42.432 26.557 42.744 ;
     RECT  26.557 42.432 26.669 42.792 ;
     RECT  26.701 1.728 26.785 1.752 ;
     RECT  26.129 43.92 26.813 44.424 ;
     RECT  26.197 65.328 27.061 65.736 ;
     RECT  27.061 64.992 27.347 65.736 ;
     RECT  26.813 43.968 28.021 44.424 ;
     RECT  28.021 43.968 29.041 44.472 ;
     RECT  26.453 45.792 29.041 61.752 ;
     RECT  24.304 31.152 29.408 31.992 ;
     RECT  25.373 36.24 29.408 36.264 ;
     RECT  25.229 40.08 29.408 40.104 ;
     RECT  26.669 42.432 29.408 42.744 ;
     RECT  29.041 43.968 29.408 61.752 ;
     RECT  26.453 63.216 29.408 63.24 ;
     RECT  27.347 65.712 29.408 65.736 ;
     RECT  24.304 77.952 29.408 77.976 ;
     RECT  29.408 2.148 29.512 105.852 ;
     RECT  29.512 2.418 29.704 105.582 ;
     RECT  29.704 45.792 29.843 62.184 ;
     RECT  29.704 65.568 30.313 65.592 ;
     RECT  29.704 43.968 30.737 44.424 ;
     RECT  30.737 44.112 30.769 44.424 ;
     RECT  29.843 61.68 30.805 61.752 ;
     RECT  30.769 44.112 30.913 44.808 ;
     RECT  29.843 45.792 30.913 60.648 ;
     RECT  30.805 61.632 30.953 61.752 ;
     RECT  29.704 34.752 31.025 34.776 ;
     RECT  30.953 61.68 31.277 61.752 ;
     RECT  30.913 44.112 31.529 60.648 ;
     RECT  29.704 63.216 31.561 63.24 ;
     RECT  31.529 44.4 31.853 60.648 ;
     RECT  31.561 62.736 31.859 63.24 ;
     RECT  31.853 44.4 31.889 50.136 ;
     RECT  31.859 62.784 31.925 63.24 ;
     RECT  31.889 46.848 31.961 50.136 ;
     RECT  31.925 63.216 32.197 63.24 ;
     RECT  32.165 65.568 32.197 65.592 ;
     RECT  29.704 36.24 32.209 36.264 ;
     RECT  32.197 63.216 32.249 65.592 ;
     RECT  32.249 63.216 32.284 64.92 ;
     RECT  30.805 69.84 32.341 69.864 ;
     RECT  32.341 69.84 32.387 70.104 ;
     RECT  32.3 73.2 32.387 73.224 ;
     RECT  29.704 77.952 32.387 77.976 ;
     RECT  31.961 50.016 32.609 50.136 ;
     RECT  31.961 46.848 32.717 48.936 ;
     RECT  31.889 44.4 32.857 45.864 ;
     RECT  32.717 46.848 32.857 48.744 ;
     RECT  32.785 34.752 32.869 34.776 ;
     RECT  29.704 42.432 32.893 42.744 ;
     RECT  32.609 50.064 32.897 50.136 ;
     RECT  29.704 40.08 33.181 40.104 ;
     RECT  32.893 42.432 33.289 43.08 ;
     RECT  32.857 44.4 33.289 48.744 ;
     RECT  32.284 63.216 33.469 63.24 ;
     RECT  33.289 42.432 33.581 48.744 ;
     RECT  33.181 40.08 34.009 40.968 ;
     RECT  33.581 42.432 34.009 46.872 ;
     RECT  34.117 67.824 34.153 67.848 ;
     RECT  34.153 67.824 34.165 68.376 ;
     RECT  32.387 70.08 34.165 70.104 ;
     RECT  33.469 62.736 34.261 63.24 ;
     RECT  32.209 36.24 34.765 36.84 ;
     RECT  33.581 47.856 34.765 48.744 ;
     RECT  34.165 67.824 34.765 70.104 ;
     RECT  34.009 40.08 34.801 46.872 ;
     RECT  34.765 47.856 34.801 48.792 ;
     RECT  34.117 23.856 34.808 23.88 ;
     RECT  34.045 28.704 34.808 28.728 ;
     RECT  32.677 30.096 34.808 30.12 ;
     RECT  29.704 31.152 34.808 31.992 ;
     RECT  34.765 36.24 34.808 36.888 ;
     RECT  34.801 40.08 34.808 48.792 ;
     RECT  32.897 50.064 34.808 50.088 ;
     RECT  31.853 51.168 34.808 60.648 ;
     RECT  31.277 61.728 34.808 61.752 ;
     RECT  34.261 62.736 34.808 63.912 ;
     RECT  32.284 64.896 34.808 64.92 ;
     RECT  34.765 67.824 34.808 70.68 ;
     RECT  34.808 2.148 34.912 105.852 ;
     RECT  34.912 2.418 35.104 105.582 ;
     RECT  35.104 69.408 35.245 69.576 ;
     RECT  35.104 50.064 35.267 64.92 ;
     RECT  35.104 70.656 35.453 70.68 ;
     RECT  35.267 50.064 35.705 64.392 ;
     RECT  35.104 42.384 35.932 43.272 ;
     RECT  35.104 66.336 35.957 66.696 ;
     RECT  35.104 38.112 36.029 38.232 ;
     RECT  36.029 38.208 36.073 38.232 ;
     RECT  35.104 39.36 36.097 40.968 ;
     RECT  36.097 39.36 36.137 41.592 ;
     RECT  35.932 42.624 36.205 43.272 ;
     RECT  35.104 44.352 36.205 48.744 ;
     RECT  36.137 40.032 36.323 41.592 ;
     RECT  36.205 42.624 36.389 48.744 ;
     RECT  36.389 44.88 36.457 48.744 ;
     RECT  35.104 36.24 36.611 36.888 ;
     RECT  35.104 30.096 36.637 30.12 ;
     RECT  36.389 42.624 36.641 43.704 ;
     RECT  35.705 50.064 36.745 50.088 ;
     RECT  35.705 51.168 36.745 64.392 ;
     RECT  35.104 28.56 36.817 28.776 ;
     RECT  36.745 50.064 36.965 64.392 ;
     RECT  36.853 70.656 36.997 70.68 ;
     RECT  36.853 72.144 36.997 72.168 ;
     RECT  36.457 44.88 37.001 48.792 ;
     RECT  36.997 70.656 37.043 72.168 ;
     RECT  36.965 50.064 37.217 63.912 ;
     RECT  37.043 71.616 37.285 72.168 ;
     RECT  35.104 34.08 37.325 34.104 ;
     RECT  35.104 26.496 37.357 26.52 ;
     RECT  37.285 71.616 37.372 72.696 ;
     RECT  37.357 26.496 37.393 27.192 ;
     RECT  37.372 71.616 37.541 72.504 ;
     RECT  36.637 30.096 37.681 30.168 ;
     RECT  35.957 66.672 37.681 66.696 ;
     RECT  36.323 40.032 37.753 41.544 ;
     RECT  36.641 42.624 37.753 43.272 ;
     RECT  36.611 36.864 37.813 36.888 ;
     RECT  36.817 28.416 37.825 28.776 ;
     RECT  37.537 75.216 37.829 75.24 ;
     RECT  37.813 36.096 37.859 36.888 ;
     RECT  37.393 26.352 37.861 27.192 ;
     RECT  35.104 31.152 37.964 31.992 ;
     RECT  37.825 28.416 38.051 29.016 ;
     RECT  37.681 30.048 38.051 30.168 ;
     RECT  37.964 31.152 38.051 32.52 ;
     RECT  36.637 67.68 38.117 67.704 ;
     RECT  37.861 26.352 38.185 27.432 ;
     RECT  38.051 28.416 38.185 28.776 ;
     RECT  37.001 44.88 38.185 48.744 ;
     RECT  37.217 50.064 38.185 62.856 ;
     RECT  38.101 35.088 38.188 35.112 ;
     RECT  37.681 66.288 38.245 66.696 ;
     RECT  37.753 40.032 38.257 43.272 ;
     RECT  35.245 69.408 38.291 69.432 ;
     RECT  38.185 44.88 38.365 62.856 ;
     RECT  37.217 63.888 38.365 63.912 ;
     RECT  38.365 44.88 38.369 63.912 ;
     RECT  38.257 39.888 38.387 43.272 ;
     RECT  38.245 66.288 38.533 67.272 ;
     RECT  38.533 66.096 38.549 67.272 ;
     RECT  38.369 46.56 38.585 63.912 ;
     RECT  35.104 23.856 38.653 23.88 ;
     RECT  37.541 71.952 38.653 72.504 ;
     RECT  38.369 44.88 38.675 45.576 ;
     RECT  38.675 44.88 38.749 45.528 ;
     RECT  38.653 71.136 38.761 72.504 ;
     RECT  38.509 38.88 38.765 38.904 ;
     RECT  38.585 46.56 38.765 48.168 ;
     RECT  38.749 44.88 38.797 45.48 ;
     RECT  38.473 37.68 38.833 37.8 ;
     RECT  38.765 46.56 38.837 46.872 ;
     RECT  38.585 49.248 38.869 63.912 ;
     RECT  38.653 23.088 38.905 23.88 ;
     RECT  38.833 37.68 38.924 37.848 ;
     RECT  37.859 36.096 38.945 36.408 ;
     RECT  38.837 46.56 38.945 46.776 ;
     RECT  38.924 37.68 38.965 37.944 ;
     RECT  38.549 66.096 38.981 67.08 ;
     RECT  38.965 37.536 39.011 37.944 ;
     RECT  38.761 70.416 39.013 72.504 ;
     RECT  38.797 73.872 39.013 73.896 ;
     RECT  38.945 36.384 39.017 36.408 ;
     RECT  39.011 37.536 39.053 37.8 ;
     RECT  39.013 70.416 39.089 73.896 ;
     RECT  38.945 46.608 39.125 46.776 ;
     RECT  38.765 47.856 39.125 48.168 ;
     RECT  38.051 31.152 39.445 31.992 ;
     RECT  39.049 33.264 39.445 33.288 ;
     RECT  38.869 49.248 39.553 64.392 ;
     RECT  38.185 26.352 39.625 28.776 ;
     RECT  39.553 49.2 39.625 64.392 ;
     RECT  38.051 30.048 39.661 30.12 ;
     RECT  39.445 31.152 39.661 33.288 ;
     RECT  39.625 49.2 39.841 64.44 ;
     RECT  39.053 37.584 40.021 37.8 ;
     RECT  40.021 36.912 40.057 37.8 ;
     RECT  38.905 23.088 40.208 24.456 ;
     RECT  39.625 26.064 40.208 28.776 ;
     RECT  39.661 30.048 40.208 33.288 ;
     RECT  39.013 35.184 40.208 35.208 ;
     RECT  40.057 36.24 40.208 37.8 ;
     RECT  38.387 40.032 40.208 43.272 ;
     RECT  38.797 44.352 40.208 45.48 ;
     RECT  39.125 46.608 40.208 46.632 ;
     RECT  39.125 48.144 40.208 48.168 ;
     RECT  39.841 49.2 40.208 64.728 ;
     RECT  38.981 66.24 40.208 67.08 ;
     RECT  40.057 68.928 40.208 68.952 ;
     RECT  39.089 70.512 40.208 73.896 ;
     RECT  40.208 2.148 40.312 105.852 ;
     RECT  40.312 2.418 40.504 105.582 ;
     RECT  40.504 58.416 40.745 75.624 ;
     RECT  40.504 29.904 41.533 39.528 ;
     RECT  40.504 40.752 41.533 57.384 ;
     RECT  40.504 26.064 41.569 28.776 ;
     RECT  41.533 29.904 41.569 57.384 ;
     RECT  40.745 65.616 41.569 75.624 ;
     RECT  41.569 65.616 41.641 76.584 ;
     RECT  40.504 22.992 41.893 24.456 ;
     RECT  40.745 58.416 41.893 64.632 ;
     RECT  41.641 65.616 41.893 76.68 ;
     RECT  41.569 26.064 42.145 57.384 ;
     RECT  41.893 58.416 42.145 76.68 ;
     RECT  41.893 22.992 43.164 24.552 ;
     RECT  42.145 26.064 43.164 76.68 ;
    LAYER M5 ;
     RECT  26.64 0.016 26.76 1.763 ;
     RECT  2.4 2.137 2.52 2.151 ;
     RECT  7.8 2.137 7.92 2.151 ;
     RECT  13.2 2.137 13.32 2.151 ;
     RECT  18.6 2.137 18.72 2.151 ;
     RECT  24 2.137 24.12 2.151 ;
     RECT  29.4 2.137 29.52 2.151 ;
     RECT  34.8 2.137 34.92 2.151 ;
     RECT  40.2 2.137 40.32 2.151 ;
     RECT  24 2.151 24.312 13.621 ;
     RECT  25.344 13.045 25.368 13.621 ;
     RECT  24 13.621 25.368 13.667 ;
     RECT  34.8 2.151 35.112 23.845 ;
     RECT  13.2 2.151 13.512 30.757 ;
     RECT  13.2 30.757 13.608 31.189 ;
     RECT  40.2 2.151 40.512 31.525 ;
     RECT  40.2 31.525 40.632 31.715 ;
     RECT  13.104 31.189 13.608 32.483 ;
     RECT  38.016 28.981 38.04 32.531 ;
     RECT  34.128 23.845 35.112 34.069 ;
     RECT  2.4 2.151 2.712 35.077 ;
     RECT  0.144 34.597 0.168 35.459 ;
     RECT  38.112 35.077 38.136 36.085 ;
     RECT  37.824 36.085 38.136 36.131 ;
     RECT  34.128 34.069 35.88 36.229 ;
     RECT  32.832 34.741 32.856 36.803 ;
     RECT  37.824 36.131 37.848 36.899 ;
     RECT  0.192 36.229 0.216 37.525 ;
     RECT  0.192 37.525 0.552 37.715 ;
     RECT  0.192 37.715 0.264 37.765 ;
     RECT  38.976 37.525 39 37.955 ;
     RECT  24 13.667 24.792 38.147 ;
     RECT  26.64 1.763 26.664 38.149 ;
     RECT  2.4 35.077 3.48 38.629 ;
     RECT  0.144 37.765 0.264 39.253 ;
     RECT  13.104 32.483 13.512 40.165 ;
     RECT  34.128 36.229 36.6 40.165 ;
     RECT  24 38.147 24.312 40.405 ;
     RECT  25.92 38.149 26.664 40.405 ;
     RECT  2.4 38.629 3.528 40.499 ;
     RECT  0.144 39.253 0.312 40.741 ;
     RECT  34.128 40.165 36.936 40.789 ;
     RECT  38.352 39.877 38.376 40.789 ;
     RECT  34.128 40.789 38.376 40.979 ;
     RECT  6.24 31.141 6.264 40.981 ;
     RECT  0.144 40.741 0.36 41.123 ;
     RECT  0.24 41.123 0.36 41.171 ;
     RECT  0.24 41.171 0.264 41.219 ;
     RECT  2.4 40.499 3.48 41.461 ;
     RECT  2.304 41.461 3.48 41.605 ;
     RECT  2.304 41.605 4.392 41.651 ;
     RECT  6.24 40.981 6.552 41.843 ;
     RECT  12.24 40.165 13.512 42.085 ;
     RECT  2.304 41.651 3.24 42.517 ;
     RECT  2.064 42.517 3.24 42.707 ;
     RECT  38.352 40.979 38.376 42.755 ;
     RECT  22.896 38.725 22.92 42.949 ;
     RECT  22.8 42.949 22.92 42.995 ;
     RECT  12.24 42.085 13.992 43.379 ;
     RECT  2.304 42.707 3.24 44.003 ;
     RECT  28.32 42.613 28.344 44.101 ;
     RECT  28.032 44.101 28.344 44.147 ;
     RECT  24 40.405 26.664 44.387 ;
     RECT  34.128 40.979 36.936 44.437 ;
     RECT  12.24 43.379 13.512 44.483 ;
     RECT  22.8 42.995 22.824 44.483 ;
     RECT  28.032 44.147 28.056 44.483 ;
     RECT  4.368 41.651 4.392 44.579 ;
     RECT  42.96 44.533 42.984 44.723 ;
     RECT  7.8 2.151 8.112 44.917 ;
     RECT  7.8 44.917 8.952 45.013 ;
     RECT  13.104 44.483 13.512 45.013 ;
     RECT  25.68 44.387 26.664 45.059 ;
     RECT  38.64 45.301 38.664 45.587 ;
     RECT  24 44.387 24.312 45.781 ;
     RECT  25.92 45.059 26.664 45.827 ;
     RECT  33.264 44.437 36.936 45.829 ;
     RECT  33.264 45.829 37.224 45.875 ;
     RECT  0.144 46.021 0.168 46.117 ;
     RECT  33.264 45.875 35.544 46.117 ;
     RECT  13.104 45.013 13.656 46.451 ;
     RECT  0.144 46.117 0.36 46.547 ;
     RECT  33.216 46.117 35.544 46.739 ;
     RECT  16.56 40.981 16.584 46.787 ;
     RECT  33.216 46.739 35.112 46.787 ;
     RECT  36.576 45.875 37.224 46.787 ;
     RECT  0.144 46.547 0.264 46.883 ;
     RECT  4.512 45.925 4.536 47.171 ;
     RECT  27.936 46.165 27.96 47.171 ;
     RECT  29.4 2.151 29.712 47.269 ;
     RECT  0.144 46.883 0.216 47.363 ;
     RECT  2.4 44.003 3.24 47.845 ;
     RECT  11.424 46.357 11.448 47.891 ;
     RECT  0.192 47.363 0.216 47.939 ;
     RECT  24 45.781 24.552 48.085 ;
     RECT  13.104 46.451 13.512 48.229 ;
     RECT  18.6 2.151 18.912 48.421 ;
     RECT  2.4 47.845 3.912 48.611 ;
     RECT  13.104 48.229 13.608 48.901 ;
     RECT  28.464 47.269 29.712 48.947 ;
     RECT  7.8 45.013 9.096 48.997 ;
     RECT  21.6 46.069 21.624 48.997 ;
     RECT  13.056 48.901 13.608 49.139 ;
     RECT  7.8 48.997 9.864 49.187 ;
     RECT  21.504 48.997 21.624 49.237 ;
     RECT  20.592 49.237 21.624 49.379 ;
     RECT  13.2 49.139 13.608 49.381 ;
     RECT  24 48.085 25.032 49.429 ;
     RECT  38.88 49.237 38.904 49.523 ;
     RECT  43.008 49.189 43.032 49.571 ;
     RECT  23.376 49.429 25.032 49.573 ;
     RECT  30.816 48.421 30.84 49.715 ;
     RECT  13.2 49.381 13.656 49.717 ;
     RECT  0.144 48.997 0.168 50.053 ;
     RECT  12 48.901 12.024 50.149 ;
     RECT  29.4 48.947 29.712 50.293 ;
     RECT  23.376 49.573 25.08 50.339 ;
     RECT  2.4 48.611 3.24 50.389 ;
     RECT  2.4 50.389 3.912 50.581 ;
     RECT  5.136 48.901 5.16 50.723 ;
     RECT  6.24 41.843 6.264 50.725 ;
     RECT  18.24 48.421 18.912 50.771 ;
     RECT  11.376 50.149 12.024 50.819 ;
     RECT  5.808 50.725 6.264 50.867 ;
     RECT  11.376 50.819 11.4 50.869 ;
     RECT  38.736 50.725 38.76 51.109 ;
     RECT  7.8 49.187 9.096 51.347 ;
     RECT  10.848 50.869 11.4 51.347 ;
     RECT  7.8 51.347 8.568 51.443 ;
     RECT  38.352 51.109 38.76 51.445 ;
     RECT  38.352 51.445 39.192 51.731 ;
     RECT  7.8 51.443 8.112 51.829 ;
     RECT  13.2 49.717 14.568 51.875 ;
     RECT  10.848 51.347 11.256 51.923 ;
     RECT  23.904 50.339 25.08 51.923 ;
     RECT  36.576 46.787 36.936 51.923 ;
     RECT  11.232 51.923 11.256 52.019 ;
     RECT  14.544 51.875 14.568 52.163 ;
     RECT  2.304 50.581 3.912 52.165 ;
     RECT  26.64 45.827 26.664 52.165 ;
     RECT  43.008 51.445 43.032 52.211 ;
     RECT  0.144 50.053 0.312 52.597 ;
     RECT  16.992 51.109 17.016 52.739 ;
     RECT  24 51.923 25.08 52.885 ;
     RECT  36.576 51.923 36.6 52.933 ;
     RECT  38.352 51.731 38.376 52.933 ;
     RECT  36.576 52.933 38.376 52.979 ;
     RECT  13.2 51.875 13.512 53.029 ;
     RECT  21.504 49.379 21.624 53.123 ;
     RECT  13.104 53.029 13.512 53.171 ;
     RECT  36.576 52.979 37.416 53.317 ;
     RECT  18.6 50.771 18.912 53.365 ;
     RECT  40.2 31.715 40.512 53.365 ;
     RECT  36.096 53.317 37.416 53.459 ;
     RECT  10.896 53.125 10.92 53.507 ;
     RECT  39.744 53.365 40.512 53.555 ;
     RECT  0.144 52.597 0.456 53.701 ;
     RECT  2.304 52.165 4.008 53.795 ;
     RECT  31.92 52.981 31.944 54.131 ;
     RECT  26.208 52.165 26.664 54.179 ;
     RECT  2.304 53.795 3.48 54.371 ;
     RECT  23.328 52.885 25.08 54.371 ;
     RECT  7.44 51.829 8.112 54.565 ;
     RECT  7.44 54.565 8.568 54.755 ;
     RECT  6.24 50.867 6.264 54.757 ;
     RECT  18.6 53.365 19.416 54.851 ;
     RECT  33.12 48.373 33.144 54.853 ;
     RECT  6.24 54.757 6.648 54.899 ;
     RECT  29.4 50.293 29.832 54.947 ;
     RECT  36.576 53.459 37.416 55.093 ;
     RECT  36.576 55.093 37.704 55.139 ;
     RECT  0.144 53.701 0.6 55.141 ;
     RECT  0.144 55.141 0.648 55.237 ;
     RECT  13.2 53.171 13.512 55.237 ;
     RECT  15.504 52.357 15.528 55.331 ;
     RECT  0.144 55.237 0.696 55.475 ;
     RECT  26.64 54.179 26.664 55.525 ;
     RECT  28.32 53.557 28.344 55.525 ;
     RECT  0.144 55.475 0.648 55.619 ;
     RECT  7.8 54.755 8.568 55.715 ;
     RECT  2.4 54.371 3.48 55.717 ;
     RECT  21.6 53.123 21.624 55.717 ;
     RECT  0.144 55.619 0.552 55.763 ;
     RECT  12.864 55.237 13.512 55.859 ;
     RECT  21.36 55.717 21.624 55.909 ;
     RECT  26.64 55.525 28.344 56.051 ;
     RECT  21.264 55.909 21.624 56.195 ;
     RECT  23.328 54.371 24.552 56.197 ;
     RECT  5.184 53.941 5.208 56.243 ;
     RECT  26.736 56.051 28.344 56.243 ;
     RECT  21.36 56.195 21.624 56.291 ;
     RECT  38.688 56.005 38.712 56.435 ;
     RECT  23.328 56.197 25.176 56.483 ;
     RECT  37.68 55.139 37.704 56.531 ;
     RECT  27.504 56.243 28.344 56.533 ;
     RECT  29.4 54.947 29.712 56.533 ;
     RECT  24 56.483 25.176 56.579 ;
     RECT  27.504 56.533 29.712 56.675 ;
     RECT  21.456 56.291 21.624 56.819 ;
     RECT  0.192 55.763 0.552 56.965 ;
     RECT  17.232 56.389 17.256 57.011 ;
     RECT  36.576 55.139 36.6 57.059 ;
     RECT  2.4 55.717 3.96 57.107 ;
     RECT  7.8 55.715 8.112 57.205 ;
     RECT  32.448 54.853 33.144 57.251 ;
     RECT  28.848 56.675 29.712 57.301 ;
     RECT  2.4 57.107 3.912 57.635 ;
     RECT  34.128 46.787 35.112 57.685 ;
     RECT  40.2 53.555 40.512 57.877 ;
     RECT  28.848 57.301 30.264 58.115 ;
     RECT  38.688 58.069 38.712 58.117 ;
     RECT  12.912 55.859 13.512 58.259 ;
     RECT  9.696 57.541 9.72 58.355 ;
     RECT  32.448 57.251 32.472 58.357 ;
     RECT  15.936 55.957 15.96 58.403 ;
     RECT  31.824 58.357 32.472 58.403 ;
     RECT  38.304 58.117 38.712 58.403 ;
     RECT  22.8 57.205 22.824 58.547 ;
     RECT  39.984 57.877 40.512 58.643 ;
     RECT  2.4 57.635 3.24 58.693 ;
     RECT  6.24 54.899 6.264 58.693 ;
     RECT  7.488 57.205 8.112 58.693 ;
     RECT  0.144 56.965 0.552 58.787 ;
     RECT  5.136 56.677 5.16 58.835 ;
     RECT  14.592 58.309 14.616 58.835 ;
     RECT  6.24 58.693 8.112 58.883 ;
     RECT  2.304 58.693 3.24 58.931 ;
     RECT  24 56.579 24.312 58.981 ;
     RECT  25.824 57.541 25.848 58.981 ;
     RECT  38.304 58.403 38.664 59.077 ;
     RECT  0.288 58.787 0.552 59.123 ;
     RECT  24 58.981 24.408 59.123 ;
     RECT  25.824 58.981 26.328 59.123 ;
     RECT  25.824 59.123 25.848 59.315 ;
     RECT  38.016 59.077 38.664 59.605 ;
     RECT  20.448 57.829 20.472 59.893 ;
     RECT  21.6 56.819 21.624 59.893 ;
     RECT  38.016 59.605 38.76 59.987 ;
     RECT  28.896 58.115 30.264 59.989 ;
     RECT  6.24 58.883 6.264 60.085 ;
     RECT  9.648 58.645 9.672 60.275 ;
     RECT  20.448 59.893 21.624 60.419 ;
     RECT  0.288 59.123 0.312 60.467 ;
     RECT  27.504 56.675 27.528 60.467 ;
     RECT  7.488 58.883 8.112 60.515 ;
     RECT  43.008 60.469 43.032 60.659 ;
     RECT  18.6 54.851 18.912 61.333 ;
     RECT  20.448 60.419 20.472 61.379 ;
     RECT  28.512 59.989 30.264 61.379 ;
     RECT  17.952 61.333 18.912 61.475 ;
     RECT  16.56 59.653 16.584 61.523 ;
     RECT  7.632 60.515 8.112 61.763 ;
     RECT  5.664 60.085 6.264 62.195 ;
     RECT  38.736 59.987 38.76 62.195 ;
     RECT  25.536 60.421 25.56 62.581 ;
     RECT  5.76 62.195 6.264 62.771 ;
     RECT  25.536 62.581 26.232 62.771 ;
     RECT  31.824 58.403 31.848 62.771 ;
     RECT  0.144 61.189 0.168 62.819 ;
     RECT  21.6 60.419 21.624 62.819 ;
     RECT  6.192 62.771 6.264 63.061 ;
     RECT  7.8 61.763 8.112 63.061 ;
     RECT  24 59.123 24.312 63.061 ;
     RECT  13.104 58.259 13.512 63.107 ;
     RECT  34.128 57.685 35.352 63.155 ;
     RECT  13.2 63.107 13.512 63.253 ;
     RECT  34.128 63.155 35.208 64.357 ;
     RECT  9.216 62.917 9.24 64.835 ;
     RECT  34.128 64.357 35.256 64.931 ;
     RECT  27.312 60.661 27.336 65.027 ;
     RECT  13.2 63.253 14.28 65.365 ;
     RECT  13.2 65.365 14.712 65.411 ;
     RECT  6.192 63.061 8.112 65.509 ;
     RECT  29.4 61.379 30.264 65.603 ;
     RECT  32.208 64.165 32.232 65.603 ;
     RECT  26.208 62.771 26.232 65.747 ;
     RECT  5.328 65.509 8.112 65.843 ;
     RECT  18.6 61.475 18.912 66.085 ;
     RECT  14.688 65.411 14.712 66.467 ;
     RECT  38.544 66.085 38.568 66.707 ;
     RECT  6.096 65.843 8.112 67.283 ;
     RECT  11.952 66.085 11.976 67.859 ;
     RECT  17.904 66.085 18.912 67.859 ;
     RECT  34.128 64.931 35.208 67.859 ;
     RECT  6.864 67.283 8.112 67.909 ;
     RECT  9.12 66.757 9.144 67.909 ;
     RECT  6.864 67.909 9.144 67.955 ;
     RECT  2.4 58.931 3.24 68.483 ;
     RECT  0.144 68.293 0.168 68.675 ;
     RECT  6.864 67.955 8.808 68.675 ;
     RECT  34.176 67.859 35.208 69.203 ;
     RECT  6.864 68.675 8.112 69.443 ;
     RECT  38.256 67.237 38.28 69.443 ;
     RECT  34.8 69.203 35.208 69.587 ;
     RECT  23.04 63.061 24.312 70.259 ;
     RECT  2.4 68.483 2.712 70.837 ;
     RECT  2.4 70.837 2.808 70.979 ;
     RECT  18.6 67.859 18.912 71.413 ;
     RECT  18.6 71.413 19.032 71.797 ;
     RECT  11.904 68.341 11.928 71.843 ;
     RECT  15.792 67.813 15.816 71.843 ;
     RECT  0.144 71.941 0.168 71.989 ;
     RECT  0.144 71.989 0.264 72.131 ;
     RECT  37.008 70.645 37.032 72.133 ;
     RECT  0.24 72.131 0.264 72.179 ;
     RECT  37.008 72.133 37.32 72.179 ;
     RECT  17.952 71.797 19.032 72.275 ;
     RECT  37.296 72.179 37.32 72.707 ;
     RECT  5.76 71.221 5.784 73.523 ;
     RECT  7.2 69.443 8.112 74.437 ;
     RECT  7.2 74.437 9.096 75.395 ;
     RECT  9.168 75.685 9.192 75.827 ;
     RECT  17.952 72.275 18.912 75.925 ;
     RECT  4.176 74.053 4.2 76.211 ;
     RECT  2.4 70.979 2.712 76.885 ;
     RECT  0.144 77.029 0.168 77.461 ;
     RECT  7.2 75.395 8.112 77.555 ;
     RECT  7.488 77.555 8.112 77.893 ;
     RECT  7.488 77.893 8.808 77.939 ;
     RECT  32.352 69.829 32.376 77.987 ;
     RECT  0.144 77.461 0.264 78.707 ;
     RECT  0.144 78.707 0.168 78.995 ;
     RECT  17.808 75.925 18.912 79.283 ;
     RECT  2.304 76.885 2.712 79.859 ;
     RECT  7.8 77.939 8.808 80.387 ;
     RECT  0.192 80.053 0.216 80.869 ;
     RECT  0.144 80.869 0.216 82.115 ;
     RECT  4.8 80.149 4.824 82.835 ;
     RECT  0.192 82.115 0.216 83.507 ;
     RECT  0.144 83.605 0.168 86.099 ;
     RECT  2.4 79.859 2.712 105.849 ;
     RECT  7.8 80.387 8.112 105.849 ;
     RECT  13.2 65.411 13.512 105.849 ;
     RECT  18.6 79.283 18.912 105.849 ;
     RECT  24 70.259 24.312 105.849 ;
     RECT  29.4 65.603 29.712 105.849 ;
     RECT  34.8 69.587 35.112 105.849 ;
     RECT  40.2 58.643 40.512 105.849 ;
     RECT  2.4 105.849 2.52 105.863 ;
     RECT  7.8 105.849 7.92 105.863 ;
     RECT  13.2 105.849 13.32 105.863 ;
     RECT  18.6 105.849 18.72 105.863 ;
     RECT  24 105.849 24.12 105.863 ;
     RECT  29.4 105.849 29.52 105.863 ;
     RECT  34.8 105.849 34.92 105.863 ;
     RECT  40.2 105.849 40.32 105.863 ;
  END
END hfd_att_su_relay
END LIBRARY
